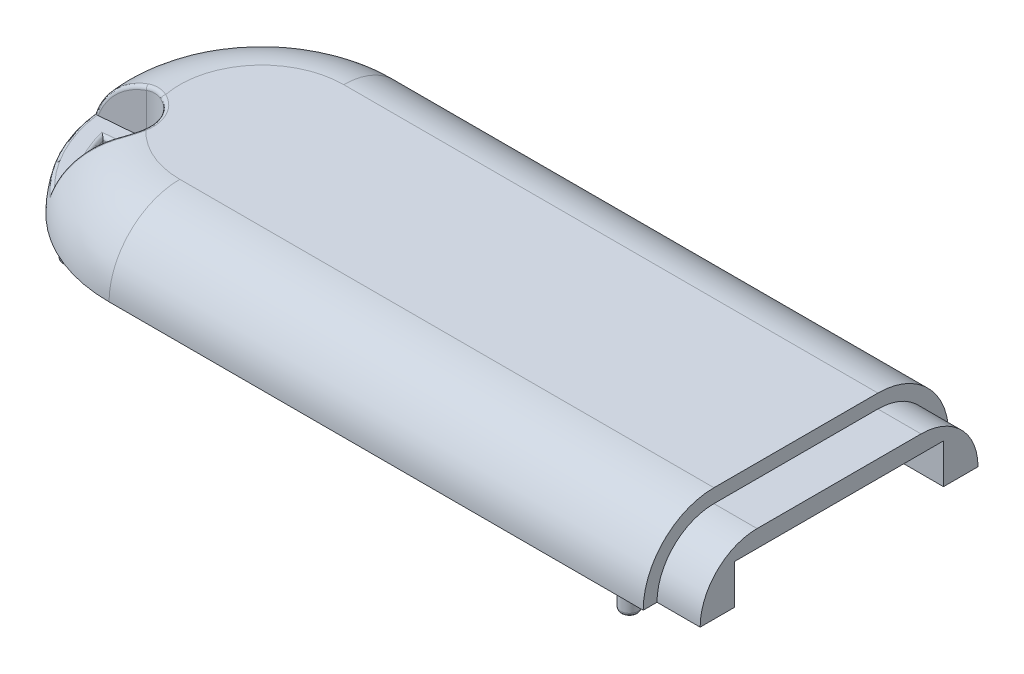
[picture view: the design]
ISO-10303-21;
HEADER;
FILE_DESCRIPTION(('STEP AP214'),'2;1');
FILE_NAME('part.step','',(''),(''),'','','');
FILE_SCHEMA(('AUTOMOTIVE_DESIGN { 1 0 10303 214 1 1 1 1 }'));
ENDSEC;
DATA;
#1=APPLICATION_CONTEXT('core data for automotive mechanical design processes');
#2=APPLICATION_PROTOCOL_DEFINITION('international standard','automotive_design',2000,#1);
#3=PRODUCT_CONTEXT('',#1,'mechanical');
#4=PRODUCT('Part','Part','',(#3));
#5=PRODUCT_RELATED_PRODUCT_CATEGORY('part','',(#4));
#6=PRODUCT_DEFINITION_FORMATION('','',#4);
#7=PRODUCT_DEFINITION_CONTEXT('part definition',#1,'design');
#8=PRODUCT_DEFINITION('design','',#6,#7);
#9=PRODUCT_DEFINITION_SHAPE('','',#8);
#10=(LENGTH_UNIT() NAMED_UNIT(*) SI_UNIT(.MILLI.,.METRE.));
#11=(NAMED_UNIT(*) PLANE_ANGLE_UNIT() SI_UNIT($,.RADIAN.));
#12=(NAMED_UNIT(*) SI_UNIT($,.STERADIAN.) SOLID_ANGLE_UNIT());
#13=UNCERTAINTY_MEASURE_WITH_UNIT(LENGTH_MEASURE(1.E-05),#10,'distance_accuracy_value','');
#14=(GEOMETRIC_REPRESENTATION_CONTEXT(3) GLOBAL_UNCERTAINTY_ASSIGNED_CONTEXT((#13)) GLOBAL_UNIT_ASSIGNED_CONTEXT((#10,
#11,#12)) REPRESENTATION_CONTEXT('',''));
#15=CARTESIAN_POINT('',(0.,0.,0.));
#16=DIRECTION('',(0.,0.,1.));
#17=DIRECTION('',(1.,0.,0.));
#18=AXIS2_PLACEMENT_3D('',#15,#16,#17);
#19=CARTESIAN_POINT('',(0.,0.,0.));
#20=DIRECTION('',(0.,1.,0.));
#21=DIRECTION('',(0.,0.,1.));
#22=AXIS2_PLACEMENT_3D('',#19,#20,#21);
#23=TOROIDAL_SURFACE('',#22,4.75,2.7);
#24=CARTESIAN_POINT('',(0.,0.5,0.));
#25=DIRECTION('',(0.,-1.,0.));
#26=DIRECTION('',(0.,0.,-1.));
#27=AXIS2_PLACEMENT_3D('',#24,#25,#26);
#28=CIRCLE('',#27,7.40329983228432);
#29=CARTESIAN_POINT('',(0.,0.5,-7.40329983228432));
#30=VERTEX_POINT('',#29);
#31=CARTESIAN_POINT('',(-7.36268520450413,0.5,-0.774412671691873));
#32=VERTEX_POINT('',#31);
#33=EDGE_CURVE('E1084',#30,#32,#28,.F.);
#34=ORIENTED_EDGE('',*,*,#33,.F.);
#35=CARTESIAN_POINT('',(0.,0.,-4.75));
#36=DIRECTION('',(1.,0.,0.));
#37=DIRECTION('',(0.,0.,-1.));
#38=AXIS2_PLACEMENT_3D('',#35,#36,#37);
#39=CIRCLE('',#38,2.7);
#40=CARTESIAN_POINT('',(0.,2.7,-4.75));
#41=VERTEX_POINT('',#40);
#42=EDGE_CURVE('E870',#30,#41,#39,.T.);
#43=ORIENTED_EDGE('',*,*,#42,.T.);
#44=CARTESIAN_POINT('',(0.,2.7,0.));
#45=DIRECTION('',(0.,1.,0.));
#46=DIRECTION('',(0.,0.,1.));
#47=AXIS2_PLACEMENT_3D('',#44,#45,#46);
#48=CIRCLE('',#47,4.75);
#49=CARTESIAN_POINT('',(-4.68321334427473,2.7,-0.793733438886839));
#50=VERTEX_POINT('',#49);
#51=EDGE_CURVE('E864',#41,#50,#48,.T.);
#52=ORIENTED_EDGE('',*,*,#51,.T.);
#53=CARTESIAN_POINT('',(-3.42079294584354,2.3539734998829,-0.215508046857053));
#54=CARTESIAN_POINT('',(-3.47788162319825,2.38742536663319,-0.255686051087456));
#55=CARTESIAN_POINT('',(-3.53679266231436,2.41916997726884,-0.294791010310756));
#56=CARTESIAN_POINT('',(-3.6583116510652,2.47858652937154,-0.370546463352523));
#57=CARTESIAN_POINT('',(-3.7209263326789,2.5062507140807,-0.407192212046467));
#58=CARTESIAN_POINT('',(-3.84992042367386,2.55680759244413,-0.477693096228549));
#59=CARTESIAN_POINT('',(-3.9163125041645,2.57968285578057,-0.51153777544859));
#60=CARTESIAN_POINT('',(-4.05228294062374,2.61988542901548,-0.575789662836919));
#61=CARTESIAN_POINT('',(-4.12185873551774,2.63721711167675,-0.60619956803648));
#62=CARTESIAN_POINT('',(-4.30790852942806,2.6746851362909,-0.680828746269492));
#63=CARTESIAN_POINT('',(-4.42671219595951,2.68989698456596,-0.721918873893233));
#64=CARTESIAN_POINT('',(-4.66838886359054,2.7028523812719,-0.792127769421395));
#65=CARTESIAN_POINT('',(-4.7912502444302,2.7006421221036,-0.821277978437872));
#66=CARTESIAN_POINT('',(-5.0378610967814,2.67859738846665,-0.867041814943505));
#67=CARTESIAN_POINT('',(-5.16161146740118,2.65874146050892,-0.883640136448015));
#68=CARTESIAN_POINT('',(-5.40633578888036,2.60206237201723,-0.90457184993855));
#69=CARTESIAN_POINT('',(-5.52730766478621,2.56522693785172,-0.908896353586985));
#70=CARTESIAN_POINT('',(-5.69292352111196,2.50256274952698,-0.907277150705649));
#71=CARTESIAN_POINT('',(-5.74019864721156,2.4832047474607,-0.905908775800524));
#72=CARTESIAN_POINT('',(-5.83343472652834,2.44209645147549,-0.901507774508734));
#73=CARTESIAN_POINT('',(-5.87939945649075,2.42035414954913,-0.898480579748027));
#74=CARTESIAN_POINT('',(-5.92472459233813,2.39743450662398,-0.89468786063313));
#75=B_SPLINE_CURVE_WITH_KNOTS('',3,(#53,#54,#55,#56,#57,#58,#59,#60,#61,#62,#63,#64,#65,#66,#67,
#68,#69,#70,#71,#72,#73,#74),.UNSPECIFIED.,.F.,.F.,(4,2,2,2,2,2,2,2,2,2,4),(0.,
0.232257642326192,0.464951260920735,0.698477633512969,0.931819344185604,1.30984644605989,
1.68687159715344,2.06435576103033,2.44211321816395,2.59534610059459,2.74808021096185),.UNSPECIFIED.);
#76=CARTESIAN_POINT('',(-5.92452459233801,2.39753564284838,-0.894704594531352));
#77=VERTEX_POINT('',#76);
#78=EDGE_CURVE('E787',#50,#77,#75,.T.);
#79=ORIENTED_EDGE('',*,*,#78,.T.);
#80=CARTESIAN_POINT('',(-7.41005437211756,-0.0002,-0.77045057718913));
#81=CARTESIAN_POINT('',(-7.41006776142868,0.074673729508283,-0.770449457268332));
#82=CARTESIAN_POINT('',(-7.40690693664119,0.149544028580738,-0.770713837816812));
#83=CARTESIAN_POINT('',(-7.39429669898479,0.298744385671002,-0.771768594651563));
#84=CARTESIAN_POINT('',(-7.38484772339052,0.373074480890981,-0.772558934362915));
#85=CARTESIAN_POINT('',(-7.35973704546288,0.520577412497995,-0.774659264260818));
#86=CARTESIAN_POINT('',(-7.34408328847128,0.593751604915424,-0.775968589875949));
#87=CARTESIAN_POINT('',(-7.30669763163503,0.738497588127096,-0.779095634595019));
#88=CARTESIAN_POINT('',(-7.28496579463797,0.810069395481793,-0.780913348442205));
#89=CARTESIAN_POINT('',(-7.21085476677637,1.0216638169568,-0.787112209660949));
#90=CARTESIAN_POINT('',(-7.14954457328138,1.15865576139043,-0.792240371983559));
#91=CARTESIAN_POINT('',(-7.00500644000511,1.42039988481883,-0.804329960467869));
#92=CARTESIAN_POINT('',(-6.92177295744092,1.54514895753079,-0.811291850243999));
#93=CARTESIAN_POINT('',(-6.73529747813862,1.7797913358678,-0.826889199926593));
#94=CARTESIAN_POINT('',(-6.63193591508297,1.88958885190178,-0.835534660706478));
#95=CARTESIAN_POINT('',(-6.40861580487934,2.09043949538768,-0.854213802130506));
#96=CARTESIAN_POINT('',(-6.28867809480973,2.18151580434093,-0.864245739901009));
#97=CARTESIAN_POINT('',(-6.12376430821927,2.28666466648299,-0.878039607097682));
#98=CARTESIAN_POINT('',(-6.08460921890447,2.31027004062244,-0.881314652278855));
#99=CARTESIAN_POINT('',(-6.0052498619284,2.35545961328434,-0.887952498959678));
#100=CARTESIAN_POINT('',(-5.96504759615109,2.37704735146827,-0.891315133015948));
#101=CARTESIAN_POINT('',(-5.92432459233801,2.3976367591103,-0.894721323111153));
#102=B_SPLINE_CURVE_WITH_KNOTS('',3,(#80,#81,#82,#83,#84,#85,#86,#87,#88,#89,#90,#91,#92,#93,
#94,#95,#96,#97,#98,#99,#100,#101),.UNSPECIFIED.,.F.,.F.,(4,2,2,2,2,2,2,2,2,2,4),(0.,
0.224547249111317,0.449078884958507,0.673323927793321,0.897566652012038,1.34578059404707,
1.79410796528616,2.24518456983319,2.69569921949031,2.83317292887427,2.97040074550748),.UNSPECIFIED.);
#103=EDGE_CURVE('E769',#32,#77,#102,.T.);
#104=ORIENTED_EDGE('',*,*,#103,.F.);
#105=EDGE_LOOP('',(#34,#43,#52,#79,#104));
#106=FACE_BOUND('',#105,.T.);
#107=ADVANCED_FACE('F85',(#106),#23,.F.);
#108=CARTESIAN_POINT('',(0.,0.5,0.));
#109=DIRECTION('',(0.,-1.,0.));
#110=DIRECTION('',(0.,0.,-1.));
#111=AXIS2_PLACEMENT_3D('',#108,#109,#110);
#112=CIRCLE('',#111,7.40329983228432);
#113=CARTESIAN_POINT('',(-3.63803915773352,0.5,6.44775305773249));
#114=VERTEX_POINT('',#113);
#115=CARTESIAN_POINT('',(0.,0.5,7.40329983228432));
#116=VERTEX_POINT('',#115);
#117=EDGE_CURVE('E1081',#114,#116,#112,.F.);
#118=ORIENTED_EDGE('',*,*,#117,.F.);
#119=CARTESIAN_POINT('',(-2.70599614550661,2.39766760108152,5.34556070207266));
#120=CARTESIAN_POINT('',(-2.75018498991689,2.36320321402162,5.39781645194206));
#121=CARTESIAN_POINT('',(-2.79344880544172,2.32589362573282,5.44897830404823));
#122=CARTESIAN_POINT('',(-2.87782626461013,2.24582969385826,5.54875931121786));
#123=CARTESIAN_POINT('',(-2.91893975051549,2.20307495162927,5.59737827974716));
#124=CARTESIAN_POINT('',(-2.99869787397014,2.11238512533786,5.69169666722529));
#125=CARTESIAN_POINT('',(-3.0373432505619,2.06445160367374,5.73739696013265));
#126=CARTESIAN_POINT('',(-3.11187878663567,1.96373092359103,5.82553934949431));
#127=CARTESIAN_POINT('',(-3.14776907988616,1.91094400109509,5.86798160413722));
#128=CARTESIAN_POINT('',(-3.25096207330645,1.74568881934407,5.99001302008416));
#129=CARTESIAN_POINT('',(-3.31378028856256,1.62633364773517,6.06429903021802));
#130=CARTESIAN_POINT('',(-3.42532474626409,1.37282402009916,6.19620651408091));
#131=CARTESIAN_POINT('',(-3.47405085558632,1.23866942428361,6.25382783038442));
#132=CARTESIAN_POINT('',(-3.55537391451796,0.961322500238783,6.34999684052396));
#133=CARTESIAN_POINT('',(-3.58818137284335,0.818278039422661,6.38879347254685));
#134=CARTESIAN_POINT('',(-3.63758389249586,0.525756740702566,6.44721468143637));
#135=CARTESIAN_POINT('',(-3.65420591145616,0.376291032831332,6.4668711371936));
#136=CARTESIAN_POINT('',(-3.6645868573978,0.188314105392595,6.4791471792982));
#137=CARTESIAN_POINT('',(-3.66614397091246,0.150620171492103,6.48098855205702));
#138=CARTESIAN_POINT('',(-3.6682162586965,0.0752220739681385,6.48343914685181));
#139=CARTESIAN_POINT('',(-3.66873304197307,0.0375180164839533,6.4840502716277));
#140=CARTESIAN_POINT('',(-3.66873259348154,-0.000199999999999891,6.48404974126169));
#141=B_SPLINE_CURVE_WITH_KNOTS('',3,(#119,#120,#121,#122,#123,#124,#125,#126,#127,#128,#129,
#130,#131,#132,#133,#134,#135,#136,#137,#138,#139,#140),.UNSPECIFIED.,.F.,.F.,(4,2,2,2,2,2,2,2,
2,2,4),(0.,0.229803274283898,0.459623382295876,0.689374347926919,0.919114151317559,
1.37863130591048,1.83815280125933,2.29141969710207,2.74393035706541,2.85722316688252,
2.97034061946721),.UNSPECIFIED.);
#142=CARTESIAN_POINT('',(-2.70616527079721,2.39753564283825,5.34576070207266));
#143=VERTEX_POINT('',#142);
#144=EDGE_CURVE('E1004',#143,#114,#141,.T.);
#145=ORIENTED_EDGE('',*,*,#144,.F.);
#146=CARTESIAN_POINT('',(-2.70633440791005,2.3974036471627,5.34596070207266));
#147=CARTESIAN_POINT('',(-2.66864775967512,2.42681168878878,5.30140023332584));
#148=CARTESIAN_POINT('',(-2.63138005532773,2.45428231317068,5.25524951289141));
#149=CARTESIAN_POINT('',(-2.55804237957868,2.50516944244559,5.1598214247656));
#150=CARTESIAN_POINT('',(-2.52197305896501,2.52858377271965,5.11054239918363));
#151=CARTESIAN_POINT('',(-2.41816889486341,2.59121860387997,4.96105632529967));
#152=CARTESIAN_POINT('',(-2.35265281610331,2.62451945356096,4.8566509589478));
#153=CARTESIAN_POINT('',(-2.26301693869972,2.66063239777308,4.69651252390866));
#154=CARTESIAN_POINT('',(-2.23530264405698,2.67025916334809,4.64418238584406));
#155=CARTESIAN_POINT('',(-2.18213263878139,2.6855619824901,4.53779836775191));
#156=CARTESIAN_POINT('',(-2.15667704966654,2.69123782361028,4.48374439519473));
#157=CARTESIAN_POINT('',(-2.10762153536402,2.69868817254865,4.37281829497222));
#158=CARTESIAN_POINT('',(-2.08408860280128,2.70035538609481,4.3159094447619));
#159=CARTESIAN_POINT('',(-2.03981587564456,2.69951661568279,4.20103660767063));
#160=CARTESIAN_POINT('',(-2.01907645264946,2.69701007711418,4.14307248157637));
#161=CARTESIAN_POINT('',(-1.99981816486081,2.69243649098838,4.08478180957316));
#162=B_SPLINE_CURVE_WITH_KNOTS('',3,(#146,#147,#148,#149,#150,#151,#152,#153,#154,#155,#156,
#157,#158,#159,#160,#161),.UNSPECIFIED.,.F.,.F.,(4,2,2,2,2,2,2,4),(0.,0.195937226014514,
0.391979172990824,0.772914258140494,0.952744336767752,1.13258408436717,1.31718629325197,
1.50181303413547),.UNSPECIFIED.);
#163=CARTESIAN_POINT('',(-2.06870125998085,2.7,4.27585957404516));
#164=VERTEX_POINT('',#163);
#165=EDGE_CURVE('E779',#143,#164,#162,.T.);
#166=ORIENTED_EDGE('',*,*,#165,.T.);
#167=CARTESIAN_POINT('',(0.,2.7,0.));
#168=DIRECTION('',(0.,1.,0.));
#169=DIRECTION('',(0.,0.,1.));
#170=AXIS2_PLACEMENT_3D('',#167,#168,#169);
#171=CIRCLE('',#170,4.75);
#172=CARTESIAN_POINT('',(0.,2.7,4.75));
#173=VERTEX_POINT('',#172);
#174=EDGE_CURVE('E869',#164,#173,#171,.T.);
#175=ORIENTED_EDGE('',*,*,#174,.T.);
#176=CARTESIAN_POINT('',(0.,0.,4.75));
#177=DIRECTION('',(-1.,0.,0.));
#178=DIRECTION('',(0.,0.,1.));
#179=AXIS2_PLACEMENT_3D('',#176,#177,#178);
#180=CIRCLE('',#179,2.7);
#181=EDGE_CURVE('E873',#116,#173,#180,.T.);
#182=ORIENTED_EDGE('',*,*,#181,.F.);
#183=EDGE_LOOP('',(#118,#145,#166,#175,#182));
#184=FACE_BOUND('',#183,.T.);
#185=ADVANCED_FACE('F753',(#184),#23,.F.);
#186=CARTESIAN_POINT('',(33.45,0.,4.75));
#187=DIRECTION('',(-1.,0.,0.));
#188=DIRECTION('',(0.,0.,1.));
#189=AXIS2_PLACEMENT_3D('',#186,#187,#188);
#190=CYLINDRICAL_SURFACE('',#189,2.7);
#191=CARTESIAN_POINT('',(29.55,0.,4.75));
#192=DIRECTION('',(1.,0.,0.));
#193=DIRECTION('',(0.,0.,-1.));
#194=AXIS2_PLACEMENT_3D('',#191,#192,#193);
#195=CIRCLE('',#194,2.7);
#196=CARTESIAN_POINT('',(29.55,1.65413192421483,6.88397459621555));
#197=VERTEX_POINT('',#196);
#198=CARTESIAN_POINT('',(29.55,2.7,4.75));
#199=VERTEX_POINT('',#198);
#200=EDGE_CURVE('E874',#197,#199,#195,.F.);
#201=ORIENTED_EDGE('',*,*,#200,.F.);
#202=CARTESIAN_POINT('',(29.55,1.65413192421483,6.88397459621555));
#203=CARTESIAN_POINT('',(29.5199788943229,1.67655530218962,6.8665976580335));
#204=CARTESIAN_POINT('',(29.4878307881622,1.6970168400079,6.85016512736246));
#205=CARTESIAN_POINT('',(29.4197369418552,1.73353284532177,6.82012609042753));
#206=CARTESIAN_POINT('',(29.3837764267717,1.74956922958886,6.80653123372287));
#207=CARTESIAN_POINT('',(29.308606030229,1.77661921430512,6.78321143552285));
#208=CARTESIAN_POINT('',(29.26938298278,1.7876111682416,6.77350319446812));
#209=CARTESIAN_POINT('',(29.1890064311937,1.80404166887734,6.75886954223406));
#210=CARTESIAN_POINT('',(29.1478572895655,1.809492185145,6.75393382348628));
#211=CARTESIAN_POINT('',(29.0673739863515,1.81451420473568,6.74938702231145));
#212=CARTESIAN_POINT('',(29.0280769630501,1.81441527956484,6.74947744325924));
#213=CARTESIAN_POINT('',(28.9500872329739,1.80915625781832,6.75423699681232));
#214=CARTESIAN_POINT('',(28.9113948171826,1.80399379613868,6.75890826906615));
#215=CARTESIAN_POINT('',(28.8369095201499,1.78901459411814,6.77225669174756));
#216=CARTESIAN_POINT('',(28.8010643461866,1.77934326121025,6.78080848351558));
#217=CARTESIAN_POINT('',(28.7318536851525,1.755713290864,6.80127127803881));
#218=CARTESIAN_POINT('',(28.6984881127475,1.741754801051,6.81318216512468));
#219=CARTESIAN_POINT('',(28.6325109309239,1.70880649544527,6.84056656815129));
#220=CARTESIAN_POINT('',(28.6001258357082,1.68952718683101,6.85623460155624));
#221=CARTESIAN_POINT('',(28.5392006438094,1.64707484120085,6.88959710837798));
#222=CARTESIAN_POINT('',(28.5106626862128,1.62389965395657,6.9072926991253));
#223=CARTESIAN_POINT('',(28.4439354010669,1.56157400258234,6.95309628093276));
#224=CARTESIAN_POINT('',(28.408223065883,1.52029476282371,6.98192119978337));
#225=CARTESIAN_POINT('',(28.3448888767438,1.43196281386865,7.03960235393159));
#226=CARTESIAN_POINT('',(28.3172838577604,1.38489837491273,7.06845853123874));
#227=CARTESIAN_POINT('',(28.2750937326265,1.29906075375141,7.11732490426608));
#228=CARTESIAN_POINT('',(28.2589833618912,1.26123063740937,7.13771558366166));
#229=CARTESIAN_POINT('',(28.2300022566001,1.18364794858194,7.17711241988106));
#230=CARTESIAN_POINT('',(28.2171331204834,1.14389443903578,7.19611789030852));
#231=CARTESIAN_POINT('',(28.1824911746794,1.02198812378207,7.25069164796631));
#232=CARTESIAN_POINT('',(28.1648140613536,0.937477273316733,7.28365120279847));
#233=CARTESIAN_POINT('',(28.1398048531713,0.78271824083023,7.33506673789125));
#234=CARTESIAN_POINT('',(28.1310817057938,0.713188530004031,7.35511452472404));
#235=CARTESIAN_POINT('',(28.1170020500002,0.572355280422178,7.38963304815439));
#236=CARTESIAN_POINT('',(28.1116485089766,0.501050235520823,7.40409886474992));
#237=CARTESIAN_POINT('',(28.1034947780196,0.358298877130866,7.42708486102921));
#238=CARTESIAN_POINT('',(28.1006624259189,0.286866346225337,7.43567959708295));
#239=CARTESIAN_POINT('',(28.0978771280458,0.179411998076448,7.44427191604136));
#240=CARTESIAN_POINT('',(28.0971925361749,0.143567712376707,7.44641938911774));
#241=CARTESIAN_POINT('',(28.0962857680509,0.0718169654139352,7.44928347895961));
#242=CARTESIAN_POINT('',(28.0960635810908,0.0359105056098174,7.45000012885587));
#243=CARTESIAN_POINT('',(28.0960607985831,0.,7.45));
#244=B_SPLINE_CURVE_WITH_KNOTS('',3,(#202,#203,#204,#205,#206,#207,#208,#209,#210,#211,#212,
#213,#214,#215,#216,#217,#218,#219,#220,#221,#222,#223,#224,#225,#226,#227,#228,#229,#230,#231,
#232,#233,#234,#235,#236,#237,#238,#239,#240,#241,#242,#243),.UNSPECIFIED.,.F.,.F.,(4,2,2,2,2,2,
2,2,2,2,2,2,2,2,2,2,2,2,2,2,4),(0.,0.123934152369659,0.248367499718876,0.373329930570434,
0.49802186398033,0.615316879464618,0.732666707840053,0.846469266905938,0.960267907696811,
1.0822449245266,1.20428948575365,1.38842890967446,1.57294804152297,1.71045038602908,
1.84802040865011,2.12421848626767,2.342588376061,2.56115030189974,2.77688238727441,
2.88460037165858,2.99231586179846),.UNSPECIFIED.);
#245=CARTESIAN_POINT('',(28.1120239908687,0.5,7.40329983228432));
#246=VERTEX_POINT('',#245);
#247=EDGE_CURVE('E418',#197,#246,#244,.T.);
#248=ORIENTED_EDGE('',*,*,#247,.T.);
#249=DIRECTION('',(-1.,0.,0.));
#250=VECTOR('',#249,1.);
#251=CARTESIAN_POINT('',(33.45,0.5,7.40329983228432));
#252=LINE('',#251,#250);
#253=EDGE_CURVE('E1090',#116,#246,#252,.F.);
#254=ORIENTED_EDGE('',*,*,#253,.F.);
#255=ORIENTED_EDGE('',*,*,#181,.T.);
#256=DIRECTION('',(1.,0.,0.));
#257=VECTOR('',#256,1.);
#258=CARTESIAN_POINT('',(0.,2.7,4.75));
#259=LINE('',#258,#257);
#260=EDGE_CURVE('E868',#173,#199,#259,.T.);
#261=ORIENTED_EDGE('',*,*,#260,.T.);
#262=EDGE_LOOP('',(#201,#248,#254,#255,#261));
#263=FACE_BOUND('',#262,.T.);
#264=ADVANCED_FACE('F434',(#263),#190,.F.);
#265=CARTESIAN_POINT('',(0.,0.,-4.75));
#266=DIRECTION('',(1.,0.,0.));
#267=DIRECTION('',(0.,0.,-1.));
#268=AXIS2_PLACEMENT_3D('',#265,#266,#267);
#269=CYLINDRICAL_SURFACE('',#268,2.7);
#270=DIRECTION('',(1.,0.,0.));
#271=VECTOR('',#270,1.);
#272=CARTESIAN_POINT('',(0.,0.5,-7.40329983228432));
#273=LINE('',#272,#271);
#274=CARTESIAN_POINT('',(28.1120239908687,0.5,-7.40329983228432));
#275=VERTEX_POINT('',#274);
#276=EDGE_CURVE('E1087',#275,#30,#273,.F.);
#277=ORIENTED_EDGE('',*,*,#276,.F.);
#278=CARTESIAN_POINT('',(28.0960607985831,0.,-7.45));
#279=CARTESIAN_POINT('',(28.096063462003,0.0354762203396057,-7.45000005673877));
#280=CARTESIAN_POINT('',(28.0962803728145,0.0709483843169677,-7.44930067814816));
#281=CARTESIAN_POINT('',(28.0971651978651,0.141833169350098,-7.44650547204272));
#282=CARTESIAN_POINT('',(28.0978331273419,0.177245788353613,-7.44440959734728));
#283=CARTESIAN_POINT('',(28.10054956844,0.283406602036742,-7.43602358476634));
#284=CARTESIAN_POINT('',(28.1033108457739,0.353984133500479,-7.42763506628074));
#285=CARTESIAN_POINT('',(28.1112354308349,0.494846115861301,-7.40523355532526));
#286=CARTESIAN_POINT('',(28.116423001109,0.565120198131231,-7.39116395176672));
#287=CARTESIAN_POINT('',(28.1300334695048,0.70398272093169,-7.35758616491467));
#288=CARTESIAN_POINT('',(28.1384535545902,0.772572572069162,-7.33808271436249));
#289=CARTESIAN_POINT('',(28.1619030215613,0.921323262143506,-7.28938526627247));
#290=CARTESIAN_POINT('',(28.1779370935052,1.00095444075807,-7.25902240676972));
#291=CARTESIAN_POINT('',(28.219222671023,1.15480262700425,-7.19200898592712));
#292=CARTESIAN_POINT('',(28.2444378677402,1.22903959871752,-7.15538349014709));
#293=CARTESIAN_POINT('',(28.2986826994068,1.34979994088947,-7.08909601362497));
#294=CARTESIAN_POINT('',(28.3246178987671,1.3982242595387,-7.06039322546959));
#295=CARTESIAN_POINT('',(28.3844154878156,1.48964732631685,-7.00252226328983));
#296=CARTESIAN_POINT('',(28.4182666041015,1.53265365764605,-6.97335480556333));
#297=CARTESIAN_POINT('',(28.4858506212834,1.60223996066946,-6.923526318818));
#298=CARTESIAN_POINT('',(28.5177526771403,1.63030767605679,-6.90247350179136));
#299=CARTESIAN_POINT('',(28.5868112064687,1.68134239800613,-6.86284873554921));
#300=CARTESIAN_POINT('',(28.6239660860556,1.70431094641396,-6.8442760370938));
#301=CARTESIAN_POINT('',(28.7034057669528,1.74442358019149,-6.81098933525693));
#302=CARTESIAN_POINT('',(28.7457338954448,1.76151315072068,-6.79631172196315));
#303=CARTESIAN_POINT('',(28.8340455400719,1.78877182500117,-6.77253044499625));
#304=CARTESIAN_POINT('',(28.8800260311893,1.79894659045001,-6.76342222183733));
#305=CARTESIAN_POINT('',(28.9668908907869,1.81093147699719,-6.75264334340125));
#306=CARTESIAN_POINT('',(29.0075275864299,1.81375337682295,-6.75007437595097));
#307=CARTESIAN_POINT('',(29.0887973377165,1.81391433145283,-6.7499289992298));
#308=CARTESIAN_POINT('',(29.129430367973,1.81125797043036,-6.75234841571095));
#309=CARTESIAN_POINT('',(29.2066826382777,1.80093376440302,-6.76163607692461));
#310=CARTESIAN_POINT('',(29.2433877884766,1.79361588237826,-6.76819337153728));
#311=CARTESIAN_POINT('',(29.3147785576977,1.77453221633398,-6.78499292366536));
#312=CARTESIAN_POINT('',(29.3494618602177,1.76276144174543,-6.7952393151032));
#313=CARTESIAN_POINT('',(29.413197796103,1.73630987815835,-6.81772832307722));
#314=CARTESIAN_POINT('',(29.4424784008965,1.7219623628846,-6.82972656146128));
#315=CARTESIAN_POINT('',(29.4983171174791,1.69023560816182,-6.85559361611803));
#316=CARTESIAN_POINT('',(29.5248838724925,1.6728665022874,-6.86945614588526));
#317=CARTESIAN_POINT('',(29.55,1.65413192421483,-6.88397459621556));
#318=B_SPLINE_CURVE_WITH_KNOTS('',3,(#278,#279,#280,#281,#282,#283,#284,#285,#286,#287,#288,
#289,#290,#291,#292,#293,#294,#295,#296,#297,#298,#299,#300,#301,#302,#303,#304,#305,#306,#307,
#308,#309,#310,#311,#312,#313,#314,#315,#316,#317),.UNSPECIFIED.,.F.,.F.,(4,2,2,2,2,2,2,2,2,2,2,
2,2,2,2,2,2,2,2,4),(0.,0.106412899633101,0.212829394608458,0.425942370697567,0.641233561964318,
0.856337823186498,1.11578711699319,1.37422130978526,1.55958309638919,1.7446824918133,
1.88641033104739,2.02809525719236,2.17106066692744,2.31390887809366,2.43570406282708,
2.55739737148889,2.67088579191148,2.78450178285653,2.8884400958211,2.99203632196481),.UNSPECIFIED.);
#319=CARTESIAN_POINT('',(29.55,1.65413192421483,-6.88397459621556));
#320=VERTEX_POINT('',#319);
#321=EDGE_CURVE('E396',#275,#320,#318,.T.);
#322=ORIENTED_EDGE('',*,*,#321,.T.);
#323=CARTESIAN_POINT('',(29.55,0.,-4.75));
#324=DIRECTION('',(1.,0.,0.));
#325=DIRECTION('',(0.,0.,-1.));
#326=AXIS2_PLACEMENT_3D('',#323,#324,#325);
#327=CIRCLE('',#326,2.7);
#328=CARTESIAN_POINT('',(29.55,2.7,-4.75));
#329=VERTEX_POINT('',#328);
#330=EDGE_CURVE('E892',#329,#320,#327,.F.);
#331=ORIENTED_EDGE('',*,*,#330,.F.);
#332=DIRECTION('',(1.,0.,0.));
#333=VECTOR('',#332,1.);
#334=CARTESIAN_POINT('',(0.,2.7,-4.75));
#335=LINE('',#334,#333);
#336=EDGE_CURVE('E884',#329,#41,#335,.F.);
#337=ORIENTED_EDGE('',*,*,#336,.T.);
#338=ORIENTED_EDGE('',*,*,#42,.F.);
#339=EDGE_LOOP('',(#277,#322,#331,#337,#338));
#340=FACE_BOUND('',#339,.T.);
#341=ADVANCED_FACE('F462',(#340),#269,.F.);
#342=CARTESIAN_POINT('',(-5.92452459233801,12.1296515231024,-0.894704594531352));
#343=DIRECTION('',(0.0833518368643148,0.,0.9965201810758));
#344=DIRECTION('',(0.9965201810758,0.,-0.0833518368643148));
#345=AXIS2_PLACEMENT_3D('',#342,#343,#344);
#346=PLANE('',#345);
#347=DIRECTION('',(0.9965201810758,0.,-0.0833518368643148));
#348=VECTOR('',#347,1.);
#349=CARTESIAN_POINT('',(-5.92452459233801,0.5,-0.894704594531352));
#350=LINE('',#349,#348);
#351=CARTESIAN_POINT('',(-5.92452459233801,0.5,-0.894704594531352));
#352=VERTEX_POINT('',#351);
#353=EDGE_CURVE('E1078',#32,#352,#350,.T.);
#354=ORIENTED_EDGE('',*,*,#353,.F.);
#355=ORIENTED_EDGE('',*,*,#103,.T.);
#356=DIRECTION('',(0.,-1.,0.));
#357=VECTOR('',#356,1.);
#358=CARTESIAN_POINT('',(-5.92452459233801,12.1296515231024,-0.894704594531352));
#359=LINE('',#358,#357);
#360=EDGE_CURVE('E1098',#77,#352,#359,.T.);
#361=ORIENTED_EDGE('',*,*,#360,.T.);
#362=EDGE_LOOP('',(#354,#355,#361));
#363=FACE_BOUND('',#362,.T.);
#364=ADVANCED_FACE('F466',(#363),#346,.F.);
#365=CARTESIAN_POINT('',(-3.81259819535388,12.1296515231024,6.65417876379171));
#366=DIRECTION('',(-0.763584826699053,0.,-0.645707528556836));
#367=DIRECTION('',(-0.645707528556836,0.,0.763584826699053));
#368=AXIS2_PLACEMENT_3D('',#365,#366,#367);
#369=PLANE('',#368);
#370=DIRECTION('',(-0.645707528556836,0.,0.763584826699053));
#371=VECTOR('',#370,1.);
#372=CARTESIAN_POINT('',(-3.81259819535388,0.5,6.65417876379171));
#373=LINE('',#372,#371);
#374=CARTESIAN_POINT('',(-2.70616527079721,0.5,5.34576070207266));
#375=VERTEX_POINT('',#374);
#376=EDGE_CURVE('E1064',#375,#114,#373,.T.);
#377=ORIENTED_EDGE('',*,*,#376,.F.);
#378=DIRECTION('',(0.,-1.,0.));
#379=VECTOR('',#378,1.);
#380=CARTESIAN_POINT('',(-2.70616527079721,12.1296515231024,5.34576070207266));
#381=LINE('',#380,#379);
#382=EDGE_CURVE('E1097',#143,#375,#381,.T.);
#383=ORIENTED_EDGE('',*,*,#382,.F.);
#384=ORIENTED_EDGE('',*,*,#144,.T.);
#385=EDGE_LOOP('',(#377,#383,#384));
#386=FACE_BOUND('',#385,.T.);
#387=ADVANCED_FACE('F801',(#386),#369,.F.);
#388=CARTESIAN_POINT('',(-5.60778761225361,12.1296515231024,2.89207209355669));
#389=DIRECTION('',(0.,-1.,0.));
#390=DIRECTION('',(0.,0.,-1.));
#391=AXIS2_PLACEMENT_3D('',#388,#389,#390);
#392=CYLINDRICAL_SURFACE('',#391,3.8);
#393=ORIENTED_EDGE('',*,*,#382,.T.);
#394=CARTESIAN_POINT('',(-5.60778761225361,0.5,2.89207209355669));
#395=DIRECTION('',(0.,-1.,0.));
#396=DIRECTION('',(0.,0.,-1.));
#397=AXIS2_PLACEMENT_3D('',#394,#395,#396);
#398=CIRCLE('',#397,3.8);
#399=EDGE_CURVE('E1106',#375,#352,#398,.F.);
#400=ORIENTED_EDGE('',*,*,#399,.T.);
#401=ORIENTED_EDGE('',*,*,#360,.F.);
#402=ORIENTED_EDGE('',*,*,#78,.F.);
#403=CARTESIAN_POINT('',(-5.60778761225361,2.7,2.89207209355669));
#404=DIRECTION('',(0.,1.,0.));
#405=DIRECTION('',(0.,0.,1.));
#406=AXIS2_PLACEMENT_3D('',#403,#404,#405);
#407=CIRCLE('',#406,3.8);
#408=EDGE_CURVE('E1094',#50,#164,#407,.F.);
#409=ORIENTED_EDGE('',*,*,#408,.T.);
#410=ORIENTED_EDGE('',*,*,#165,.F.);
#411=EDGE_LOOP('',(#393,#400,#401,#402,#409,#410));
#412=FACE_BOUND('',#411,.T.);
#413=ADVANCED_FACE('F797',(#412),#392,.T.);
#414=CARTESIAN_POINT('',(0.,0.,0.));
#415=DIRECTION('',(0.,1.,0.));
#416=DIRECTION('',(0.,0.,1.));
#417=AXIS2_PLACEMENT_3D('',#414,#415,#416);
#418=TOROIDAL_SURFACE('',#417,4.75,4.1);
#419=CARTESIAN_POINT('',(0.,4.1,0.));
#420=DIRECTION('',(0.,1.,0.));
#421=DIRECTION('',(0.,0.,1.));
#422=AXIS2_PLACEMENT_3D('',#419,#420,#421);
#423=CIRCLE('',#422,4.75);
#424=CARTESIAN_POINT('',(-3.44122990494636,4.1,3.27420780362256));
#425=VERTEX_POINT('',#424);
#426=CARTESIAN_POINT('',(0.,4.1,4.75));
#427=VERTEX_POINT('',#426);
#428=EDGE_CURVE('E982',#425,#427,#423,.T.);
#429=ORIENTED_EDGE('',*,*,#428,.F.);
#430=CARTESIAN_POINT('',(-3.6335585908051,3.87072392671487,2.5720412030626));
#431=CARTESIAN_POINT('',(-3.63557025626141,4.09343373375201,2.55963149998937));
#432=CARTESIAN_POINT('',(-3.4164664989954,4.06922258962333,2.52549838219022));
#433=CARTESIAN_POINT('',(-3.62463828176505,3.87418059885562,2.62709082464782));
#434=CARTESIAN_POINT('',(-3.62638213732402,4.09490207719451,2.61417983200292));
#435=CARTESIAN_POINT('',(-3.40799969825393,4.07285652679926,2.58665694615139));
#436=CARTESIAN_POINT('',(-3.61802133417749,3.87774580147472,2.68247788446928));
#437=CARTESIAN_POINT('',(-3.61934635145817,4.09642333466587,2.66973257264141));
#438=CARTESIAN_POINT('',(-3.40216484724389,4.07660456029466,2.64834954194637));
#439=CARTESIAN_POINT('',(-3.60943062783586,3.88454578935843,2.79365193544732));
#440=CARTESIAN_POINT('',(-3.6100023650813,4.09913472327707,2.78188392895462));
#441=CARTESIAN_POINT('',(-3.3957602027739,4.08375326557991,2.77248626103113));
#442=CARTESIAN_POINT('',(-3.60745894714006,3.88778042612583,2.84943909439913));
#443=CARTESIAN_POINT('',(-3.60764929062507,4.10032769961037,2.83845607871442));
#444=CARTESIAN_POINT('',(-3.39519276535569,4.08715378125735,2.8349307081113));
#445=CARTESIAN_POINT('',(-3.60857683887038,3.8961717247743,3.01712007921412));
#446=CARTESIAN_POINT('',(-3.60800186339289,4.10280497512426,3.00860317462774));
#447=CARTESIAN_POINT('',(-3.40140880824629,4.09597540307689,3.02306546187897));
#448=CARTESIAN_POINT('',(-3.61873271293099,3.89999889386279,3.12912727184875));
#449=CARTESIAN_POINT('',(-3.61786956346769,4.10304944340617,3.12425551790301));
#450=CARTESIAN_POINT('',(-3.41614207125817,4.09999883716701,3.14932808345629));
#451=CARTESIAN_POINT('',(-3.65582501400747,3.90000100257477,3.33947841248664));
#452=CARTESIAN_POINT('',(-3.65634393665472,4.09727559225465,3.34240052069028));
#453=CARTESIAN_POINT('',(-3.46396888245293,4.10000105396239,3.38739562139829));
#454=CARTESIAN_POINT('',(-3.68110133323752,3.8968588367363,3.4381197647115));
#455=CARTESIAN_POINT('',(-3.68294968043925,4.09190625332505,3.44561478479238));
#456=CARTESIAN_POINT('',(-3.49521429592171,4.09669775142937,3.49944736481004));
#457=CARTESIAN_POINT('',(-3.74605726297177,3.8820695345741,3.62972987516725));
#458=CARTESIAN_POINT('',(-3.75220422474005,4.07369555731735,3.6458446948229));
#459=CARTESIAN_POINT('',(-3.57366211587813,4.08115002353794,3.71776372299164));
#460=CARTESIAN_POINT('',(-3.78569239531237,3.87044855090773,3.7227151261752));
#461=CARTESIAN_POINT('',(-3.79494769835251,4.060861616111,3.7436562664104));
#462=CARTESIAN_POINT('',(-3.62081521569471,4.06893309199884,3.82404505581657));
#463=CARTESIAN_POINT('',(-3.86649946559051,3.84163113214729,3.87881325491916));
#464=CARTESIAN_POINT('',(-3.88237050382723,4.03089618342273,3.9071495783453));
#465=CARTESIAN_POINT('',(-3.71600630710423,4.03863785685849,4.00292558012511));
#466=CARTESIAN_POINT('',(-3.90493653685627,3.826487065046,3.94367889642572));
#467=CARTESIAN_POINT('',(-3.92424047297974,4.01550563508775,3.9752310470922));
#468=CARTESIAN_POINT('',(-3.76102088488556,4.02271717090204,4.07741550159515));
#469=CARTESIAN_POINT('',(-3.98821816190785,3.79064564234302,4.06791268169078));
#470=CARTESIAN_POINT('',(-4.01504318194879,3.97981340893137,4.10515157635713));
#471=CARTESIAN_POINT('',(-3.85812937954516,3.98503772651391,4.22034545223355));
#472=CARTESIAN_POINT('',(-4.03307266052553,3.76993962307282,4.12727205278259));
#473=CARTESIAN_POINT('',(-4.06422538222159,3.95939932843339,4.16723771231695));
#474=CARTESIAN_POINT('',(-3.91023427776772,3.96326986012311,4.28877581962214));
#475=CARTESIAN_POINT('',(-4.15317172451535,3.71081191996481,4.2692709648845));
#476=CARTESIAN_POINT('',(-4.19622242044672,3.90168906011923,4.31535292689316));
#477=CARTESIAN_POINT('',(-4.04935037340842,3.90110996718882,4.45277306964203));
#478=CARTESIAN_POINT('',(-4.23199142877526,3.66880062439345,4.34773285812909));
#479=CARTESIAN_POINT('',(-4.283448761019,3.86095197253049,4.39675177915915));
#480=CARTESIAN_POINT('',(-4.14030625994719,3.85694424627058,4.54368105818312));
#481=CARTESIAN_POINT('',(-4.35643120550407,3.59766900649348,4.45319169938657));
#482=CARTESIAN_POINT('',(-4.41994769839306,3.79343551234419,4.50424385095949));
#483=CARTESIAN_POINT('',(-4.28355417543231,3.78216485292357,4.66623532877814));
#484=CARTESIAN_POINT('',(-4.39897737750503,3.57258609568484,4.48632410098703));
#485=CARTESIAN_POINT('',(-4.46701564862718,3.76952959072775,4.53801213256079));
#486=CARTESIAN_POINT('',(-4.33247493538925,3.75579563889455,4.7048070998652));
#487=CARTESIAN_POINT('',(-4.48568733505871,3.51997005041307,4.54849020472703));
#488=CARTESIAN_POINT('',(-4.56294953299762,3.71963393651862,4.60094886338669));
#489=CARTESIAN_POINT('',(-4.43208397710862,3.70048133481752,4.77730961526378));
#490=CARTESIAN_POINT('',(-4.5298490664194,3.49243996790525,4.57752889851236));
#491=CARTESIAN_POINT('',(-4.61193269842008,3.6935680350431,4.63011776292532));
#492=CARTESIAN_POINT('',(-4.48277001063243,3.67153945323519,4.81124601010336));
#493=CARTESIAN_POINT('',(-4.57465204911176,3.46378065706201,4.60456469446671));
#494=CARTESIAN_POINT('',(-4.66120226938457,3.66678636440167,4.65677987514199));
#495=CARTESIAN_POINT('',(-4.53415553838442,3.64141043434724,4.84290852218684));
#496=(BOUNDED_SURFACE() B_SPLINE_SURFACE(3,2,((#430,#431,#432),(#433,#434,#435),(#436,#437,
#438),(#439,#440,#441),(#442,#443,#444),(#445,#446,#447),(#448,#449,#450),(#451,#452,#453),
(#454,#455,#456),(#457,#458,#459),(#460,#461,#462),(#463,#464,#465),(#466,#467,#468),(#469,#470,
#471),(#472,#473,#474),(#475,#476,#477),(#478,#479,#480),(#481,#482,#483),(#484,#485,#486),
(#487,#488,#489),(#490,#491,#492),(#493,#494,#495)),.UNSPECIFIED.,.F.,.F.,
.F.) B_SPLINE_SURFACE_WITH_KNOTS((4,2,2,2,2,2,2,2,2,2,4),(3,3),(0.,0.184205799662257,
0.368493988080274,0.737752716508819,1.07243948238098,1.40609825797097,1.65834159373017,
1.9109801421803,2.29650465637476,2.48953097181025,2.68231984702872),(0.,1.),
.UNSPECIFIED.) GEOMETRIC_REPRESENTATION_ITEM() RATIONAL_B_SPLINE_SURFACE(((1.,0.667565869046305,
1.),(1.,0.670819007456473,1.),(1.,0.67426528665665,1.),(1.,0.681261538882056,1.),(1.,
0.684811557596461,1.),(1.,0.695200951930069,1.),(1.,0.70176550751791,1.),(1.,0.711947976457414,
1.),(1.,0.715784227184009,1.),(1.,0.720766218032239,1.),(1.,0.721920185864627,1.),(1.,
0.721421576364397,1.),(1.,0.720385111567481,1.),(1.,0.716719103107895,1.),(1.,0.714087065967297,
1.),(1.,0.70555725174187,1.),(1.,0.698669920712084,1.),(1.,0.686201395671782,1.),(1.,
0.681685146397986,1.),(1.,0.672018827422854,1.),(1.,0.666869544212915,1.),(1.,0.661437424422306,1.))) REPRESENTATION_ITEM('') SURFACE());
#497=CARTESIAN_POINT('',(-3.4164664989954,4.06922258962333,2.52549838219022));
#498=CARTESIAN_POINT('',(-3.40799969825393,4.07285652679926,2.58665694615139));
#499=CARTESIAN_POINT('',(-3.40216484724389,4.07660456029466,2.64834954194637));
#500=CARTESIAN_POINT('',(-3.3957602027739,4.08375326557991,2.77248626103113));
#501=CARTESIAN_POINT('',(-3.39519276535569,4.08715378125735,2.8349307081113));
#502=CARTESIAN_POINT('',(-3.40140880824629,4.09597540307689,3.02306546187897));
#503=CARTESIAN_POINT('',(-3.41614207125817,4.09999883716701,3.14932808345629));
#504=CARTESIAN_POINT('',(-3.46396888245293,4.10000105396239,3.38739562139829));
#505=CARTESIAN_POINT('',(-3.49521429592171,4.09669775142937,3.49944736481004));
#506=CARTESIAN_POINT('',(-3.57366211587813,4.08115002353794,3.71776372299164));
#507=CARTESIAN_POINT('',(-3.62081521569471,4.06893309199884,3.82404505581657));
#508=CARTESIAN_POINT('',(-3.71600630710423,4.03863785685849,4.00292558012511));
#509=CARTESIAN_POINT('',(-3.76102088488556,4.02271717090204,4.07741550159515));
#510=CARTESIAN_POINT('',(-3.85812937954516,3.98503772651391,4.22034545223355));
#511=CARTESIAN_POINT('',(-3.91023427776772,3.96326986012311,4.28877581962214));
#512=CARTESIAN_POINT('',(-4.04935037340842,3.90110996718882,4.45277306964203));
#513=CARTESIAN_POINT('',(-4.14030625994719,3.85694424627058,4.54368105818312));
#514=CARTESIAN_POINT('',(-4.28355417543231,3.78216485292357,4.66623532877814));
#515=CARTESIAN_POINT('',(-4.33247493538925,3.75579563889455,4.7048070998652));
#516=CARTESIAN_POINT('',(-4.43208397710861,3.70048133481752,4.77730961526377));
#517=CARTESIAN_POINT('',(-4.48277001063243,3.67153945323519,4.81124601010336));
#518=CARTESIAN_POINT('',(-4.53415553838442,3.64141043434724,4.84290852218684));
#519=B_SPLINE_CURVE_WITH_KNOTS('',3,(#497,#498,#499,#500,#501,#502,#503,#504,#505,#506,#507,
#508,#509,#510,#511,#512,#513,#514,#515,#516,#517,#518),.UNSPECIFIED.,.F.,.F.,(4,2,2,2,2,2,2,2,
2,2,4),(0.,0.184205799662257,0.368493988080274,0.737752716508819,1.07243948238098,
1.40609825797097,1.65834159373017,1.9109801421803,2.29650465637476,2.48953097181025,
2.68231984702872),.UNSPECIFIED.);
#520=CARTESIAN_POINT('',(-3.965308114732,3.93866175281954,4.35369970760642));
#521=VERTEX_POINT('',#520);
#522=EDGE_CURVE('E692',#425,#521,#519,.T.);
#523=ORIENTED_EDGE('',*,*,#522,.T.);
#524=CARTESIAN_POINT('',(-3.8117553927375,3.84250485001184,3.8655423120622));
#525=CARTESIAN_POINT('',(-3.83368260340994,4.03822999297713,3.89147245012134));
#526=CARTESIAN_POINT('',(-3.68214916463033,4.03955638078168,4.01991451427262));
#527=CARTESIAN_POINT('',(-3.85705087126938,3.83032799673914,3.91910671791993));
#528=CARTESIAN_POINT('',(-3.88125385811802,4.02531549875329,3.94772808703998));
#529=CARTESIAN_POINT('',(-3.72985962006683,4.02675507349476,4.07614142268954));
#530=CARTESIAN_POINT('',(-3.90210931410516,3.81624804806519,3.97239081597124));
#531=CARTESIAN_POINT('',(-3.92858851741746,4.01040447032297,4.00370393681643));
#532=CARTESIAN_POINT('',(-3.77731690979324,4.01195307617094,4.13207741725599));
#533=CARTESIAN_POINT('',(-3.99176156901,3.7842607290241,4.07840956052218));
#534=CARTESIAN_POINT('',(-4.02276097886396,3.97657141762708,4.11506807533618));
#535=CARTESIAN_POINT('',(-3.87173600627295,3.97832538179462,4.24337841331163));
#536=CARTESIAN_POINT('',(-4.03635412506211,3.76634491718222,4.1311427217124));
#537=CARTESIAN_POINT('',(-4.06960018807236,3.95764194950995,4.17045802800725));
#538=CARTESIAN_POINT('',(-3.91869647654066,3.95949081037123,4.29874186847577));
#539=CARTESIAN_POINT('',(-4.23809422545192,3.67604370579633,4.36971153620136));
#540=CARTESIAN_POINT('',(-4.2813441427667,3.86236755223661,4.42085695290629));
#541=CARTESIAN_POINT('',(-4.13113710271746,3.86455876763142,4.54922175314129));
#542=CARTESIAN_POINT('',(-4.39140984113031,3.58154263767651,4.5510157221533));
#543=CARTESIAN_POINT('',(-4.44238549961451,3.76280721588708,4.6112972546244));
#544=CARTESIAN_POINT('',(-4.29255090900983,3.76521149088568,4.73960990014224));
#545=CARTESIAN_POINT('',(-4.68339279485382,3.34808500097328,4.89630169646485));
#546=CARTESIAN_POINT('',(-4.74894965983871,3.51708017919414,4.97382631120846));
#547=CARTESIAN_POINT('',(-4.59991735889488,3.51978166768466,5.10223239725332));
#548=CARTESIAN_POINT('',(-4.82203449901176,3.20905229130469,5.06025317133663));
#549=CARTESIAN_POINT('',(-4.89453139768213,3.37084513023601,5.14598475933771));
#550=CARTESIAN_POINT('',(-4.74584294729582,3.37361907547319,5.27443497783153));
#551=CARTESIAN_POINT('',(-5.06150732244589,2.91377703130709,5.34344301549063));
#552=CARTESIAN_POINT('',(-5.14592541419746,3.06040023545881,5.44327207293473));
#553=CARTESIAN_POINT('',(-4.99787615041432,3.06320149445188,5.57189612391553));
#554=CARTESIAN_POINT('',(-5.16491623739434,2.76252295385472,5.4657297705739));
#555=CARTESIAN_POINT('',(-5.25448334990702,2.90142969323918,5.57164782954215));
#556=CARTESIAN_POINT('',(-5.10669986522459,2.9041907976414,5.70035383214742));
#557=CARTESIAN_POINT('',(-5.35376793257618,2.43539964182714,5.6890573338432));
#558=CARTESIAN_POINT('',(-5.45269664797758,2.55770739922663,5.80604600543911));
#559=CARTESIAN_POINT('',(-5.30543053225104,2.56029193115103,5.9349602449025));
#560=CARTESIAN_POINT('',(-5.43922842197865,2.25955495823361,5.7901190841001));
#561=CARTESIAN_POINT('',(-5.5424016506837,2.37296486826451,5.9121271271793));
#562=CARTESIAN_POINT('',(-5.3953561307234,2.37542957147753,6.04113093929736));
#563=CARTESIAN_POINT('',(-5.58984939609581,1.88817596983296,5.96823670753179));
#564=CARTESIAN_POINT('',(-5.70047498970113,1.98286555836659,6.09905758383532));
#565=CARTESIAN_POINT('',(-5.55384153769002,1.98500550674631,6.22825761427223));
#566=CARTESIAN_POINT('',(-5.65501442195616,1.69264608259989,6.04529795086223));
#567=CARTESIAN_POINT('',(-5.76887073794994,1.77749117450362,6.17993933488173));
#568=CARTESIAN_POINT('',(-5.62240612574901,1.77944844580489,6.30921923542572));
#569=CARTESIAN_POINT('',(-5.76324427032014,1.28737115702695,6.17328572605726));
#570=CARTESIAN_POINT('',(-5.88244871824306,1.35186913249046,6.31425157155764));
#571=CARTESIAN_POINT('',(-5.73627996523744,1.35339019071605,6.44368699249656));
#572=CARTESIAN_POINT('',(-5.80630086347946,1.07762085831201,6.22420252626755));
#573=CARTESIAN_POINT('',(-5.92763755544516,1.13159005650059,6.36768986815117));
#574=CARTESIAN_POINT('',(-5.78158055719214,1.13288346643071,6.49718290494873));
#575=CARTESIAN_POINT('',(-5.86902371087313,0.649949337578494,6.29837575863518));
#576=CARTESIAN_POINT('',(-5.99345739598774,0.682495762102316,6.44552546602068));
#577=CARTESIAN_POINT('',(-5.8475718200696,0.68328007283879,6.57511375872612));
#578=CARTESIAN_POINT('',(-5.88870770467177,0.432034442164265,6.32165316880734));
#579=CARTESIAN_POINT('',(-6.0141154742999,0.45365927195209,6.46995478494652));
#580=CARTESIAN_POINT('',(-5.86828115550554,0.454190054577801,6.59957074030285));
#581=CARTESIAN_POINT('',(-5.90033286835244,0.103793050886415,6.33540056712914));
#582=CARTESIAN_POINT('',(-6.02631475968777,0.108987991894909,6.48438111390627));
#583=CARTESIAN_POINT('',(-5.88051188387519,0.109115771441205,6.61401477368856));
#584=CARTESIAN_POINT('',(-5.90121821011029,-0.00593407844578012,6.33644753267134));
#585=CARTESIAN_POINT('',(-6.0272437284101,-0.00623159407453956,6.48547967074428));
#586=CARTESIAN_POINT('',(-5.88144334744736,-0.00623839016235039,6.61511478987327));
#587=CARTESIAN_POINT('',(-5.89702063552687,-0.225119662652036,6.331483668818));
#588=CARTESIAN_POINT('',(-6.0228390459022,-0.236385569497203,6.48027089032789));
#589=CARTESIAN_POINT('',(-5.87702711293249,-0.236664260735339,6.60989939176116));
#590=CARTESIAN_POINT('',(-5.89193742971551,-0.334578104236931,6.32547249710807));
#591=CARTESIAN_POINT('',(-6.01750495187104,-0.351323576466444,6.47396302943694));
#592=CARTESIAN_POINT('',(-5.87167911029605,-0.35173595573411,6.60358361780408));
#593=CARTESIAN_POINT('',(-5.88387948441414,-0.443561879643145,6.31594353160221));
#594=CARTESIAN_POINT('',(-6.00904919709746,-0.465759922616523,6.46396363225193));
#595=CARTESIAN_POINT('',(-5.86320139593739,-0.466308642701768,6.59357180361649));
#596=(BOUNDED_SURFACE() B_SPLINE_SURFACE(3,2,((#524,#525,#526),(#527,#528,#529),(#530,#531,
#532),(#533,#534,#535),(#536,#537,#538),(#539,#540,#541),(#542,#543,#544),(#545,#546,#547),
(#548,#549,#550),(#551,#552,#553),(#554,#555,#556),(#557,#558,#559),(#560,#561,#562),(#563,#564,
#565),(#566,#567,#568),(#569,#570,#571),(#572,#573,#574),(#575,#576,#577),(#578,#579,#580),
(#581,#582,#583),(#584,#585,#586),(#587,#588,#589),(#590,#591,#592),(#593,#594,#595)),
.UNSPECIFIED.,.F.,.F.,.F.) B_SPLINE_SURFACE_WITH_KNOTS((4,2,2,2,2,2,2,2,2,2,2,4),(3,3),(0.,
0.213493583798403,0.427461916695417,1.1886913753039,1.95122941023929,2.60900743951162,
3.26613337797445,3.92311217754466,4.58033534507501,5.23705936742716,5.5659290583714,
5.89481469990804),(0.,1.),
.UNSPECIFIED.) GEOMETRIC_REPRESENTATION_ITEM() RATIONAL_B_SPLINE_SURFACE(((1.,0.709498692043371,
1.),(1.,0.709718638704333,1.),(1.,0.709928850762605,1.),(1.,0.710332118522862,1.),(1.,
0.710525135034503,1.),(1.,0.711368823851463,1.),(1.,0.711927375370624,1.),(1.,0.712896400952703,
1.),(1.,0.713306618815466,1.),(1.,0.713964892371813,1.),(1.,0.714227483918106,1.),(1.,
0.714683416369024,1.),(1.,0.714876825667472,1.),(1.,0.71520538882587,1.),(1.,0.71534055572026,
1.),(1.,0.715559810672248,1.),(1.,0.715643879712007,1.),(1.,0.715765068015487,1.),(1.,
0.715802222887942,1.),(1.,0.715824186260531,1.),(1.,0.715825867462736,1.),(1.,0.715817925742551,
1.),(1.,0.715808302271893,1.),(1.,0.715793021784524,1.))) REPRESENTATION_ITEM('') SURFACE());
#597=CARTESIAN_POINT('',(-3.68214916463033,4.03955638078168,4.01991451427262));
#598=CARTESIAN_POINT('',(-3.72985962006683,4.02675507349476,4.07614142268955));
#599=CARTESIAN_POINT('',(-3.77731690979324,4.01195307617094,4.13207741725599));
#600=CARTESIAN_POINT('',(-3.87173600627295,3.97832538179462,4.24337841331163));
#601=CARTESIAN_POINT('',(-3.91869647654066,3.95949081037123,4.29874186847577));
#602=CARTESIAN_POINT('',(-4.13113710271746,3.86455876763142,4.54922175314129));
#603=CARTESIAN_POINT('',(-4.29255090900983,3.76521149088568,4.73960990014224));
#604=CARTESIAN_POINT('',(-4.59991735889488,3.51978166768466,5.10223239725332));
#605=CARTESIAN_POINT('',(-4.74584294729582,3.37361907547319,5.27443497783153));
#606=CARTESIAN_POINT('',(-4.99787615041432,3.06320149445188,5.57189612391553));
#607=CARTESIAN_POINT('',(-5.10669986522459,2.9041907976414,5.70035383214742));
#608=CARTESIAN_POINT('',(-5.30543053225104,2.56029193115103,5.9349602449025));
#609=CARTESIAN_POINT('',(-5.39535613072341,2.37542957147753,6.04113093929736));
#610=CARTESIAN_POINT('',(-5.55384153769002,1.98500550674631,6.22825761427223));
#611=CARTESIAN_POINT('',(-5.62240612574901,1.77944844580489,6.30921923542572));
#612=CARTESIAN_POINT('',(-5.73627996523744,1.35339019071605,6.44368699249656));
#613=CARTESIAN_POINT('',(-5.78158055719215,1.13288346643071,6.49718290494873));
#614=CARTESIAN_POINT('',(-5.8475718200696,0.68328007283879,6.57511375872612));
#615=CARTESIAN_POINT('',(-5.86828115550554,0.454190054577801,6.59957074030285));
#616=CARTESIAN_POINT('',(-5.88051188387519,0.109115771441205,6.61401477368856));
#617=CARTESIAN_POINT('',(-5.88144334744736,-0.00623839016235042,6.61511478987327));
#618=CARTESIAN_POINT('',(-5.87702711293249,-0.23666426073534,6.60989939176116));
#619=CARTESIAN_POINT('',(-5.87167911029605,-0.351735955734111,6.60358361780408));
#620=CARTESIAN_POINT('',(-5.86320139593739,-0.466308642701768,6.59357180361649));
#621=B_SPLINE_CURVE_WITH_KNOTS('',3,(#597,#598,#599,#600,#601,#602,#603,#604,#605,#606,#607,
#608,#609,#610,#611,#612,#613,#614,#615,#616,#617,#618,#619,#620),.UNSPECIFIED.,.F.,.F.,(4,2,2,
2,2,2,2,2,2,2,2,4),(0.,0.213493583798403,0.427461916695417,1.1886913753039,1.95122941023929,
2.60900743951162,3.26613337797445,3.92311217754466,4.58033534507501,5.23705936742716,
5.5659290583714,5.89481469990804),.UNSPECIFIED.);
#622=CARTESIAN_POINT('',(-5.77279407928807,1.15641025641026,6.4868072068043));
#623=VERTEX_POINT('',#622);
#624=EDGE_CURVE('E681',#521,#623,#621,.T.);
#625=ORIENTED_EDGE('',*,*,#624,.T.);
#626=CARTESIAN_POINT('',(0.,1.15641025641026,0.));
#627=DIRECTION('',(0.,-1.,0.));
#628=DIRECTION('',(0.,0.,-1.));
#629=AXIS2_PLACEMENT_3D('',#626,#627,#628);
#630=CIRCLE('',#629,8.68353725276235);
#631=CARTESIAN_POINT('',(-8.632266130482,1.15641025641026,0.942231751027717));
#632=VERTEX_POINT('',#631);
#633=EDGE_CURVE('E682',#623,#632,#630,.T.);
#634=ORIENTED_EDGE('',*,*,#633,.T.);
#635=CARTESIAN_POINT('',(-5.41018277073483,4.03955638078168,0.66922160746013));
#636=CARTESIAN_POINT('',(-5.39339604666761,4.03822999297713,0.867155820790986));
#637=CARTESIAN_POINT('',(-5.3595557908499,3.84250485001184,0.864325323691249));
#638=CARTESIAN_POINT('',(-5.48365677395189,4.02675507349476,0.67549246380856));
#639=CARTESIAN_POINT('',(-5.46681274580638,4.02531549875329,0.873296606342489));
#640=CARTESIAN_POINT('',(-5.4294602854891,3.83032799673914,0.870172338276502));
#641=CARTESIAN_POINT('',(-5.55674696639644,4.01195307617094,0.681725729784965));
#642=CARTESIAN_POINT('',(-5.53986430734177,4.01040447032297,0.879406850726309));
#643=CARTESIAN_POINT('',(-5.49899896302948,3.81624804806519,0.875988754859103));
#644=CARTESIAN_POINT('',(-5.70217484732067,3.97832538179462,0.694119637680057));
#645=CARTESIAN_POINT('',(-5.68520063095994,3.97657141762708,0.891563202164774));
#646=CARTESIAN_POINT('',(-5.63735925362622,3.7842607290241,0.887561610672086));
#647=CARTESIAN_POINT('',(-5.7745105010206,3.95949081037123,0.700280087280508));
#648=CARTESIAN_POINT('',(-5.75748756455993,3.95764194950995,0.897609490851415));
#649=CARTESIAN_POINT('',(-5.70617892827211,3.76634491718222,0.893317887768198));
#650=CARTESIAN_POINT('',(-6.10176476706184,3.86455876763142,0.728133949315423));
#651=CARTESIAN_POINT('',(-6.08427192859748,3.86236755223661,0.924942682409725));
#652=CARTESIAN_POINT('',(-6.01752434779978,3.67604370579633,0.919359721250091));
#653=CARTESIAN_POINT('',(-6.35047328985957,3.76521149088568,0.749255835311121));
#654=CARTESIAN_POINT('',(-6.33280699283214,3.76280721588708,0.945730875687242));
#655=CARTESIAN_POINT('',(-6.25413627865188,3.58154263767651,0.939150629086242));
#656=CARTESIAN_POINT('',(-6.82413495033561,3.51978166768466,0.789428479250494));
#657=CARTESIAN_POINT('',(-6.80592734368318,3.51708017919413,0.985304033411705));
#658=CARTESIAN_POINT('',(-6.70475345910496,3.34808500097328,0.976841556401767));
#659=CARTESIAN_POINT('',(-7.04904651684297,3.37361907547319,0.808475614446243));
#660=CARTESIAN_POINT('',(-7.03060358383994,3.37084513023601,1.00409660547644));
#661=CARTESIAN_POINT('',(-6.91871914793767,3.20905229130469,0.994738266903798));
#662=CARTESIAN_POINT('',(-7.43753504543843,3.06320149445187,0.841347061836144));
#663=CARTESIAN_POINT('',(-7.41857987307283,3.0604002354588,1.03654806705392));
#664=CARTESIAN_POINT('',(-7.28829746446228,2.91377703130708,1.0256508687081));
#665=CARTESIAN_POINT('',(-7.60529333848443,2.90419079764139,0.855529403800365));
#666=CARTESIAN_POINT('',(-7.58611729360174,2.90142969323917,1.05056138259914));
#667=CARTESIAN_POINT('',(-7.44788840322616,2.76252295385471,1.03899951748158));
#668=CARTESIAN_POINT('',(-7.91166548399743,2.56029193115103,0.88141676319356));
#669=CARTESIAN_POINT('',(-7.89201980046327,2.55770739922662,1.07614795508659));
#670=CARTESIAN_POINT('',(-7.7393431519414,2.43539964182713,1.06337763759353));
#671=CARTESIAN_POINT('',(-8.05030806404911,2.37542957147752,0.893124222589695));
#672=CARTESIAN_POINT('',(-8.03046149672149,2.37296486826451,1.0877276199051));
#673=CARTESIAN_POINT('',(-7.87123429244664,2.25955495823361,1.07440939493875));
#674=CARTESIAN_POINT('',(-8.29466137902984,1.9850055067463,0.913751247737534));
#675=CARTESIAN_POINT('',(-8.27441602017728,1.98286555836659,1.10813268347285));
#676=CARTESIAN_POINT('',(-8.10368758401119,1.88817596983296,1.09385246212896));
#677=CARTESIAN_POINT('',(-8.40037948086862,1.77944844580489,0.922671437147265));
#678=CARTESIAN_POINT('',(-8.37997115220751,1.77749117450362,1.11696162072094));
#679=CARTESIAN_POINT('',(-8.20425674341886,1.69264608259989,1.10226435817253));
#680=CARTESIAN_POINT('',(-8.57596258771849,1.35339019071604,0.9374836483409));
#681=CARTESIAN_POINT('',(-8.55525600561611,1.35186913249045,1.13162295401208));
#682=CARTESIAN_POINT('',(-8.3712878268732,1.28737115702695,1.11623532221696));
#683=CARTESIAN_POINT('',(-8.64581424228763,1.13288346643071,0.943374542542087));
#684=CARTESIAN_POINT('',(-8.624995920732,1.13159005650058,1.13745620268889));
#685=CARTESIAN_POINT('',(-8.43773705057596,1.077620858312,1.12179332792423));
#686=CARTESIAN_POINT('',(-8.74757097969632,0.683280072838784,0.951955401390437));
#687=CARTESIAN_POINT('',(-8.72657565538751,0.682495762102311,1.14595262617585));
#688=CARTESIAN_POINT('',(-8.53453719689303,0.649949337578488,1.12988997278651));
#689=CARTESIAN_POINT('',(-8.77950484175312,0.454190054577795,0.95464779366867));
#690=CARTESIAN_POINT('',(-8.75845725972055,0.453659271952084,1.14861929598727));
#691=CARTESIAN_POINT('',(-8.56491549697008,0.43203444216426,1.13243090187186));
#692=CARTESIAN_POINT('',(-8.79836464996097,0.1091157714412,0.956237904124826));
#693=CARTESIAN_POINT('',(-8.77728441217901,0.108987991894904,1.15019405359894));
#694=CARTESIAN_POINT('',(-8.5828566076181,0.103793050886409,1.13393154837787));
#695=CARTESIAN_POINT('',(-8.79980096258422,-0.0062383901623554,0.956359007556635));
#696=CARTESIAN_POINT('',(-8.77871808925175,-0.0062315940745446,1.15031397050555));
#697=CARTESIAN_POINT('',(-8.58422295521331,-0.00593407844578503,1.13404583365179));
#698=CARTESIAN_POINT('',(-8.79299112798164,-0.236664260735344,0.955784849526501));
#699=CARTESIAN_POINT('',(-8.7719203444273,-0.236385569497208,1.14974538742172));
#700=CARTESIAN_POINT('',(-8.57774483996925,-0.22511966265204,1.13350398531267));
#701=CARTESIAN_POINT('',(-8.78474451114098,-0.351735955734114,0.955089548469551));
#702=CARTESIAN_POINT('',(-8.76368823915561,-0.351323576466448,1.14905683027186));
#703=CARTESIAN_POINT('',(-8.5698999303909,-0.334578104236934,1.13284781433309));
#704=CARTESIAN_POINT('',(-8.77167189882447,-0.466308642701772,0.953987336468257));
#705=CARTESIAN_POINT('',(-8.75063847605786,-0.465759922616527,1.14796531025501));
#706=CARTESIAN_POINT('',(-8.55746410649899,-0.443561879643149,1.13180764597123));
#707=(BOUNDED_SURFACE() B_SPLINE_SURFACE(3,2,((#635,#636,#637),(#638,#639,#640),(#641,#642,
#643),(#644,#645,#646),(#647,#648,#649),(#650,#651,#652),(#653,#654,#655),(#656,#657,#658),
(#659,#660,#661),(#662,#663,#664),(#665,#666,#667),(#668,#669,#670),(#671,#672,#673),(#674,#675,
#676),(#677,#678,#679),(#680,#681,#682),(#683,#684,#685),(#686,#687,#688),(#689,#690,#691),
(#692,#693,#694),(#695,#696,#697),(#698,#699,#700),(#701,#702,#703),(#704,#705,#706)),
.UNSPECIFIED.,.F.,.F.,.F.) B_SPLINE_SURFACE_WITH_KNOTS((4,2,2,2,2,2,2,2,2,2,2,4),(3,3),(0.,
0.213493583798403,0.427461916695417,1.1886913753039,1.95122941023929,2.60900743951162,
3.26613337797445,3.92311217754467,4.58033534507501,5.23705936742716,5.5659290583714,
5.89481469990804),(0.,1.),
.UNSPECIFIED.) GEOMETRIC_REPRESENTATION_ITEM() RATIONAL_B_SPLINE_SURFACE(((1.,0.709498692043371,
1.),(1.,0.709718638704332,1.),(1.,0.709928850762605,1.),(1.,0.710332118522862,1.),(1.,
0.710525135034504,1.),(1.,0.711368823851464,1.),(1.,0.711927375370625,1.),(1.,0.712896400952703,
1.),(1.,0.713306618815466,1.),(1.,0.713964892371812,1.),(1.,0.714227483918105,1.),(1.,
0.714683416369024,1.),(1.,0.714876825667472,1.),(1.,0.71520538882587,1.),(1.,0.71534055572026,
1.),(1.,0.715559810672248,1.),(1.,0.715643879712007,1.),(1.,0.715765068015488,1.),(1.,
0.715802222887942,1.),(1.,0.715824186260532,1.),(1.,0.715825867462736,1.),(1.,0.715817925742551,
1.),(1.,0.715808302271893,1.),(1.,0.715793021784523,1.))) REPRESENTATION_ITEM('') SURFACE());
#708=CARTESIAN_POINT('',(-8.77167189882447,-0.466308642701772,0.953987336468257));
#709=CARTESIAN_POINT('',(-8.78474451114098,-0.351735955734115,0.955089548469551));
#710=CARTESIAN_POINT('',(-8.79299112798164,-0.236664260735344,0.955784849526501));
#711=CARTESIAN_POINT('',(-8.79980096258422,-0.0062383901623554,0.956359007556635));
#712=CARTESIAN_POINT('',(-8.79836464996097,0.1091157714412,0.956237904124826));
#713=CARTESIAN_POINT('',(-8.77950484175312,0.454190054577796,0.95464779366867));
#714=CARTESIAN_POINT('',(-8.74757097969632,0.683280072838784,0.951955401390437));
#715=CARTESIAN_POINT('',(-8.64581424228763,1.13288346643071,0.943374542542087));
#716=CARTESIAN_POINT('',(-8.57596258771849,1.35339019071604,0.9374836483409));
#717=CARTESIAN_POINT('',(-8.40037948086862,1.77944844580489,0.922671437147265));
#718=CARTESIAN_POINT('',(-8.29466137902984,1.9850055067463,0.913751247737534));
#719=CARTESIAN_POINT('',(-8.05030806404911,2.37542957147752,0.893124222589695));
#720=CARTESIAN_POINT('',(-7.91166548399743,2.56029193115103,0.88141676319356));
#721=CARTESIAN_POINT('',(-7.60529333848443,2.9041907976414,0.855529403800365));
#722=CARTESIAN_POINT('',(-7.43753504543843,3.06320149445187,0.841347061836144));
#723=CARTESIAN_POINT('',(-7.04904651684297,3.37361907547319,0.808475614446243));
#724=CARTESIAN_POINT('',(-6.82413495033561,3.51978166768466,0.789428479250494));
#725=CARTESIAN_POINT('',(-6.35047328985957,3.76521149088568,0.749255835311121));
#726=CARTESIAN_POINT('',(-6.10176476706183,3.86455876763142,0.728133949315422));
#727=CARTESIAN_POINT('',(-5.7745105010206,3.95949081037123,0.700280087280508));
#728=CARTESIAN_POINT('',(-5.70217484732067,3.97832538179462,0.694119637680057));
#729=CARTESIAN_POINT('',(-5.55674696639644,4.01195307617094,0.681725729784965));
#730=CARTESIAN_POINT('',(-5.48365677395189,4.02675507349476,0.67549246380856));
#731=CARTESIAN_POINT('',(-5.41018277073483,4.03955638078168,0.66922160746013));
#732=B_SPLINE_CURVE_WITH_KNOTS('',3,(#708,#709,#710,#711,#712,#713,#714,#715,#716,#717,#718,
#719,#720,#721,#722,#723,#724,#725,#726,#727,#728,#729,#730,#731),.UNSPECIFIED.,.F.,.F.,(4,2,2,
2,2,2,2,2,2,2,2,4),(0.,0.328885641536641,0.657755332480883,1.31447935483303,1.97170252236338,
2.62868132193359,3.28580726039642,3.94358528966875,4.70612332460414,5.46735278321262,
5.68132111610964,5.89481469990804),.UNSPECIFIED.);
#733=CARTESIAN_POINT('',(-5.84631342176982,3.93866175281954,0.706391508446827));
#734=VERTEX_POINT('',#733);
#735=EDGE_CURVE('E688',#632,#734,#732,.T.);
#736=ORIENTED_EDGE('',*,*,#735,.T.);
#737=CARTESIAN_POINT('',(-6.40401169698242,3.46378065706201,1.05739849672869));
#738=CARTESIAN_POINT('',(-6.49673700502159,3.66678636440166,1.0976400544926));
#739=CARTESIAN_POINT('',(-6.57472153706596,3.64141043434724,0.886208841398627));
#740=CARTESIAN_POINT('',(-6.3560635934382,3.49240748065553,1.03659411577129));
#741=CARTESIAN_POINT('',(-6.44650658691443,3.69353804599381,1.07298350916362));
#742=CARTESIAN_POINT('',(-6.51919612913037,3.67150530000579,0.862726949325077));
#743=CARTESIAN_POINT('',(-6.30685295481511,3.51990870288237,1.01746979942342));
#744=CARTESIAN_POINT('',(-6.39439730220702,3.71957636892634,1.05001072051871));
#745=CARTESIAN_POINT('',(-6.4622207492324,3.70041684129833,0.841129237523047));
#746=CARTESIAN_POINT('',(-6.20605117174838,3.57246736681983,0.982901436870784));
#747=CARTESIAN_POINT('',(-6.28762620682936,3.76941716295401,1.0083816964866));
#748=CARTESIAN_POINT('',(-6.34553773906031,3.75567082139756,0.802049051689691));
#749=CARTESIAN_POINT('',(-6.15445763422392,3.59752226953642,0.967461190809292));
#750=CARTESIAN_POINT('',(-6.23289700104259,3.79329590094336,0.989629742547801));
#751=CARTESIAN_POINT('',(-6.28582736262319,3.7820105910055,0.784570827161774));
#752=CARTESIAN_POINT('',(-5.99635116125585,3.66869729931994,0.927176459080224));
#753=CARTESIAN_POINT('',(-6.06614660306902,3.86085119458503,0.940691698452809));
#754=CARTESIAN_POINT('',(-6.10288199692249,3.85683562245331,0.738869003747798));
#755=CARTESIAN_POINT('',(-5.88662344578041,3.71076093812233,0.908417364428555));
#756=CARTESIAN_POINT('',(-5.949148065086,3.90164097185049,0.916774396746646));
#757=CARTESIAN_POINT('',(-5.97596140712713,3.90105637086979,0.717433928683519));
#758=CARTESIAN_POINT('',(-5.67729301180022,3.7775388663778,0.890896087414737));
#759=CARTESIAN_POINT('',(-5.72672706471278,3.96671463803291,0.892356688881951));
#760=CARTESIAN_POINT('',(-5.73393209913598,3.97125880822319,0.696819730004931));
#761=CARTESIAN_POINT('',(-5.57828809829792,3.80381766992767,0.889803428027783));
#762=CARTESIAN_POINT('',(-5.62125863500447,3.99277799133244,0.888870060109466));
#763=CARTESIAN_POINT('',(-5.61950147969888,3.99888524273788,0.695056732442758));
#764=CARTESIAN_POINT('',(-5.37974187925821,3.84650700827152,0.902640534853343));
#765=CARTESIAN_POINT('',(-5.41095334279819,4.03575162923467,0.89879642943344));
#766=CARTESIAN_POINT('',(-5.39013294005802,4.04376377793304,0.708076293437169));
#767=CARTESIAN_POINT('',(-5.28020310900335,3.86294721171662,0.91652477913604));
#768=CARTESIAN_POINT('',(-5.30528768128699,4.05290173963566,0.912116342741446));
#769=CARTESIAN_POINT('',(-5.27519760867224,4.06104706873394,0.722808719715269));
#770=CARTESIAN_POINT('',(-5.10754191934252,3.88375748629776,0.954144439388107));
#771=CARTESIAN_POINT('',(-5.12344938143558,4.07575932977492,0.949874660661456));
#772=CARTESIAN_POINT('',(-5.07598768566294,4.08292453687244,0.763149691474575));
#773=CARTESIAN_POINT('',(-5.03388842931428,3.89009175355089,0.974658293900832));
#774=CARTESIAN_POINT('',(-5.04590577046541,4.08328318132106,0.970933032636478));
#775=CARTESIAN_POINT('',(-4.9910613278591,4.08958363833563,0.78523684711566));
#776=CARTESIAN_POINT('',(-4.88914178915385,3.89821796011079,1.02407608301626));
#777=CARTESIAN_POINT('',(-4.89441479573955,4.09437987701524,1.02189495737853));
#778=CARTESIAN_POINT('',(-4.82431244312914,4.09812657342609,0.838529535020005));
#779=CARTESIAN_POINT('',(-4.81805246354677,3.90000337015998,1.05299201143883));
#780=CARTESIAN_POINT('',(-4.82019034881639,4.09794316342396,1.05197312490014));
#781=CARTESIAN_POINT('',(-4.74249454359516,4.10000354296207,0.869748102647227));
#782=CARTESIAN_POINT('',(-4.64781756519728,3.89999508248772,1.1339655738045));
#783=CARTESIAN_POINT('',(-4.64336414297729,4.10303964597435,1.13608681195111));
#784=CARTESIAN_POINT('',(-4.54683675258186,4.09999483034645,0.957185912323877));
#785=CARTESIAN_POINT('',(-4.55077630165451,3.89618172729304,1.19055276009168));
#786=CARTESIAN_POINT('',(-4.54351538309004,4.10280448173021,1.19501535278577));
#787=CARTESIAN_POINT('',(-4.43554198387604,4.09598591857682,1.01830281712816));
#788=CARTESIAN_POINT('',(-4.41353715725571,3.88780251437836,1.28679604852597));
#789=CARTESIAN_POINT('',(-4.40470099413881,4.10033603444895,1.2933139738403));
#790=CARTESIAN_POINT('',(-4.27868441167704,4.08717700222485,1.12224623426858));
#791=CARTESIAN_POINT('',(-4.36915707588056,3.88456387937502,1.3207914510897));
#792=CARTESIAN_POINT('',(-4.35990117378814,4.09914188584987,1.32807726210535));
#793=CARTESIAN_POINT('',(-4.22805571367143,4.08377228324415,1.15896091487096));
#794=CARTESIAN_POINT('',(-4.28343474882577,3.87775486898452,1.39234050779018));
#795=CARTESIAN_POINT('',(-4.27381832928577,4.09642693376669,1.40080962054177));
#796=CARTESIAN_POINT('',(-4.13048678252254,4.07661409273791,1.23625194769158));
#797=CARTESIAN_POINT('',(-4.24209056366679,3.87418470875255,1.42989185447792));
#798=CARTESIAN_POINT('',(-4.23258225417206,4.09490332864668,1.43879947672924));
#799=CARTESIAN_POINT('',(-4.08354419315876,4.07286084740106,1.27682579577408));
#800=CARTESIAN_POINT('',(-4.20235650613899,3.87072392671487,1.46913027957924));
#801=CARTESIAN_POINT('',(-4.19341211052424,4.09343373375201,1.47796460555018));
#802=CARTESIAN_POINT('',(-4.03856269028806,4.06922258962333,1.31924099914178));
#803=(BOUNDED_SURFACE() B_SPLINE_SURFACE(3,2,((#737,#738,#739),(#740,#741,#742),(#743,#744,
#745),(#746,#747,#748),(#749,#750,#751),(#752,#753,#754),(#755,#756,#757),(#758,#759,#760),
(#761,#762,#763),(#764,#765,#766),(#767,#768,#769),(#770,#771,#772),(#773,#774,#775),(#776,#777,
#778),(#779,#780,#781),(#782,#783,#784),(#785,#786,#787),(#788,#789,#790),(#791,#792,#793),
(#794,#795,#796),(#797,#798,#799),(#800,#801,#802)),.UNSPECIFIED.,.F.,.F.,
.F.) B_SPLINE_SURFACE_WITH_KNOTS((4,2,2,2,2,2,2,2,2,2,4),(3,3),(0.,0.192575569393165,
0.385348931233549,0.771338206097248,1.10592100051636,1.43948969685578,1.69184298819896,
1.94455829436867,2.3133035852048,2.49786750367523,2.68231246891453),(0.,1.),
.UNSPECIFIED.) GEOMETRIC_REPRESENTATION_ITEM() RATIONAL_B_SPLINE_SURFACE(((1.,0.661437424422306,
1.),(1.,0.666863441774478,1.),(1.,0.672007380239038,1.),(1.,0.6816635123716,1.),(1.,
0.686175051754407,1.),(1.,0.698653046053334,1.),(1.,0.70555007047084,1.),(1.,0.715183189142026,
1.),(1.,0.71835110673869,1.),(1.,0.721821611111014,1.),(1.,0.722132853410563,1.),(1.,
0.720203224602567,1.),(1.,0.718565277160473,1.),(1.,0.713846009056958,1.),(1.,0.710762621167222,
1.),(1.,0.701772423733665,1.),(1.,0.695219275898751,1.),(1.,0.684835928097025,1.),(1.,
0.681280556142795,1.),(1.,0.674274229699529,1.),(1.,0.670823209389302,1.),(1.,0.667565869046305,1.))) REPRESENTATION_ITEM('') SURFACE());
#804=CARTESIAN_POINT('',(-6.57472153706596,3.64141043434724,0.886208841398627));
#805=CARTESIAN_POINT('',(-6.51919612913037,3.67150530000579,0.862726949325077));
#806=CARTESIAN_POINT('',(-6.4622207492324,3.70041684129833,0.841129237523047));
#807=CARTESIAN_POINT('',(-6.34553773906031,3.75567082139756,0.802049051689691));
#808=CARTESIAN_POINT('',(-6.28582736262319,3.7820105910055,0.784570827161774));
#809=CARTESIAN_POINT('',(-6.10288199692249,3.85683562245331,0.738869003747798));
#810=CARTESIAN_POINT('',(-5.97596140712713,3.90105637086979,0.717433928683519));
#811=CARTESIAN_POINT('',(-5.73393209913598,3.97125880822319,0.696819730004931));
#812=CARTESIAN_POINT('',(-5.61950147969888,3.99888524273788,0.695056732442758));
#813=CARTESIAN_POINT('',(-5.39013294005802,4.04376377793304,0.708076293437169));
#814=CARTESIAN_POINT('',(-5.27519760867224,4.06104706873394,0.722808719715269));
#815=CARTESIAN_POINT('',(-5.07598768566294,4.08292453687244,0.763149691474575));
#816=CARTESIAN_POINT('',(-4.9910613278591,4.08958363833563,0.78523684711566));
#817=CARTESIAN_POINT('',(-4.82431244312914,4.09812657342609,0.838529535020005));
#818=CARTESIAN_POINT('',(-4.74249454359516,4.10000354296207,0.869748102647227));
#819=CARTESIAN_POINT('',(-4.54683675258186,4.09999483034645,0.957185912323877));
#820=CARTESIAN_POINT('',(-4.43554198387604,4.09598591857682,1.01830281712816));
#821=CARTESIAN_POINT('',(-4.27868441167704,4.08717700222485,1.12224623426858));
#822=CARTESIAN_POINT('',(-4.22805571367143,4.08377228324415,1.15896091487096));
#823=CARTESIAN_POINT('',(-4.13048678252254,4.07661409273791,1.23625194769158));
#824=CARTESIAN_POINT('',(-4.08354419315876,4.07286084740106,1.27682579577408));
#825=CARTESIAN_POINT('',(-4.03856269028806,4.06922258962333,1.31924099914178));
#826=B_SPLINE_CURVE_WITH_KNOTS('',3,(#804,#805,#806,#807,#808,#809,#810,#811,#812,#813,#814,
#815,#816,#817,#818,#819,#820,#821,#822,#823,#824,#825),.UNSPECIFIED.,.F.,.F.,(4,2,2,2,2,2,2,2,
2,2,4),(0.,0.192575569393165,0.385348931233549,0.771338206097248,1.10592100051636,
1.43948969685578,1.69184298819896,1.94455829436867,2.3133035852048,2.49786750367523,
2.68231246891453),.UNSPECIFIED.);
#827=CARTESIAN_POINT('',(-4.66293082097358,4.1,0.905304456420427));
#828=VERTEX_POINT('',#827);
#829=EDGE_CURVE('E687',#734,#828,#826,.T.);
#830=ORIENTED_EDGE('',*,*,#829,.T.);
#831=CARTESIAN_POINT('',(0.,4.1,-4.75));
#832=VERTEX_POINT('',#831);
#833=EDGE_CURVE('E983',#832,#828,#423,.T.);
#834=ORIENTED_EDGE('',*,*,#833,.F.);
#835=CARTESIAN_POINT('',(0.,0.,-4.75));
#836=DIRECTION('',(1.,0.,0.));
#837=DIRECTION('',(0.,0.,-1.));
#838=AXIS2_PLACEMENT_3D('',#835,#836,#837);
#839=CIRCLE('',#838,4.1);
#840=CARTESIAN_POINT('',(0.,0.,-8.85));
#841=VERTEX_POINT('',#840);
#842=EDGE_CURVE('E995',#841,#832,#839,.T.);
#843=ORIENTED_EDGE('',*,*,#842,.F.);
#844=CARTESIAN_POINT('',(0.,0.,0.));
#845=DIRECTION('',(0.,1.,0.));
#846=DIRECTION('',(0.,0.,1.));
#847=AXIS2_PLACEMENT_3D('',#844,#845,#846);
#848=CIRCLE('',#847,8.85);
#849=CARTESIAN_POINT('',(0.,0.,8.85));
#850=VERTEX_POINT('',#849);
#851=EDGE_CURVE('E967',#841,#850,#848,.T.);
#852=ORIENTED_EDGE('',*,*,#851,.T.);
#853=CARTESIAN_POINT('',(0.,0.,4.75));
#854=DIRECTION('',(-1.,0.,0.));
#855=DIRECTION('',(0.,0.,1.));
#856=AXIS2_PLACEMENT_3D('',#853,#854,#855);
#857=CIRCLE('',#856,4.1);
#858=EDGE_CURVE('E972',#850,#427,#857,.T.);
#859=ORIENTED_EDGE('',*,*,#858,.T.);
#860=EDGE_LOOP('',(#429,#523,#625,#634,#736,#830,#834,#843,#852,#859));
#861=FACE_BOUND('',#860,.T.);
#862=ADVANCED_FACE('F510',(#861),#418,.T.);
#863=CARTESIAN_POINT('',(33.45,4.1,-8.85));
#864=DIRECTION('',(1.,0.,0.));
#865=DIRECTION('',(0.,0.,-1.));
#866=AXIS2_PLACEMENT_3D('',#863,#864,#865);
#867=PLANE('',#866);
#868=DIRECTION('',(0.,-1.,0.));
#869=VECTOR('',#868,1.);
#870=CARTESIAN_POINT('',(33.45,0.,6.05));
#871=LINE('',#870,#869);
#872=CARTESIAN_POINT('',(33.45,2.3,6.05));
#873=VERTEX_POINT('',#872);
#874=CARTESIAN_POINT('',(33.45,0.,6.05));
#875=VERTEX_POINT('',#874);
#876=EDGE_CURVE('E1213',#873,#875,#871,.T.);
#877=ORIENTED_EDGE('',*,*,#876,.F.);
#878=DIRECTION('',(0.,0.,1.));
#879=VECTOR('',#878,1.);
#880=CARTESIAN_POINT('',(33.45,2.3,6.05));
#881=LINE('',#880,#879);
#882=CARTESIAN_POINT('',(33.45,2.3,-6.05));
#883=VERTEX_POINT('',#882);
#884=EDGE_CURVE('E860',#883,#873,#881,.T.);
#885=ORIENTED_EDGE('',*,*,#884,.F.);
#886=DIRECTION('',(0.,1.,0.));
#887=VECTOR('',#886,1.);
#888=CARTESIAN_POINT('',(33.45,0.,-6.05));
#889=LINE('',#888,#887);
#890=CARTESIAN_POINT('',(33.45,0.,-6.05));
#891=VERTEX_POINT('',#890);
#892=EDGE_CURVE('E1210',#891,#883,#889,.T.);
#893=ORIENTED_EDGE('',*,*,#892,.F.);
#894=DIRECTION('',(0.,0.,1.));
#895=VECTOR('',#894,1.);
#896=CARTESIAN_POINT('',(33.45,0.,-8.85));
#897=LINE('',#896,#895);
#898=CARTESIAN_POINT('',(33.45,0.,-8.05));
#899=VERTEX_POINT('',#898);
#900=EDGE_CURVE('E851',#899,#891,#897,.T.);
#901=ORIENTED_EDGE('',*,*,#900,.F.);
#902=CARTESIAN_POINT('',(33.45,0.,-4.75));
#903=DIRECTION('',(1.,0.,0.));
#904=DIRECTION('',(0.,0.,-1.));
#905=AXIS2_PLACEMENT_3D('',#902,#903,#904);
#906=CIRCLE('',#905,3.3);
#907=CARTESIAN_POINT('',(33.45,3.3,-4.75));
#908=VERTEX_POINT('',#907);
#909=EDGE_CURVE('E936',#899,#908,#906,.T.);
#910=ORIENTED_EDGE('',*,*,#909,.T.);
#911=DIRECTION('',(0.,0.,1.));
#912=VECTOR('',#911,1.);
#913=CARTESIAN_POINT('',(33.45,3.3,-4.75));
#914=LINE('',#913,#912);
#915=CARTESIAN_POINT('',(33.45,3.3,4.75));
#916=VERTEX_POINT('',#915);
#917=EDGE_CURVE('E924',#908,#916,#914,.T.);
#918=ORIENTED_EDGE('',*,*,#917,.T.);
#919=CARTESIAN_POINT('',(33.45,0.,4.75));
#920=DIRECTION('',(1.,0.,0.));
#921=DIRECTION('',(0.,0.,-1.));
#922=AXIS2_PLACEMENT_3D('',#919,#920,#921);
#923=CIRCLE('',#922,3.3);
#924=CARTESIAN_POINT('',(33.45,0.,8.05));
#925=VERTEX_POINT('',#924);
#926=EDGE_CURVE('E918',#916,#925,#923,.T.);
#927=ORIENTED_EDGE('',*,*,#926,.T.);
#928=EDGE_CURVE('E975',#875,#925,#897,.T.);
#929=ORIENTED_EDGE('',*,*,#928,.F.);
#930=EDGE_LOOP('',(#877,#885,#893,#901,#910,#918,#927,#929));
#931=FACE_BOUND('',#930,.T.);
#932=ADVANCED_FACE('F1321',(#931),#867,.T.);
#933=CARTESIAN_POINT('',(0.,4.1,0.));
#934=DIRECTION('',(0.,1.,0.));
#935=DIRECTION('',(0.,0.,1.));
#936=AXIS2_PLACEMENT_3D('',#933,#934,#935);
#937=PLANE('',#936);
#938=ORIENTED_EDGE('',*,*,#833,.T.);
#939=CARTESIAN_POINT('',(-5.60778761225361,4.1,2.89207209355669));
#940=DIRECTION('',(0.,1.,0.));
#941=DIRECTION('',(0.,0.,1.));
#942=AXIS2_PLACEMENT_3D('',#939,#940,#941);
#943=CIRCLE('',#942,2.2);
#944=EDGE_CURVE('E598',#828,#425,#943,.F.);
#945=ORIENTED_EDGE('',*,*,#944,.T.);
#946=ORIENTED_EDGE('',*,*,#428,.T.);
#947=DIRECTION('',(-1.,0.,0.));
#948=VECTOR('',#947,1.);
#949=CARTESIAN_POINT('',(0.,4.1,4.75));
#950=LINE('',#949,#948);
#951=CARTESIAN_POINT('',(30.95,4.1,4.75));
#952=VERTEX_POINT('',#951);
#953=EDGE_CURVE('E987',#427,#952,#950,.F.);
#954=ORIENTED_EDGE('',*,*,#953,.T.);
#955=DIRECTION('',(0.,0.,-1.));
#956=VECTOR('',#955,1.);
#957=CARTESIAN_POINT('',(30.95,4.1,0.));
#958=LINE('',#957,#956);
#959=CARTESIAN_POINT('',(30.95,4.1,-4.75));
#960=VERTEX_POINT('',#959);
#961=EDGE_CURVE('E958',#952,#960,#958,.T.);
#962=ORIENTED_EDGE('',*,*,#961,.T.);
#963=DIRECTION('',(1.,0.,0.));
#964=VECTOR('',#963,1.);
#965=CARTESIAN_POINT('',(0.,4.1,-4.75));
#966=LINE('',#965,#964);
#967=EDGE_CURVE('E991',#960,#832,#966,.F.);
#968=ORIENTED_EDGE('',*,*,#967,.T.);
#969=EDGE_LOOP('',(#938,#945,#946,#954,#962,#968));
#970=FACE_BOUND('',#969,.T.);
#971=ADVANCED_FACE('F748',(#970),#937,.T.);
#972=CARTESIAN_POINT('',(0.,0.,0.));
#973=DIRECTION('',(0.,1.,0.));
#974=DIRECTION('',(0.,0.,1.));
#975=AXIS2_PLACEMENT_3D('',#972,#973,#974);
#976=PLANE('',#975);
#977=CARTESIAN_POINT('',(-4.67289265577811,0.,6.37417107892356));
#978=DIRECTION('',(0.,1.,0.));
#979=DIRECTION('',(0.,0.,1.));
#980=AXIS2_PLACEMENT_3D('',#977,#978,#979);
#981=CIRCLE('',#980,0.500000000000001);
#982=CARTESIAN_POINT('',(-4.67289265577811,0.,6.87417107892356));
#983=VERTEX_POINT('',#982);
#984=EDGE_CURVE('E1358',#983,#983,#981,.F.);
#985=ORIENTED_EDGE('',*,*,#984,.F.);
#986=EDGE_LOOP('',(#985));
#987=FACE_BOUND('',#986,.T.);
#988=CARTESIAN_POINT('',(29.05,0.,-7.75));
#989=DIRECTION('',(0.,1.,0.));
#990=DIRECTION('',(0.,0.,1.));
#991=AXIS2_PLACEMENT_3D('',#988,#989,#990);
#992=CIRCLE('',#991,0.499999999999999);
#993=CARTESIAN_POINT('',(29.05,0.,-7.25));
#994=VERTEX_POINT('',#993);
#995=EDGE_CURVE('E1354',#994,#994,#992,.F.);
#996=ORIENTED_EDGE('',*,*,#995,.F.);
#997=EDGE_LOOP('',(#996));
#998=FACE_BOUND('',#997,.T.);
#999=CARTESIAN_POINT('',(29.05,0.,7.75));
#1000=DIRECTION('',(0.,1.,0.));
#1001=DIRECTION('',(0.,0.,1.));
#1002=AXIS2_PLACEMENT_3D('',#999,#1000,#1001);
#1003=CIRCLE('',#1002,0.499999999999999);
#1004=CARTESIAN_POINT('',(29.05,0.,8.25));
#1005=VERTEX_POINT('',#1004);
#1006=EDGE_CURVE('E1350',#1005,#1005,#1003,.F.);
#1007=ORIENTED_EDGE('',*,*,#1006,.F.);
#1008=EDGE_LOOP('',(#1007));
#1009=FACE_BOUND('',#1008,.T.);
#1010=CARTESIAN_POINT('',(-7.90275733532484,0.,0.111396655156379));
#1011=DIRECTION('',(0.,1.,0.));
#1012=DIRECTION('',(0.,0.,1.));
#1013=AXIS2_PLACEMENT_3D('',#1010,#1011,#1012);
#1014=CIRCLE('',#1013,0.500000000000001);
#1015=CARTESIAN_POINT('',(-7.90275733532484,0.,0.61139665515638));
#1016=VERTEX_POINT('',#1015);
#1017=EDGE_CURVE('E1161',#1016,#1016,#1014,.F.);
#1018=ORIENTED_EDGE('',*,*,#1017,.F.);
#1019=EDGE_LOOP('',(#1018));
#1020=FACE_BOUND('',#1019,.T.);
#1021=CARTESIAN_POINT('',(0.,0.,0.));
#1022=DIRECTION('',(0.,-1.,0.));
#1023=DIRECTION('',(0.,0.,-1.));
#1024=AXIS2_PLACEMENT_3D('',#1021,#1022,#1023);
#1025=CIRCLE('',#1024,8.15);
#1026=CARTESIAN_POINT('',(-8.10362202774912,0.,-0.868222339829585));
#1027=VERTEX_POINT('',#1026);
#1028=CARTESIAN_POINT('',(0.,0.,-8.15));
#1029=VERTEX_POINT('',#1028);
#1030=EDGE_CURVE('E1053',#1027,#1029,#1025,.T.);
#1031=ORIENTED_EDGE('',*,*,#1030,.F.);
#1032=CARTESIAN_POINT('',(-7.90275733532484,0.,0.111396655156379));
#1033=DIRECTION('',(0.,-1.,0.));
#1034=DIRECTION('',(0.,0.,-1.));
#1035=AXIS2_PLACEMENT_3D('',#1032,#1033,#1034);
#1036=CIRCLE('',#1035,1.);
#1037=CARTESIAN_POINT('',(-6.92720998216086,0.,-0.108392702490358));
#1038=VERTEX_POINT('',#1037);
#1039=EDGE_CURVE('E1158',#1027,#1038,#1036,.T.);
#1040=ORIENTED_EDGE('',*,*,#1039,.T.);
#1041=DIRECTION('',(-0.9965201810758,0.,0.0833518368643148));
#1042=VECTOR('',#1041,1.);
#1043=CARTESIAN_POINT('',(-5.86617830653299,0.,-0.197140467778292));
#1044=LINE('',#1043,#1042);
#1045=CARTESIAN_POINT('',(-5.86617830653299,0.,-0.197140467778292));
#1046=VERTEX_POINT('',#1045);
#1047=EDGE_CURVE('E1058',#1046,#1038,#1044,.T.);
#1048=ORIENTED_EDGE('',*,*,#1047,.F.);
#1049=CARTESIAN_POINT('',(-5.60778761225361,0.,2.89207209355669));
#1050=DIRECTION('',(0.,1.,0.));
#1051=DIRECTION('',(0.,0.,-1.));
#1052=AXIS2_PLACEMENT_3D('',#1049,#1050,#1051);
#1053=CIRCLE('',#1052,3.1);
#1054=CARTESIAN_POINT('',(-3.24067464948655,0.,4.89376543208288));
#1055=VERTEX_POINT('',#1054);
#1056=EDGE_CURVE('E1143',#1055,#1046,#1053,.T.);
#1057=ORIENTED_EDGE('',*,*,#1056,.F.);
#1058=DIRECTION('',(0.645707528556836,0.,-0.763584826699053));
#1059=VECTOR('',#1058,1.);
#1060=CARTESIAN_POINT('',(-4.7205035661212,0.,6.64374488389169));
#1061=LINE('',#1060,#1059);
#1062=CARTESIAN_POINT('',(-3.9281831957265,0.,5.70678227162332));
#1063=VERTEX_POINT('',#1062);
#1064=EDGE_CURVE('E1140',#1063,#1055,#1061,.T.);
#1065=ORIENTED_EDGE('',*,*,#1064,.F.);
#1066=CARTESIAN_POINT('',(-4.67289265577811,0.,6.37417107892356));
#1067=DIRECTION('',(0.,-1.,0.));
#1068=DIRECTION('',(0.,0.,-1.));
#1069=AXIS2_PLACEMENT_3D('',#1066,#1067,#1068);
#1070=CIRCLE('',#1069,0.999999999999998);
#1071=CARTESIAN_POINT('',(-3.99121369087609,0.,7.10582249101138));
#1072=VERTEX_POINT('',#1071);
#1073=EDGE_CURVE('E1173',#1063,#1072,#1070,.T.);
#1074=ORIENTED_EDGE('',*,*,#1073,.T.);
#1075=CARTESIAN_POINT('',(0.,0.,0.));
#1076=DIRECTION('',(0.,-1.,0.));
#1077=DIRECTION('',(0.,0.,-1.));
#1078=AXIS2_PLACEMENT_3D('',#1075,#1076,#1077);
#1079=CIRCLE('',#1078,8.15);
#1080=CARTESIAN_POINT('',(0.,0.,8.15));
#1081=VERTEX_POINT('',#1080);
#1082=EDGE_CURVE('E391',#1081,#1072,#1079,.T.);
#1083=ORIENTED_EDGE('',*,*,#1082,.F.);
#1084=DIRECTION('',(-1.,0.,0.));
#1085=VECTOR('',#1084,1.);
#1086=CARTESIAN_POINT('',(29.55,0.,8.15));
#1087=LINE('',#1086,#1085);
#1088=CARTESIAN_POINT('',(28.1334848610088,0.,8.15));
#1089=VERTEX_POINT('',#1088);
#1090=EDGE_CURVE('E382',#1089,#1081,#1087,.T.);
#1091=ORIENTED_EDGE('',*,*,#1090,.F.);
#1092=CARTESIAN_POINT('',(29.05,0.,7.75));
#1093=DIRECTION('',(0.,-1.,0.));
#1094=DIRECTION('',(0.,0.,-1.));
#1095=AXIS2_PLACEMENT_3D('',#1092,#1093,#1094);
#1096=CIRCLE('',#1095,1.);
#1097=CARTESIAN_POINT('',(29.55,0.,6.88397459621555));
#1098=VERTEX_POINT('',#1097);
#1099=EDGE_CURVE('E389',#1089,#1098,#1096,.T.);
#1100=ORIENTED_EDGE('',*,*,#1099,.T.);
#1101=DIRECTION('',(0.,0.,1.));
#1102=VECTOR('',#1101,1.);
#1103=CARTESIAN_POINT('',(29.55,0.,-8.85));
#1104=LINE('',#1103,#1102);
#1105=CARTESIAN_POINT('',(29.55,0.,6.05));
#1106=VERTEX_POINT('',#1105);
#1107=EDGE_CURVE('E877',#1106,#1098,#1104,.T.);
#1108=ORIENTED_EDGE('',*,*,#1107,.F.);
#1109=DIRECTION('',(1.,0.,0.));
#1110=VECTOR('',#1109,1.);
#1111=CARTESIAN_POINT('',(-8.851,0.,6.05));
#1112=LINE('',#1111,#1110);
#1113=EDGE_CURVE('E853',#1106,#875,#1112,.T.);
#1114=ORIENTED_EDGE('',*,*,#1113,.T.);
#1115=ORIENTED_EDGE('',*,*,#928,.T.);
#1116=DIRECTION('',(1.,0.,0.));
#1117=VECTOR('',#1116,1.);
#1118=CARTESIAN_POINT('',(30.95,0.,8.05));
#1119=LINE('',#1118,#1117);
#1120=CARTESIAN_POINT('',(30.95,0.,8.05));
#1121=VERTEX_POINT('',#1120);
#1122=EDGE_CURVE('E932',#1121,#925,#1119,.T.);
#1123=ORIENTED_EDGE('',*,*,#1122,.F.);
#1124=DIRECTION('',(0.,0.,-1.));
#1125=VECTOR('',#1124,1.);
#1126=CARTESIAN_POINT('',(30.95,0.,0.));
#1127=LINE('',#1126,#1125);
#1128=CARTESIAN_POINT('',(30.95,0.,8.85));
#1129=VERTEX_POINT('',#1128);
#1130=EDGE_CURVE('E959',#1129,#1121,#1127,.T.);
#1131=ORIENTED_EDGE('',*,*,#1130,.F.);
#1132=DIRECTION('',(-1.,0.,0.));
#1133=VECTOR('',#1132,1.);
#1134=CARTESIAN_POINT('',(33.45,0.,8.85));
#1135=LINE('',#1134,#1133);
#1136=EDGE_CURVE('E971',#1129,#850,#1135,.T.);
#1137=ORIENTED_EDGE('',*,*,#1136,.T.);
#1138=ORIENTED_EDGE('',*,*,#851,.F.);
#1139=DIRECTION('',(1.,0.,0.));
#1140=VECTOR('',#1139,1.);
#1141=CARTESIAN_POINT('',(0.,0.,-8.85));
#1142=LINE('',#1141,#1140);
#1143=CARTESIAN_POINT('',(30.95,0.,-8.85));
#1144=VERTEX_POINT('',#1143);
#1145=EDGE_CURVE('E978',#841,#1144,#1142,.T.);
#1146=ORIENTED_EDGE('',*,*,#1145,.T.);
#1147=CARTESIAN_POINT('',(30.95,0.,-8.05));
#1148=VERTEX_POINT('',#1147);
#1149=EDGE_CURVE('E946',#1148,#1144,#1127,.T.);
#1150=ORIENTED_EDGE('',*,*,#1149,.F.);
#1151=DIRECTION('',(1.,0.,0.));
#1152=VECTOR('',#1151,1.);
#1153=CARTESIAN_POINT('',(30.95,0.,-8.05));
#1154=LINE('',#1153,#1152);
#1155=EDGE_CURVE('E950',#1148,#899,#1154,.T.);
#1156=ORIENTED_EDGE('',*,*,#1155,.T.);
#1157=ORIENTED_EDGE('',*,*,#900,.T.);
#1158=DIRECTION('',(1.,0.,0.));
#1159=VECTOR('',#1158,1.);
#1160=CARTESIAN_POINT('',(-8.851,0.,-6.05));
#1161=LINE('',#1160,#1159);
#1162=CARTESIAN_POINT('',(29.55,0.,-6.05));
#1163=VERTEX_POINT('',#1162);
#1164=EDGE_CURVE('E836',#1163,#891,#1161,.T.);
#1165=ORIENTED_EDGE('',*,*,#1164,.F.);
#1166=CARTESIAN_POINT('',(29.55,0.,-6.88397459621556));
#1167=VERTEX_POINT('',#1166);
#1168=EDGE_CURVE('E848',#1167,#1163,#1104,.T.);
#1169=ORIENTED_EDGE('',*,*,#1168,.F.);
#1170=CARTESIAN_POINT('',(29.05,0.,-7.75));
#1171=DIRECTION('',(0.,-1.,0.));
#1172=DIRECTION('',(0.,0.,-1.));
#1173=AXIS2_PLACEMENT_3D('',#1170,#1171,#1172);
#1174=CIRCLE('',#1173,1.);
#1175=CARTESIAN_POINT('',(28.1334848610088,0.,-8.15));
#1176=VERTEX_POINT('',#1175);
#1177=EDGE_CURVE('E432',#1167,#1176,#1174,.T.);
#1178=ORIENTED_EDGE('',*,*,#1177,.T.);
#1179=DIRECTION('',(1.,0.,0.));
#1180=VECTOR('',#1179,1.);
#1181=CARTESIAN_POINT('',(0.,0.,-8.15));
#1182=LINE('',#1181,#1180);
#1183=EDGE_CURVE('E1047',#1029,#1176,#1182,.T.);
#1184=ORIENTED_EDGE('',*,*,#1183,.F.);
#1185=EDGE_LOOP('',(#1031,#1040,#1048,#1057,#1065,#1074,#1083,#1091,#1100,#1108,#1114,#1115,
#1123,#1131,#1137,#1138,#1146,#1150,#1156,#1157,#1165,#1169,#1178,#1184));
#1186=FACE_BOUND('',#1185,.T.);
#1187=DIRECTION('',(-0.9965201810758,0.,0.0833518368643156));
#1188=VECTOR('',#1187,1.);
#1189=CARTESIAN_POINT('',(-7.17110615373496,0.,2.01934061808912));
#1190=LINE('',#1189,#1188);
#1191=CARTESIAN_POINT('',(-5.26746352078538,0.,1.86011442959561));
#1192=VERTEX_POINT('',#1191);
#1193=CARTESIAN_POINT('',(-7.17110615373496,0.,2.01934061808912));
#1194=VERTEX_POINT('',#1193);
#1195=EDGE_CURVE('E1225',#1192,#1194,#1190,.T.);
#1196=ORIENTED_EDGE('',*,*,#1195,.T.);
#1197=CARTESIAN_POINT('',(0.,0.,0.));
#1198=DIRECTION('',(0.,1.,0.));
#1199=DIRECTION('',(0.,0.,-1.));
#1200=AXIS2_PLACEMENT_3D('',#1197,#1198,#1199);
#1201=CIRCLE('',#1200,7.45);
#1202=CARTESIAN_POINT('',(-5.80316544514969,0.,4.67180594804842));
#1203=VERTEX_POINT('',#1202);
#1204=EDGE_CURVE('E795',#1194,#1203,#1201,.T.);
#1205=ORIENTED_EDGE('',*,*,#1204,.T.);
#1206=DIRECTION('',(0.645707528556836,0.,-0.763584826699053));
#1207=VECTOR('',#1206,1.);
#1208=CARTESIAN_POINT('',(-4.56967674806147,0.,3.21313741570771));
#1209=LINE('',#1208,#1207);
#1210=CARTESIAN_POINT('',(-4.56967674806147,0.,3.21313741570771));
#1211=VERTEX_POINT('',#1210);
#1212=EDGE_CURVE('E1242',#1203,#1211,#1209,.T.);
#1213=ORIENTED_EDGE('',*,*,#1212,.T.);
#1214=CARTESIAN_POINT('',(-5.19879036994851,0.,2.68114229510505));
#1215=DIRECTION('',(0.,1.,0.));
#1216=DIRECTION('',(0.,0.,-1.));
#1217=AXIS2_PLACEMENT_3D('',#1214,#1215,#1216);
#1218=CIRCLE('',#1217,0.823894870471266);
#1219=EDGE_CURVE('E1239',#1211,#1192,#1218,.T.);
#1220=ORIENTED_EDGE('',*,*,#1219,.T.);
#1221=EDGE_LOOP('',(#1196,#1205,#1213,#1220));
#1222=FACE_BOUND('',#1221,.T.);
#1223=ADVANCED_FACE('F385',(#987,#998,#1009,#1020,#1186,#1222),#976,.F.);
#1224=CARTESIAN_POINT('',(33.45,0.,4.75));
#1225=DIRECTION('',(-1.,0.,0.));
#1226=DIRECTION('',(0.,0.,1.));
#1227=AXIS2_PLACEMENT_3D('',#1224,#1225,#1226);
#1228=CYLINDRICAL_SURFACE('',#1227,4.1);
#1229=ORIENTED_EDGE('',*,*,#1136,.F.);
#1230=CARTESIAN_POINT('',(30.95,0.,4.75));
#1231=DIRECTION('',(1.,0.,0.));
#1232=DIRECTION('',(0.,0.,-1.));
#1233=AXIS2_PLACEMENT_3D('',#1230,#1231,#1232);
#1234=CIRCLE('',#1233,4.1);
#1235=EDGE_CURVE('E963',#1129,#952,#1234,.F.);
#1236=ORIENTED_EDGE('',*,*,#1235,.T.);
#1237=ORIENTED_EDGE('',*,*,#953,.F.);
#1238=ORIENTED_EDGE('',*,*,#858,.F.);
#1239=EDGE_LOOP('',(#1229,#1236,#1237,#1238));
#1240=FACE_BOUND('',#1239,.T.);
#1241=ADVANCED_FACE('F738',(#1240),#1228,.T.);
#1242=CARTESIAN_POINT('',(0.,0.,-4.75));
#1243=DIRECTION('',(1.,0.,0.));
#1244=DIRECTION('',(0.,0.,-1.));
#1245=AXIS2_PLACEMENT_3D('',#1242,#1243,#1244);
#1246=CYLINDRICAL_SURFACE('',#1245,4.1);
#1247=ORIENTED_EDGE('',*,*,#967,.F.);
#1248=CARTESIAN_POINT('',(30.95,0.,-4.75));
#1249=DIRECTION('',(1.,0.,0.));
#1250=DIRECTION('',(0.,0.,-1.));
#1251=AXIS2_PLACEMENT_3D('',#1248,#1249,#1250);
#1252=CIRCLE('',#1251,4.1);
#1253=EDGE_CURVE('E994',#960,#1144,#1252,.F.);
#1254=ORIENTED_EDGE('',*,*,#1253,.T.);
#1255=ORIENTED_EDGE('',*,*,#1145,.F.);
#1256=ORIENTED_EDGE('',*,*,#842,.T.);
#1257=EDGE_LOOP('',(#1247,#1254,#1255,#1256));
#1258=FACE_BOUND('',#1257,.T.);
#1259=ADVANCED_FACE('F740',(#1258),#1246,.T.);
#1260=CARTESIAN_POINT('',(30.95,2.05,0.));
#1261=DIRECTION('',(1.,0.,0.));
#1262=DIRECTION('',(0.,0.,-1.));
#1263=AXIS2_PLACEMENT_3D('',#1260,#1261,#1262);
#1264=PLANE('',#1263);
#1265=ORIENTED_EDGE('',*,*,#1130,.T.);
#1266=CARTESIAN_POINT('',(30.95,0.,4.75));
#1267=DIRECTION('',(1.,0.,0.));
#1268=DIRECTION('',(0.,0.,-1.));
#1269=AXIS2_PLACEMENT_3D('',#1266,#1267,#1268);
#1270=CIRCLE('',#1269,3.3);
#1271=CARTESIAN_POINT('',(30.95,3.3,4.75));
#1272=VERTEX_POINT('',#1271);
#1273=EDGE_CURVE('E919',#1272,#1121,#1270,.T.);
#1274=ORIENTED_EDGE('',*,*,#1273,.F.);
#1275=DIRECTION('',(0.,0.,1.));
#1276=VECTOR('',#1275,1.);
#1277=CARTESIAN_POINT('',(30.95,3.3,-4.75));
#1278=LINE('',#1277,#1276);
#1279=CARTESIAN_POINT('',(30.95,3.3,-4.75));
#1280=VERTEX_POINT('',#1279);
#1281=EDGE_CURVE('E928',#1280,#1272,#1278,.T.);
#1282=ORIENTED_EDGE('',*,*,#1281,.F.);
#1283=CARTESIAN_POINT('',(30.95,0.,-4.75));
#1284=DIRECTION('',(1.,0.,0.));
#1285=DIRECTION('',(0.,0.,-1.));
#1286=AXIS2_PLACEMENT_3D('',#1283,#1284,#1285);
#1287=CIRCLE('',#1286,3.3);
#1288=EDGE_CURVE('E923',#1148,#1280,#1287,.T.);
#1289=ORIENTED_EDGE('',*,*,#1288,.F.);
#1290=ORIENTED_EDGE('',*,*,#1149,.T.);
#1291=ORIENTED_EDGE('',*,*,#1253,.F.);
#1292=ORIENTED_EDGE('',*,*,#961,.F.);
#1293=ORIENTED_EDGE('',*,*,#1235,.F.);
#1294=EDGE_LOOP('',(#1265,#1274,#1282,#1289,#1290,#1291,#1292,#1293));
#1295=FACE_BOUND('',#1294,.T.);
#1296=ADVANCED_FACE('F746',(#1295),#1264,.T.);
#1297=CARTESIAN_POINT('',(30.95,0.,4.75));
#1298=DIRECTION('',(1.,0.,0.));
#1299=DIRECTION('',(0.,0.,-1.));
#1300=AXIS2_PLACEMENT_3D('',#1297,#1298,#1299);
#1301=CYLINDRICAL_SURFACE('',#1300,3.3);
#1302=ORIENTED_EDGE('',*,*,#926,.F.);
#1303=DIRECTION('',(1.,0.,0.));
#1304=VECTOR('',#1303,1.);
#1305=CARTESIAN_POINT('',(30.95,3.3,4.75));
#1306=LINE('',#1305,#1304);
#1307=EDGE_CURVE('E943',#1272,#916,#1306,.T.);
#1308=ORIENTED_EDGE('',*,*,#1307,.F.);
#1309=ORIENTED_EDGE('',*,*,#1273,.T.);
#1310=ORIENTED_EDGE('',*,*,#1122,.T.);
#1311=EDGE_LOOP('',(#1302,#1308,#1309,#1310));
#1312=FACE_BOUND('',#1311,.T.);
#1313=ADVANCED_FACE('F1311',(#1312),#1301,.T.);
#1314=CARTESIAN_POINT('',(30.95,3.3,-4.75));
#1315=DIRECTION('',(0.,1.,0.));
#1316=DIRECTION('',(0.,0.,1.));
#1317=AXIS2_PLACEMENT_3D('',#1314,#1315,#1316);
#1318=PLANE('',#1317);
#1319=ORIENTED_EDGE('',*,*,#917,.F.);
#1320=DIRECTION('',(1.,0.,0.));
#1321=VECTOR('',#1320,1.);
#1322=CARTESIAN_POINT('',(30.95,3.3,-4.75));
#1323=LINE('',#1322,#1321);
#1324=EDGE_CURVE('E947',#1280,#908,#1323,.T.);
#1325=ORIENTED_EDGE('',*,*,#1324,.F.);
#1326=ORIENTED_EDGE('',*,*,#1281,.T.);
#1327=ORIENTED_EDGE('',*,*,#1307,.T.);
#1328=EDGE_LOOP('',(#1319,#1325,#1326,#1327));
#1329=FACE_BOUND('',#1328,.T.);
#1330=ADVANCED_FACE('F1305',(#1329),#1318,.T.);
#1331=CARTESIAN_POINT('',(30.95,0.,-4.75));
#1332=DIRECTION('',(1.,0.,0.));
#1333=DIRECTION('',(0.,0.,-1.));
#1334=AXIS2_PLACEMENT_3D('',#1331,#1332,#1333);
#1335=CYLINDRICAL_SURFACE('',#1334,3.3);
#1336=ORIENTED_EDGE('',*,*,#909,.F.);
#1337=ORIENTED_EDGE('',*,*,#1155,.F.);
#1338=ORIENTED_EDGE('',*,*,#1288,.T.);
#1339=ORIENTED_EDGE('',*,*,#1324,.T.);
#1340=EDGE_LOOP('',(#1336,#1337,#1338,#1339));
#1341=FACE_BOUND('',#1340,.T.);
#1342=ADVANCED_FACE('F1300',(#1341),#1335,.T.);
#1343=CARTESIAN_POINT('',(-4.08061795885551,1.3,4.18348715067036));
#1344=DIRECTION('',(-0.763584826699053,0.,-0.645707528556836));
#1345=DIRECTION('',(-0.645707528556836,0.,0.763584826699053));
#1346=AXIS2_PLACEMENT_3D('',#1343,#1344,#1345);
#1347=PLANE('',#1346);
#1348=DIRECTION('',(-0.645707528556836,0.,0.763584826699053));
#1349=VECTOR('',#1348,1.);
#1350=CARTESIAN_POINT('',(-4.08061795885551,1.3,4.18348715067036));
#1351=LINE('',#1350,#1349);
#1352=CARTESIAN_POINT('',(-4.08061795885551,1.3,4.18348715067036));
#1353=VERTEX_POINT('',#1352);
#1354=CARTESIAN_POINT('',(-5.75615768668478,1.3,6.16490544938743));
#1355=VERTEX_POINT('',#1354);
#1356=EDGE_CURVE('E898',#1353,#1355,#1351,.T.);
#1357=ORIENTED_EDGE('',*,*,#1356,.T.);
#1358=CARTESIAN_POINT('',(-5.88387948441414,-0.443561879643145,6.31594353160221));
#1359=CARTESIAN_POINT('',(-5.89193742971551,-0.334578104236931,6.32547249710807));
#1360=CARTESIAN_POINT('',(-5.89702063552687,-0.225119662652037,6.331483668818));
#1361=CARTESIAN_POINT('',(-5.90121821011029,-0.00593407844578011,6.33644753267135));
#1362=CARTESIAN_POINT('',(-5.90033286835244,0.103793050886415,6.33540056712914));
#1363=CARTESIAN_POINT('',(-5.88870770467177,0.432034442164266,6.32165316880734));
#1364=CARTESIAN_POINT('',(-5.86902371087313,0.649949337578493,6.29837575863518));
#1365=CARTESIAN_POINT('',(-5.80630086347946,1.07762085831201,6.22420252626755));
#1366=CARTESIAN_POINT('',(-5.76324427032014,1.28737115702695,6.17328572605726));
#1367=CARTESIAN_POINT('',(-5.65501442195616,1.69264608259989,6.04529795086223));
#1368=CARTESIAN_POINT('',(-5.58984939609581,1.88817596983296,5.96823670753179));
#1369=CARTESIAN_POINT('',(-5.43922842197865,2.25955495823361,5.7901190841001));
#1370=CARTESIAN_POINT('',(-5.35376793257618,2.43539964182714,5.6890573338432));
#1371=CARTESIAN_POINT('',(-5.16491623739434,2.76252295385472,5.4657297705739));
#1372=CARTESIAN_POINT('',(-5.06150732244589,2.91377703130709,5.34344301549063));
#1373=CARTESIAN_POINT('',(-4.82203449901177,3.20905229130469,5.06025317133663));
#1374=CARTESIAN_POINT('',(-4.68339279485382,3.34808500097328,4.89630169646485));
#1375=CARTESIAN_POINT('',(-4.39140984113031,3.58154263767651,4.5510157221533));
#1376=CARTESIAN_POINT('',(-4.23809422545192,3.67604370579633,4.36971153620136));
#1377=CARTESIAN_POINT('',(-4.03635412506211,3.76634491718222,4.1311427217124));
#1378=CARTESIAN_POINT('',(-3.99176156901,3.7842607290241,4.07840956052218));
#1379=CARTESIAN_POINT('',(-3.90210931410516,3.81624804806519,3.97239081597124));
#1380=CARTESIAN_POINT('',(-3.85705087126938,3.83032799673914,3.91910671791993));
#1381=CARTESIAN_POINT('',(-3.8117553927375,3.84250485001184,3.8655423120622));
#1382=B_SPLINE_CURVE_WITH_KNOTS('',3,(#1358,#1359,#1360,#1361,#1362,#1363,#1364,#1365,#1366,
#1367,#1368,#1369,#1370,#1371,#1372,#1373,#1374,#1375,#1376,#1377,#1378,#1379,#1380,#1381),
.UNSPECIFIED.,.F.,.F.,(4,2,2,2,2,2,2,2,2,2,2,4),(0.,0.328885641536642,0.657755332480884,
1.31447935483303,1.97170252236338,2.62868132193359,3.28580726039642,3.94358528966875,
4.70612332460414,5.46735278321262,5.68132111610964,5.89481469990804),.UNSPECIFIED.);
#1383=CARTESIAN_POINT('',(-4.08061795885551,3.74653191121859,4.18348715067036));
#1384=VERTEX_POINT('',#1383);
#1385=EDGE_CURVE('E583',#1355,#1384,#1382,.T.);
#1386=ORIENTED_EDGE('',*,*,#1385,.T.);
#1387=DIRECTION('',(0.,1.,0.));
#1388=VECTOR('',#1387,1.);
#1389=CARTESIAN_POINT('',(-4.08061795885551,1.3,4.18348715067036));
#1390=LINE('',#1389,#1388);
#1391=EDGE_CURVE('E910',#1353,#1384,#1390,.T.);
#1392=ORIENTED_EDGE('',*,*,#1391,.F.);
#1393=EDGE_LOOP('',(#1357,#1386,#1392));
#1394=FACE_BOUND('',#1393,.T.);
#1395=ADVANCED_FACE('F662',(#1394),#1347,.T.);
#1396=CARTESIAN_POINT('',(-8.77496438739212,1.3,1.15));
#1397=DIRECTION('',(0.083351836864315,0.,0.9965201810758));
#1398=DIRECTION('',(0.9965201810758,0.,-0.083351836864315));
#1399=AXIS2_PLACEMENT_3D('',#1396,#1397,#1398);
#1400=PLANE('',#1399);
#1401=DIRECTION('',(0.,1.,0.));
#1402=VECTOR('',#1401,1.);
#1403=CARTESIAN_POINT('',(-5.77449128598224,1.3,0.899031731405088));
#1404=LINE('',#1403,#1402);
#1405=CARTESIAN_POINT('',(-5.77449128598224,1.3,0.899031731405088));
#1406=VERTEX_POINT('',#1405);
#1407=CARTESIAN_POINT('',(-5.77449128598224,3.74653191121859,0.899031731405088));
#1408=VERTEX_POINT('',#1407);
#1409=EDGE_CURVE('E914',#1406,#1408,#1404,.T.);
#1410=ORIENTED_EDGE('',*,*,#1409,.T.);
#1411=CARTESIAN_POINT('',(-5.3595557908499,3.84250485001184,0.864325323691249));
#1412=CARTESIAN_POINT('',(-5.4294602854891,3.83032799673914,0.870172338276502));
#1413=CARTESIAN_POINT('',(-5.49899896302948,3.81624804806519,0.875988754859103));
#1414=CARTESIAN_POINT('',(-5.63735925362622,3.7842607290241,0.887561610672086));
#1415=CARTESIAN_POINT('',(-5.70617892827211,3.76634491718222,0.893317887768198));
#1416=CARTESIAN_POINT('',(-6.01752434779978,3.67604370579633,0.919359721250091));
#1417=CARTESIAN_POINT('',(-6.25413627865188,3.58154263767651,0.939150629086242));
#1418=CARTESIAN_POINT('',(-6.70475345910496,3.34808500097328,0.976841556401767));
#1419=CARTESIAN_POINT('',(-6.91871914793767,3.20905229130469,0.994738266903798));
#1420=CARTESIAN_POINT('',(-7.28829746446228,2.91377703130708,1.0256508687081));
#1421=CARTESIAN_POINT('',(-7.44788840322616,2.76252295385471,1.03899951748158));
#1422=CARTESIAN_POINT('',(-7.7393431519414,2.43539964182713,1.06337763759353));
#1423=CARTESIAN_POINT('',(-7.87123429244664,2.25955495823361,1.07440939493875));
#1424=CARTESIAN_POINT('',(-8.10368758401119,1.88817596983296,1.09385246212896));
#1425=CARTESIAN_POINT('',(-8.20425674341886,1.69264608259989,1.10226435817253));
#1426=CARTESIAN_POINT('',(-8.37128782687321,1.28737115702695,1.11623532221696));
#1427=CARTESIAN_POINT('',(-8.43773705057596,1.077620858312,1.12179332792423));
#1428=CARTESIAN_POINT('',(-8.53453719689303,0.649949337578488,1.12988997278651));
#1429=CARTESIAN_POINT('',(-8.56491549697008,0.43203444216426,1.13243090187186));
#1430=CARTESIAN_POINT('',(-8.5828566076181,0.10379305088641,1.13393154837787));
#1431=CARTESIAN_POINT('',(-8.58422295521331,-0.00593407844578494,1.13404583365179));
#1432=CARTESIAN_POINT('',(-8.57774483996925,-0.225119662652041,1.13350398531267));
#1433=CARTESIAN_POINT('',(-8.5698999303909,-0.334578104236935,1.13284781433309));
#1434=CARTESIAN_POINT('',(-8.55746410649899,-0.443561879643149,1.13180764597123));
#1435=B_SPLINE_CURVE_WITH_KNOTS('',3,(#1411,#1412,#1413,#1414,#1415,#1416,#1417,#1418,#1419,
#1420,#1421,#1422,#1423,#1424,#1425,#1426,#1427,#1428,#1429,#1430,#1431,#1432,#1433,#1434),
.UNSPECIFIED.,.F.,.F.,(4,2,2,2,2,2,2,2,2,2,2,4),(0.,0.213493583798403,0.427461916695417,
1.1886913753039,1.95122941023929,2.60900743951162,3.26613337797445,3.92311217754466,
4.58033534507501,5.23705936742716,5.5659290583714,5.89481469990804),.UNSPECIFIED.);
#1436=CARTESIAN_POINT('',(-8.36035110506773,1.3,1.11532054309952));
#1437=VERTEX_POINT('',#1436);
#1438=EDGE_CURVE('E606',#1408,#1437,#1435,.T.);
#1439=ORIENTED_EDGE('',*,*,#1438,.T.);
#1440=DIRECTION('',(0.9965201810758,0.,-0.083351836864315));
#1441=VECTOR('',#1440,1.);
#1442=CARTESIAN_POINT('',(-8.77496438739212,1.3,1.15));
#1443=LINE('',#1442,#1441);
#1444=EDGE_CURVE('E904',#1437,#1406,#1443,.T.);
#1445=ORIENTED_EDGE('',*,*,#1444,.T.);
#1446=EDGE_LOOP('',(#1410,#1439,#1445));
#1447=FACE_BOUND('',#1446,.T.);
#1448=ADVANCED_FACE('F514',(#1447),#1400,.T.);
#1449=CARTESIAN_POINT('',(-5.60778761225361,1.3,2.89207209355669));
#1450=DIRECTION('',(0.,1.,0.));
#1451=DIRECTION('',(0.,0.,1.));
#1452=AXIS2_PLACEMENT_3D('',#1449,#1450,#1451);
#1453=CYLINDRICAL_SURFACE('',#1452,2.);
#1454=ORIENTED_EDGE('',*,*,#1391,.T.);
#1455=CARTESIAN_POINT('',(-4.57465204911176,3.46378065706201,4.60456469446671));
#1456=CARTESIAN_POINT('',(-4.5298490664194,3.49243996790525,4.57752889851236));
#1457=CARTESIAN_POINT('',(-4.48568733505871,3.51997005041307,4.54849020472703));
#1458=CARTESIAN_POINT('',(-4.39897737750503,3.57258609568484,4.48632410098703));
#1459=CARTESIAN_POINT('',(-4.35643120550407,3.59766900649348,4.45319169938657));
#1460=CARTESIAN_POINT('',(-4.23199142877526,3.66880062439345,4.34773285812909));
#1461=CARTESIAN_POINT('',(-4.15317172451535,3.71081191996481,4.2692709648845));
#1462=CARTESIAN_POINT('',(-4.03307266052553,3.76993962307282,4.12727205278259));
#1463=CARTESIAN_POINT('',(-3.98821816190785,3.79064564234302,4.06791268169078));
#1464=CARTESIAN_POINT('',(-3.90493653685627,3.826487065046,3.94367889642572));
#1465=CARTESIAN_POINT('',(-3.86649946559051,3.84163113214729,3.87881325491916));
#1466=CARTESIAN_POINT('',(-3.78569239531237,3.87044855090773,3.7227151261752));
#1467=CARTESIAN_POINT('',(-3.74605726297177,3.8820695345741,3.62972987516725));
#1468=CARTESIAN_POINT('',(-3.68110133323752,3.8968588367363,3.4381197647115));
#1469=CARTESIAN_POINT('',(-3.65582501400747,3.90000100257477,3.33947841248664));
#1470=CARTESIAN_POINT('',(-3.61873271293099,3.89999889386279,3.12912727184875));
#1471=CARTESIAN_POINT('',(-3.60857683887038,3.8961717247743,3.01712007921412));
#1472=CARTESIAN_POINT('',(-3.60745894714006,3.88778042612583,2.84943909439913));
#1473=CARTESIAN_POINT('',(-3.60943062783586,3.88454578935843,2.79365193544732));
#1474=CARTESIAN_POINT('',(-3.61802133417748,3.87774580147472,2.68247788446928));
#1475=CARTESIAN_POINT('',(-3.62463828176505,3.87418059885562,2.62709082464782));
#1476=CARTESIAN_POINT('',(-3.6335585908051,3.87072392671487,2.5720412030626));
#1477=B_SPLINE_CURVE_WITH_KNOTS('',3,(#1455,#1456,#1457,#1458,#1459,#1460,#1461,#1462,#1463,
#1464,#1465,#1466,#1467,#1468,#1469,#1470,#1471,#1472,#1473,#1474,#1475,#1476),.UNSPECIFIED.,
.F.,.F.,(4,2,2,2,2,2,2,2,2,2,4),(0.,0.192788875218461,0.38581519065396,0.77133970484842,
1.02397825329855,1.27622158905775,1.60988036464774,1.9445671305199,2.31382585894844,
2.49811404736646,2.68231984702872),.UNSPECIFIED.);
#1478=CARTESIAN_POINT('',(-3.63818969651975,3.9,3.23946819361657));
#1479=VERTEX_POINT('',#1478);
#1480=EDGE_CURVE('E591',#1384,#1479,#1477,.T.);
#1481=ORIENTED_EDGE('',*,*,#1480,.T.);
#1482=CARTESIAN_POINT('',(-5.60778761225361,3.9,2.89207209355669));
#1483=DIRECTION('',(0.,1.,0.));
#1484=DIRECTION('',(0.,0.,1.));
#1485=AXIS2_PLACEMENT_3D('',#1482,#1483,#1484);
#1486=CIRCLE('',#1485,2.);
#1487=CARTESIAN_POINT('',(-4.74882689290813,3.9,1.08591969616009));
#1488=VERTEX_POINT('',#1487);
#1489=EDGE_CURVE('E582',#1479,#1488,#1486,.T.);
#1490=ORIENTED_EDGE('',*,*,#1489,.T.);
#1491=CARTESIAN_POINT('',(-4.20235650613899,3.87072392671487,1.46913027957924));
#1492=CARTESIAN_POINT('',(-4.24209056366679,3.87418470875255,1.42989185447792));
#1493=CARTESIAN_POINT('',(-4.28343474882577,3.87775486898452,1.39234050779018));
#1494=CARTESIAN_POINT('',(-4.36915707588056,3.88456387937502,1.3207914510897));
#1495=CARTESIAN_POINT('',(-4.41353715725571,3.88780251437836,1.28679604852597));
#1496=CARTESIAN_POINT('',(-4.55077630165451,3.89618172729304,1.19055276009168));
#1497=CARTESIAN_POINT('',(-4.64781756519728,3.89999508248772,1.1339655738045));
#1498=CARTESIAN_POINT('',(-4.81805246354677,3.90000337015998,1.05299201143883));
#1499=CARTESIAN_POINT('',(-4.88914178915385,3.89821796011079,1.02407608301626));
#1500=CARTESIAN_POINT('',(-5.03388842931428,3.89009175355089,0.974658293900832));
#1501=CARTESIAN_POINT('',(-5.10754191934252,3.88375748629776,0.954144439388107));
#1502=CARTESIAN_POINT('',(-5.28020310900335,3.86294721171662,0.91652477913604));
#1503=CARTESIAN_POINT('',(-5.37974187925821,3.84650700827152,0.902640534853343));
#1504=CARTESIAN_POINT('',(-5.57828809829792,3.80381766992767,0.889803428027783));
#1505=CARTESIAN_POINT('',(-5.67729301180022,3.7775388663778,0.890896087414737));
#1506=CARTESIAN_POINT('',(-5.88662344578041,3.71076093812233,0.908417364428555));
#1507=CARTESIAN_POINT('',(-5.99635116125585,3.66869729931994,0.927176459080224));
#1508=CARTESIAN_POINT('',(-6.15445763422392,3.59752226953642,0.967461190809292));
#1509=CARTESIAN_POINT('',(-6.20605117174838,3.57246736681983,0.982901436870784));
#1510=CARTESIAN_POINT('',(-6.30685295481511,3.51990870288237,1.01746979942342));
#1511=CARTESIAN_POINT('',(-6.3560635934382,3.49240748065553,1.03659411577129));
#1512=CARTESIAN_POINT('',(-6.40401169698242,3.46378065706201,1.05739849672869));
#1513=B_SPLINE_CURVE_WITH_KNOTS('',3,(#1491,#1492,#1493,#1494,#1495,#1496,#1497,#1498,#1499,
#1500,#1501,#1502,#1503,#1504,#1505,#1506,#1507,#1508,#1509,#1510,#1511,#1512),.UNSPECIFIED.,
.F.,.F.,(4,2,2,2,2,2,2,2,2,2,4),(0.,0.1844449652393,0.369008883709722,0.737754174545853,
0.990469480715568,1.24282277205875,1.57639146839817,1.91097426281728,2.29696353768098,
2.48973689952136,2.68231246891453),.UNSPECIFIED.);
#1514=EDGE_CURVE('E574',#1488,#1408,#1513,.T.);
#1515=ORIENTED_EDGE('',*,*,#1514,.T.);
#1516=ORIENTED_EDGE('',*,*,#1409,.F.);
#1517=CARTESIAN_POINT('',(-5.60778761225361,1.3,2.89207209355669));
#1518=DIRECTION('',(0.,-1.,0.));
#1519=DIRECTION('',(0.,0.,-1.));
#1520=AXIS2_PLACEMENT_3D('',#1517,#1518,#1519);
#1521=CIRCLE('',#1520,2.);
#1522=EDGE_CURVE('E907',#1406,#1353,#1521,.T.);
#1523=ORIENTED_EDGE('',*,*,#1522,.T.);
#1524=EDGE_LOOP('',(#1454,#1481,#1490,#1515,#1516,#1523));
#1525=FACE_BOUND('',#1524,.T.);
#1526=ADVANCED_FACE('F473',(#1525),#1453,.F.);
#1527=CARTESIAN_POINT('',(0.,1.3,0.));
#1528=DIRECTION('',(0.,-1.,0.));
#1529=DIRECTION('',(0.,0.,-1.));
#1530=AXIS2_PLACEMENT_3D('',#1527,#1528,#1529);
#1531=PLANE('',#1530);
#1532=CARTESIAN_POINT('',(-5.19879036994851,1.3,2.68114229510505));
#1533=DIRECTION('',(0.,-1.,0.));
#1534=DIRECTION('',(0.,0.,-1.));
#1535=AXIS2_PLACEMENT_3D('',#1532,#1533,#1534);
#1536=CIRCLE('',#1535,1.02389487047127);
#1537=CARTESIAN_POINT('',(-5.28413388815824,1.3,1.66081039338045));
#1538=VERTEX_POINT('',#1537);
#1539=CARTESIAN_POINT('',(-4.41695978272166,1.3,3.34227892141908));
#1540=VERTEX_POINT('',#1539);
#1541=EDGE_CURVE('E1265',#1538,#1540,#1536,.T.);
#1542=ORIENTED_EDGE('',*,*,#1541,.T.);
#1543=DIRECTION('',(0.645707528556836,0.,-0.763584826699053));
#1544=VECTOR('',#1543,1.);
#1545=CARTESIAN_POINT('',(-0.927441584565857,1.3,-0.784269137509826));
#1546=LINE('',#1545,#1544);
#1547=CARTESIAN_POINT('',(-5.80444768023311,1.3,4.98306001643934));
#1548=VERTEX_POINT('',#1547);
#1549=EDGE_CURVE('E1406',#1540,#1548,#1546,.F.);
#1550=ORIENTED_EDGE('',*,*,#1549,.T.);
#1551=CARTESIAN_POINT('',(0.,1.3,0.));
#1552=DIRECTION('',(0.,-1.,0.));
#1553=DIRECTION('',(0.,0.,-1.));
#1554=AXIS2_PLACEMENT_3D('',#1551,#1552,#1553);
#1555=CIRCLE('',#1554,7.65);
#1556=CARTESIAN_POINT('',(-7.42544342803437,1.3,1.83991573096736));
#1557=VERTEX_POINT('',#1556);
#1558=EDGE_CURVE('E1401',#1548,#1557,#1555,.T.);
#1559=ORIENTED_EDGE('',*,*,#1558,.T.);
#1560=DIRECTION('',(-0.9965201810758,0.,0.0833518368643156));
#1561=VECTOR('',#1560,1.);
#1562=CARTESIAN_POINT('',(0.101238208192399,1.3,1.21036225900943));
#1563=LINE('',#1562,#1561);
#1564=EDGE_CURVE('E1398',#1557,#1538,#1563,.F.);
#1565=ORIENTED_EDGE('',*,*,#1564,.T.);
#1566=EDGE_LOOP('',(#1542,#1550,#1559,#1565));
#1567=FACE_BOUND('',#1566,.T.);
#1568=ORIENTED_EDGE('',*,*,#1444,.F.);
#1569=CARTESIAN_POINT('',(-8.36035110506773,1.3,1.11532054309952));
#1570=CARTESIAN_POINT('',(-8.37009374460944,1.3,1.11613286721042));
#1571=CARTESIAN_POINT('',(-8.37980686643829,1.3,1.1163129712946));
#1572=CARTESIAN_POINT('',(-8.39917412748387,1.3,1.11540873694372));
#1573=CARTESIAN_POINT('',(-8.40882826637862,1.3,1.1143243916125));
#1574=CARTESIAN_POINT('',(-8.41845288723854,1.3,1.11260781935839));
#1575=B_SPLINE_CURVE_WITH_KNOTS('',3,(#1569,#1570,#1571,#1572,#1573,#1574),.UNSPECIFIED.,.F.,
.F.,(4,2,4),(0.,0.0291443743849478,0.058288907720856),.UNSPECIFIED.);
#1576=CARTESIAN_POINT('',(-8.41845288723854,1.3,1.11260781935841));
#1577=VERTEX_POINT('',#1576);
#1578=EDGE_CURVE('E13',#1437,#1577,#1575,.T.);
#1579=ORIENTED_EDGE('',*,*,#1578,.T.);
#1580=CARTESIAN_POINT('',(0.,1.3,0.));
#1581=DIRECTION('',(0.,-1.,0.));
#1582=DIRECTION('',(0.,0.,-1.));
#1583=AXIS2_PLACEMENT_3D('',#1580,#1581,#1582);
#1584=CIRCLE('',#1583,8.49165738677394);
#1585=CARTESIAN_POINT('',(-5.78763574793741,1.3,6.21381667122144));
#1586=VERTEX_POINT('',#1585);
#1587=EDGE_CURVE('E107',#1577,#1586,#1584,.F.);
#1588=ORIENTED_EDGE('',*,*,#1587,.T.);
#1589=CARTESIAN_POINT('',(-5.78763574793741,1.3,6.21381667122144));
#1590=CARTESIAN_POINT('',(-5.78345382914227,1.3,6.2049797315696));
#1591=CARTESIAN_POINT('',(-5.77873968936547,1.3,6.19648531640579));
#1592=CARTESIAN_POINT('',(-5.76824699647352,1.3,6.18018157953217));
#1593=CARTESIAN_POINT('',(-5.7624684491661,1.3,6.17237225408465));
#1594=CARTESIAN_POINT('',(-5.75615768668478,1.3,6.16490544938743));
#1595=B_SPLINE_CURVE_WITH_KNOTS('',3,(#1589,#1590,#1591,#1592,#1593,#1594),.UNSPECIFIED.,.F.,
.F.,(4,2,4),(0.,0.0291445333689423,0.0582889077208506),.UNSPECIFIED.);
#1596=EDGE_CURVE('E99',#1586,#1355,#1595,.T.);
#1597=ORIENTED_EDGE('',*,*,#1596,.T.);
#1598=ORIENTED_EDGE('',*,*,#1356,.F.);
#1599=ORIENTED_EDGE('',*,*,#1522,.F.);
#1600=EDGE_LOOP('',(#1568,#1579,#1588,#1597,#1598,#1599));
#1601=FACE_BOUND('',#1600,.T.);
#1602=ADVANCED_FACE('F468',(#1567,#1601),#1531,.F.);
#1603=CARTESIAN_POINT('',(29.55,4.1,-8.85));
#1604=DIRECTION('',(1.,0.,0.));
#1605=DIRECTION('',(0.,0.,-1.));
#1606=AXIS2_PLACEMENT_3D('',#1603,#1604,#1605);
#1607=PLANE('',#1606);
#1608=ORIENTED_EDGE('',*,*,#1107,.T.);
#1609=DIRECTION('',(0.,-1.,0.));
#1610=VECTOR('',#1609,1.);
#1611=CARTESIAN_POINT('',(29.55,2.,6.88397459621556));
#1612=LINE('',#1611,#1610);
#1613=EDGE_CURVE('E412',#197,#1098,#1612,.T.);
#1614=ORIENTED_EDGE('',*,*,#1613,.F.);
#1615=ORIENTED_EDGE('',*,*,#200,.T.);
#1616=DIRECTION('',(0.,0.,-1.));
#1617=VECTOR('',#1616,1.);
#1618=CARTESIAN_POINT('',(29.55,2.7,0.));
#1619=LINE('',#1618,#1617);
#1620=EDGE_CURVE('E885',#199,#329,#1619,.T.);
#1621=ORIENTED_EDGE('',*,*,#1620,.T.);
#1622=ORIENTED_EDGE('',*,*,#330,.T.);
#1623=DIRECTION('',(0.,-1.,0.));
#1624=VECTOR('',#1623,1.);
#1625=CARTESIAN_POINT('',(29.55,2.,-6.88397459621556));
#1626=LINE('',#1625,#1624);
#1627=EDGE_CURVE('E1187',#320,#1167,#1626,.T.);
#1628=ORIENTED_EDGE('',*,*,#1627,.T.);
#1629=ORIENTED_EDGE('',*,*,#1168,.T.);
#1630=DIRECTION('',(0.,-1.,0.));
#1631=VECTOR('',#1630,1.);
#1632=CARTESIAN_POINT('',(29.55,0.,-6.05));
#1633=LINE('',#1632,#1631);
#1634=CARTESIAN_POINT('',(29.55,2.3,-6.05));
#1635=VERTEX_POINT('',#1634);
#1636=EDGE_CURVE('E833',#1635,#1163,#1633,.T.);
#1637=ORIENTED_EDGE('',*,*,#1636,.F.);
#1638=DIRECTION('',(0.,0.,-1.));
#1639=VECTOR('',#1638,1.);
#1640=CARTESIAN_POINT('',(29.55,2.3,6.05));
#1641=LINE('',#1640,#1639);
#1642=CARTESIAN_POINT('',(29.55,2.3,6.05));
#1643=VERTEX_POINT('',#1642);
#1644=EDGE_CURVE('E842',#1643,#1635,#1641,.T.);
#1645=ORIENTED_EDGE('',*,*,#1644,.F.);
#1646=DIRECTION('',(0.,1.,0.));
#1647=VECTOR('',#1646,1.);
#1648=CARTESIAN_POINT('',(29.55,0.,6.05));
#1649=LINE('',#1648,#1647);
#1650=EDGE_CURVE('E1201',#1106,#1643,#1649,.T.);
#1651=ORIENTED_EDGE('',*,*,#1650,.F.);
#1652=EDGE_LOOP('',(#1608,#1614,#1615,#1621,#1622,#1628,#1629,#1637,#1645,#1651));
#1653=FACE_BOUND('',#1652,.T.);
#1654=ADVANCED_FACE('F472',(#1653),#1607,.F.);
#1655=CARTESIAN_POINT('',(0.,2.7,0.));
#1656=DIRECTION('',(0.,1.,0.));
#1657=DIRECTION('',(0.,0.,1.));
#1658=AXIS2_PLACEMENT_3D('',#1655,#1656,#1657);
#1659=PLANE('',#1658);
#1660=ORIENTED_EDGE('',*,*,#174,.F.);
#1661=ORIENTED_EDGE('',*,*,#408,.F.);
#1662=ORIENTED_EDGE('',*,*,#51,.F.);
#1663=ORIENTED_EDGE('',*,*,#336,.F.);
#1664=ORIENTED_EDGE('',*,*,#1620,.F.);
#1665=ORIENTED_EDGE('',*,*,#260,.F.);
#1666=EDGE_LOOP('',(#1660,#1661,#1662,#1663,#1664,#1665));
#1667=FACE_BOUND('',#1666,.T.);
#1668=ADVANCED_FACE('F1196',(#1667),#1659,.F.);
#1669=CARTESIAN_POINT('',(-8.851,0.,6.05));
#1670=DIRECTION('',(0.,0.,1.));
#1671=DIRECTION('',(1.,0.,0.));
#1672=AXIS2_PLACEMENT_3D('',#1669,#1670,#1671);
#1673=PLANE('',#1672);
#1674=ORIENTED_EDGE('',*,*,#1650,.T.);
#1675=DIRECTION('',(1.,0.,0.));
#1676=VECTOR('',#1675,1.);
#1677=CARTESIAN_POINT('',(-8.851,2.3,6.05));
#1678=LINE('',#1677,#1676);
#1679=EDGE_CURVE('E857',#1643,#873,#1678,.T.);
#1680=ORIENTED_EDGE('',*,*,#1679,.T.);
#1681=ORIENTED_EDGE('',*,*,#876,.T.);
#1682=ORIENTED_EDGE('',*,*,#1113,.F.);
#1683=EDGE_LOOP('',(#1674,#1680,#1681,#1682));
#1684=FACE_BOUND('',#1683,.T.);
#1685=ADVANCED_FACE('F764',(#1684),#1673,.F.);
#1686=CARTESIAN_POINT('',(-8.851,2.3,6.05));
#1687=DIRECTION('',(0.,1.,0.));
#1688=DIRECTION('',(0.,0.,1.));
#1689=AXIS2_PLACEMENT_3D('',#1686,#1687,#1688);
#1690=PLANE('',#1689);
#1691=ORIENTED_EDGE('',*,*,#1644,.T.);
#1692=DIRECTION('',(1.,0.,0.));
#1693=VECTOR('',#1692,1.);
#1694=CARTESIAN_POINT('',(-8.851,2.3,-6.05));
#1695=LINE('',#1694,#1693);
#1696=EDGE_CURVE('E838',#1635,#883,#1695,.T.);
#1697=ORIENTED_EDGE('',*,*,#1696,.T.);
#1698=ORIENTED_EDGE('',*,*,#884,.T.);
#1699=ORIENTED_EDGE('',*,*,#1679,.F.);
#1700=EDGE_LOOP('',(#1691,#1697,#1698,#1699));
#1701=FACE_BOUND('',#1700,.T.);
#1702=ADVANCED_FACE('F823',(#1701),#1690,.F.);
#1703=CARTESIAN_POINT('',(-8.851,0.,-6.05));
#1704=DIRECTION('',(0.,0.,-1.));
#1705=DIRECTION('',(-1.,0.,0.));
#1706=AXIS2_PLACEMENT_3D('',#1703,#1704,#1705);
#1707=PLANE('',#1706);
#1708=ORIENTED_EDGE('',*,*,#1636,.T.);
#1709=ORIENTED_EDGE('',*,*,#1164,.T.);
#1710=ORIENTED_EDGE('',*,*,#892,.T.);
#1711=ORIENTED_EDGE('',*,*,#1696,.F.);
#1712=EDGE_LOOP('',(#1708,#1709,#1710,#1711));
#1713=FACE_BOUND('',#1712,.T.);
#1714=ADVANCED_FACE('F821',(#1713),#1707,.F.);
#1715=CARTESIAN_POINT('',(0.,0.,0.));
#1716=DIRECTION('',(0.,1.,0.));
#1717=DIRECTION('',(0.,0.,1.));
#1718=AXIS2_PLACEMENT_3D('',#1715,#1716,#1717);
#1719=CYLINDRICAL_SURFACE('',#1718,7.45);
#1720=DIRECTION('',(0.,1.,0.));
#1721=VECTOR('',#1720,1.);
#1722=CARTESIAN_POINT('',(-7.17110615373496,0.,2.01934061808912));
#1723=LINE('',#1722,#1721);
#1724=CARTESIAN_POINT('',(-7.17110615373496,1.1,2.01934061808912));
#1725=VERTEX_POINT('',#1724);
#1726=EDGE_CURVE('E843',#1194,#1725,#1723,.T.);
#1727=ORIENTED_EDGE('',*,*,#1726,.T.);
#1728=CARTESIAN_POINT('',(0.,1.1,0.));
#1729=DIRECTION('',(0.,-1.,0.));
#1730=DIRECTION('',(0.,0.,-1.));
#1731=AXIS2_PLACEMENT_3D('',#1728,#1729,#1730);
#1732=CIRCLE('',#1731,7.45);
#1733=CARTESIAN_POINT('',(-5.80316544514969,1.1,4.67180594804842));
#1734=VERTEX_POINT('',#1733);
#1735=EDGE_CURVE('E601',#1725,#1734,#1732,.F.);
#1736=ORIENTED_EDGE('',*,*,#1735,.T.);
#1737=DIRECTION('',(0.,1.,0.));
#1738=VECTOR('',#1737,1.);
#1739=CARTESIAN_POINT('',(-5.80316544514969,0.,4.67180594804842));
#1740=LINE('',#1739,#1738);
#1741=EDGE_CURVE('E1220',#1203,#1734,#1740,.T.);
#1742=ORIENTED_EDGE('',*,*,#1741,.F.);
#1743=ORIENTED_EDGE('',*,*,#1204,.F.);
#1744=EDGE_LOOP('',(#1727,#1736,#1742,#1743));
#1745=FACE_BOUND('',#1744,.T.);
#1746=ADVANCED_FACE('F810',(#1745),#1719,.F.);
#1747=CARTESIAN_POINT('',(-7.17110615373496,0.,2.01934061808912));
#1748=DIRECTION('',(-0.0833518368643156,0.,-0.9965201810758));
#1749=DIRECTION('',(-0.9965201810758,0.,0.0833518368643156));
#1750=AXIS2_PLACEMENT_3D('',#1747,#1748,#1749);
#1751=PLANE('',#1750);
#1752=DIRECTION('',(0.,1.,0.));
#1753=VECTOR('',#1752,1.);
#1754=CARTESIAN_POINT('',(-5.26746352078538,0.,1.86011442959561));
#1755=LINE('',#1754,#1753);
#1756=CARTESIAN_POINT('',(-5.26746352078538,1.1,1.86011442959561));
#1757=VERTEX_POINT('',#1756);
#1758=EDGE_CURVE('E1229',#1192,#1757,#1755,.T.);
#1759=ORIENTED_EDGE('',*,*,#1758,.T.);
#1760=DIRECTION('',(-0.9965201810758,0.,0.0833518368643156));
#1761=VECTOR('',#1760,1.);
#1762=CARTESIAN_POINT('',(-7.17110615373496,1.1,2.01934061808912));
#1763=LINE('',#1762,#1761);
#1764=EDGE_CURVE('E604',#1757,#1725,#1763,.T.);
#1765=ORIENTED_EDGE('',*,*,#1764,.T.);
#1766=ORIENTED_EDGE('',*,*,#1726,.F.);
#1767=ORIENTED_EDGE('',*,*,#1195,.F.);
#1768=EDGE_LOOP('',(#1759,#1765,#1766,#1767));
#1769=FACE_BOUND('',#1768,.T.);
#1770=ADVANCED_FACE('F805',(#1769),#1751,.F.);
#1771=CARTESIAN_POINT('',(-5.19879036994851,0.,2.68114229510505));
#1772=DIRECTION('',(0.,1.,0.));
#1773=DIRECTION('',(0.,0.,1.));
#1774=AXIS2_PLACEMENT_3D('',#1771,#1772,#1773);
#1775=CYLINDRICAL_SURFACE('',#1774,0.823894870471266);
#1776=DIRECTION('',(0.,1.,0.));
#1777=VECTOR('',#1776,1.);
#1778=CARTESIAN_POINT('',(-4.56967674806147,0.,3.21313741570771));
#1779=LINE('',#1778,#1777);
#1780=CARTESIAN_POINT('',(-4.56967674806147,1.1,3.21313741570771));
#1781=VERTEX_POINT('',#1780);
#1782=EDGE_CURVE('E1224',#1211,#1781,#1779,.T.);
#1783=ORIENTED_EDGE('',*,*,#1782,.T.);
#1784=CARTESIAN_POINT('',(-5.19879036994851,1.1,2.68114229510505));
#1785=DIRECTION('',(0.,-1.,0.));
#1786=DIRECTION('',(0.,0.,-1.));
#1787=AXIS2_PLACEMENT_3D('',#1784,#1785,#1786);
#1788=CIRCLE('',#1787,0.823894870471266);
#1789=EDGE_CURVE('E719',#1781,#1757,#1788,.F.);
#1790=ORIENTED_EDGE('',*,*,#1789,.T.);
#1791=ORIENTED_EDGE('',*,*,#1758,.F.);
#1792=ORIENTED_EDGE('',*,*,#1219,.F.);
#1793=EDGE_LOOP('',(#1783,#1790,#1791,#1792));
#1794=FACE_BOUND('',#1793,.T.);
#1795=ADVANCED_FACE('F809',(#1794),#1775,.F.);
#1796=CARTESIAN_POINT('',(-4.56967674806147,0.,3.21313741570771));
#1797=DIRECTION('',(0.763584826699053,0.,0.645707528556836));
#1798=DIRECTION('',(0.645707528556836,0.,-0.763584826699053));
#1799=AXIS2_PLACEMENT_3D('',#1796,#1797,#1798);
#1800=PLANE('',#1799);
#1801=ORIENTED_EDGE('',*,*,#1741,.T.);
#1802=DIRECTION('',(0.645707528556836,0.,-0.763584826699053));
#1803=VECTOR('',#1802,1.);
#1804=CARTESIAN_POINT('',(-4.56967674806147,1.1,3.21313741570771));
#1805=LINE('',#1804,#1803);
#1806=EDGE_CURVE('E1256',#1734,#1781,#1805,.T.);
#1807=ORIENTED_EDGE('',*,*,#1806,.T.);
#1808=ORIENTED_EDGE('',*,*,#1782,.F.);
#1809=ORIENTED_EDGE('',*,*,#1212,.F.);
#1810=EDGE_LOOP('',(#1801,#1807,#1808,#1809));
#1811=FACE_BOUND('',#1810,.T.);
#1812=ADVANCED_FACE('F814',(#1811),#1800,.F.);
#1813=CARTESIAN_POINT('',(0.,0.5,0.));
#1814=DIRECTION('',(0.,-1.,0.));
#1815=DIRECTION('',(0.,0.,-1.));
#1816=AXIS2_PLACEMENT_3D('',#1813,#1814,#1815);
#1817=PLANE('',#1816);
#1818=CARTESIAN_POINT('',(-7.90275733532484,0.5,0.111396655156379));
#1819=DIRECTION('',(0.,-1.,0.));
#1820=DIRECTION('',(0.,0.,-1.));
#1821=AXIS2_PLACEMENT_3D('',#1818,#1819,#1820);
#1822=CIRCLE('',#1821,1.);
#1823=CARTESIAN_POINT('',(-8.10362202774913,0.5,-0.868222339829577));
#1824=VERTEX_POINT('',#1823);
#1825=CARTESIAN_POINT('',(-6.92720998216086,0.5,-0.108392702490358));
#1826=VERTEX_POINT('',#1825);
#1827=EDGE_CURVE('E1159',#1824,#1826,#1822,.T.);
#1828=ORIENTED_EDGE('',*,*,#1827,.F.);
#1829=CARTESIAN_POINT('',(0.,0.5,0.));
#1830=DIRECTION('',(0.,-1.,0.));
#1831=DIRECTION('',(0.,0.,-1.));
#1832=AXIS2_PLACEMENT_3D('',#1829,#1830,#1831);
#1833=CIRCLE('',#1832,8.15);
#1834=CARTESIAN_POINT('',(0.,0.5,-8.15));
#1835=VERTEX_POINT('',#1834);
#1836=EDGE_CURVE('E1133',#1824,#1835,#1833,.T.);
#1837=ORIENTED_EDGE('',*,*,#1836,.T.);
#1838=DIRECTION('',(1.,0.,0.));
#1839=VECTOR('',#1838,1.);
#1840=CARTESIAN_POINT('',(0.,0.5,-8.15));
#1841=LINE('',#1840,#1839);
#1842=CARTESIAN_POINT('',(28.1334848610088,0.5,-8.15));
#1843=VERTEX_POINT('',#1842);
#1844=EDGE_CURVE('E1075',#1835,#1843,#1841,.T.);
#1845=ORIENTED_EDGE('',*,*,#1844,.T.);
#1846=CARTESIAN_POINT('',(29.05,0.5,-7.75));
#1847=DIRECTION('',(0.,-1.,0.));
#1848=DIRECTION('',(0.,0.,-1.));
#1849=AXIS2_PLACEMENT_3D('',#1846,#1847,#1848);
#1850=CIRCLE('',#1849,1.);
#1851=EDGE_CURVE('E460',#275,#1843,#1850,.T.);
#1852=ORIENTED_EDGE('',*,*,#1851,.F.);
#1853=ORIENTED_EDGE('',*,*,#276,.T.);
#1854=ORIENTED_EDGE('',*,*,#33,.T.);
#1855=ORIENTED_EDGE('',*,*,#353,.T.);
#1856=ORIENTED_EDGE('',*,*,#399,.F.);
#1857=ORIENTED_EDGE('',*,*,#376,.T.);
#1858=ORIENTED_EDGE('',*,*,#117,.T.);
#1859=ORIENTED_EDGE('',*,*,#253,.T.);
#1860=CARTESIAN_POINT('',(29.05,0.5,7.75));
#1861=DIRECTION('',(0.,-1.,0.));
#1862=DIRECTION('',(0.,0.,-1.));
#1863=AXIS2_PLACEMENT_3D('',#1860,#1861,#1862);
#1864=CIRCLE('',#1863,1.);
#1865=CARTESIAN_POINT('',(28.1334848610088,0.5,8.15));
#1866=VERTEX_POINT('',#1865);
#1867=EDGE_CURVE('E414',#1866,#246,#1864,.T.);
#1868=ORIENTED_EDGE('',*,*,#1867,.F.);
#1869=DIRECTION('',(-1.,0.,0.));
#1870=VECTOR('',#1869,1.);
#1871=CARTESIAN_POINT('',(29.55,0.5,8.15));
#1872=LINE('',#1871,#1870);
#1873=CARTESIAN_POINT('',(0.,0.5,8.15));
#1874=VERTEX_POINT('',#1873);
#1875=EDGE_CURVE('E402',#1866,#1874,#1872,.T.);
#1876=ORIENTED_EDGE('',*,*,#1875,.T.);
#1877=CARTESIAN_POINT('',(0.,0.5,0.));
#1878=DIRECTION('',(0.,-1.,0.));
#1879=DIRECTION('',(0.,0.,-1.));
#1880=AXIS2_PLACEMENT_3D('',#1877,#1878,#1879);
#1881=CIRCLE('',#1880,8.15);
#1882=CARTESIAN_POINT('',(-3.99121369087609,0.5,7.10582249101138));
#1883=VERTEX_POINT('',#1882);
#1884=EDGE_CURVE('E1057',#1874,#1883,#1881,.T.);
#1885=ORIENTED_EDGE('',*,*,#1884,.T.);
#1886=CARTESIAN_POINT('',(-4.67289265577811,0.5,6.37417107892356));
#1887=DIRECTION('',(0.,-1.,0.));
#1888=DIRECTION('',(0.,0.,-1.));
#1889=AXIS2_PLACEMENT_3D('',#1886,#1887,#1888);
#1890=CIRCLE('',#1889,0.999999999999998);
#1891=CARTESIAN_POINT('',(-3.9281831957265,0.5,5.70678227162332));
#1892=VERTEX_POINT('',#1891);
#1893=EDGE_CURVE('E420',#1892,#1883,#1890,.T.);
#1894=ORIENTED_EDGE('',*,*,#1893,.F.);
#1895=DIRECTION('',(0.645707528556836,0.,-0.763584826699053));
#1896=VECTOR('',#1895,1.);
#1897=CARTESIAN_POINT('',(-4.7205035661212,0.5,6.64374488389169));
#1898=LINE('',#1897,#1896);
#1899=CARTESIAN_POINT('',(-3.24067464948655,0.5,4.89376543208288));
#1900=VERTEX_POINT('',#1899);
#1901=EDGE_CURVE('E1121',#1892,#1900,#1898,.T.);
#1902=ORIENTED_EDGE('',*,*,#1901,.T.);
#1903=CARTESIAN_POINT('',(-5.60778761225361,0.5,2.89207209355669));
#1904=DIRECTION('',(0.,1.,0.));
#1905=DIRECTION('',(0.,0.,-1.));
#1906=AXIS2_PLACEMENT_3D('',#1903,#1904,#1905);
#1907=CIRCLE('',#1906,3.1);
#1908=CARTESIAN_POINT('',(-5.86617830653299,0.5,-0.197140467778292));
#1909=VERTEX_POINT('',#1908);
#1910=EDGE_CURVE('E1123',#1900,#1909,#1907,.T.);
#1911=ORIENTED_EDGE('',*,*,#1910,.T.);
#1912=DIRECTION('',(-0.9965201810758,0.,0.0833518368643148));
#1913=VECTOR('',#1912,1.);
#1914=CARTESIAN_POINT('',(-5.86617830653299,0.5,-0.197140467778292));
#1915=LINE('',#1914,#1913);
#1916=EDGE_CURVE('E1129',#1909,#1826,#1915,.T.);
#1917=ORIENTED_EDGE('',*,*,#1916,.T.);
#1918=EDGE_LOOP('',(#1828,#1837,#1845,#1852,#1853,#1854,#1855,#1856,#1857,#1858,#1859,#1868,
#1876,#1885,#1894,#1902,#1911,#1917));
#1919=FACE_BOUND('',#1918,.T.);
#1920=ADVANCED_FACE('F449',(#1919),#1817,.T.);
#1921=CARTESIAN_POINT('',(0.,0.5,-8.15));
#1922=DIRECTION('',(0.,0.,-1.));
#1923=DIRECTION('',(-1.,0.,0.));
#1924=AXIS2_PLACEMENT_3D('',#1921,#1922,#1923);
#1925=PLANE('',#1924);
#1926=ORIENTED_EDGE('',*,*,#1183,.T.);
#1927=DIRECTION('',(0.,-1.,0.));
#1928=VECTOR('',#1927,1.);
#1929=CARTESIAN_POINT('',(28.1334848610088,2.,-8.15));
#1930=LINE('',#1929,#1928);
#1931=EDGE_CURVE('E407',#1176,#1843,#1930,.F.);
#1932=ORIENTED_EDGE('',*,*,#1931,.T.);
#1933=ORIENTED_EDGE('',*,*,#1844,.F.);
#1934=DIRECTION('',(0.,-1.,0.));
#1935=VECTOR('',#1934,1.);
#1936=CARTESIAN_POINT('',(0.,0.5,-8.15));
#1937=LINE('',#1936,#1935);
#1938=EDGE_CURVE('E1051',#1835,#1029,#1937,.T.);
#1939=ORIENTED_EDGE('',*,*,#1938,.T.);
#1940=EDGE_LOOP('',(#1926,#1932,#1933,#1939));
#1941=FACE_BOUND('',#1940,.T.);
#1942=ADVANCED_FACE('F1035',(#1941),#1925,.F.);
#1943=CARTESIAN_POINT('',(0.,0.5,0.));
#1944=DIRECTION('',(0.,-1.,0.));
#1945=DIRECTION('',(0.,0.,-1.));
#1946=AXIS2_PLACEMENT_3D('',#1943,#1944,#1945);
#1947=CYLINDRICAL_SURFACE('',#1946,8.15);
#1948=ORIENTED_EDGE('',*,*,#1836,.F.);
#1949=DIRECTION('',(0.,-1.,0.));
#1950=VECTOR('',#1949,1.);
#1951=CARTESIAN_POINT('',(-8.10362202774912,2.,-0.868222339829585));
#1952=LINE('',#1951,#1950);
#1953=EDGE_CURVE('E640',#1824,#1027,#1952,.T.);
#1954=ORIENTED_EDGE('',*,*,#1953,.T.);
#1955=ORIENTED_EDGE('',*,*,#1030,.T.);
#1956=ORIENTED_EDGE('',*,*,#1938,.F.);
#1957=EDGE_LOOP('',(#1948,#1954,#1955,#1956));
#1958=FACE_BOUND('',#1957,.T.);
#1959=ADVANCED_FACE('F1032',(#1958),#1947,.F.);
#1960=CARTESIAN_POINT('',(-5.86617830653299,0.5,-0.197140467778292));
#1961=DIRECTION('',(0.0833518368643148,0.,0.9965201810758));
#1962=DIRECTION('',(0.9965201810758,0.,-0.0833518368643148));
#1963=AXIS2_PLACEMENT_3D('',#1960,#1961,#1962);
#1964=PLANE('',#1963);
#1965=ORIENTED_EDGE('',*,*,#1047,.T.);
#1966=DIRECTION('',(0.,-1.,0.));
#1967=VECTOR('',#1966,1.);
#1968=CARTESIAN_POINT('',(-6.92720998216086,2.,-0.108392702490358));
#1969=LINE('',#1968,#1967);
#1970=EDGE_CURVE('E1150',#1038,#1826,#1969,.F.);
#1971=ORIENTED_EDGE('',*,*,#1970,.T.);
#1972=ORIENTED_EDGE('',*,*,#1916,.F.);
#1973=DIRECTION('',(0.,-1.,0.));
#1974=VECTOR('',#1973,1.);
#1975=CARTESIAN_POINT('',(-5.86617830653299,0.5,-0.197140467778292));
#1976=LINE('',#1975,#1974);
#1977=EDGE_CURVE('E1065',#1909,#1046,#1976,.T.);
#1978=ORIENTED_EDGE('',*,*,#1977,.T.);
#1979=EDGE_LOOP('',(#1965,#1971,#1972,#1978));
#1980=FACE_BOUND('',#1979,.T.);
#1981=ADVANCED_FACE('F1028',(#1980),#1964,.F.);
#1982=CARTESIAN_POINT('',(-5.60778761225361,0.5,2.89207209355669));
#1983=DIRECTION('',(0.,-1.,0.));
#1984=DIRECTION('',(0.,0.,-1.));
#1985=AXIS2_PLACEMENT_3D('',#1982,#1983,#1984);
#1986=CYLINDRICAL_SURFACE('',#1985,3.1);
#1987=ORIENTED_EDGE('',*,*,#1056,.T.);
#1988=ORIENTED_EDGE('',*,*,#1977,.F.);
#1989=ORIENTED_EDGE('',*,*,#1910,.F.);
#1990=DIRECTION('',(0.,-1.,0.));
#1991=VECTOR('',#1990,1.);
#1992=CARTESIAN_POINT('',(-3.24067464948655,0.5,4.89376543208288));
#1993=LINE('',#1992,#1991);
#1994=EDGE_CURVE('E1068',#1900,#1055,#1993,.T.);
#1995=ORIENTED_EDGE('',*,*,#1994,.T.);
#1996=EDGE_LOOP('',(#1987,#1988,#1989,#1995));
#1997=FACE_BOUND('',#1996,.T.);
#1998=ADVANCED_FACE('F1024',(#1997),#1986,.T.);
#1999=CARTESIAN_POINT('',(-4.7205035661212,0.5,6.64374488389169));
#2000=DIRECTION('',(-0.763584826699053,0.,-0.645707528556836));
#2001=DIRECTION('',(-0.645707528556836,0.,0.763584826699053));
#2002=AXIS2_PLACEMENT_3D('',#1999,#2000,#2001);
#2003=PLANE('',#2002);
#2004=ORIENTED_EDGE('',*,*,#1901,.F.);
#2005=DIRECTION('',(0.,-1.,0.));
#2006=VECTOR('',#2005,1.);
#2007=CARTESIAN_POINT('',(-3.9281831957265,2.,5.70678227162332));
#2008=LINE('',#2007,#2006);
#2009=EDGE_CURVE('E1167',#1892,#1063,#2008,.T.);
#2010=ORIENTED_EDGE('',*,*,#2009,.T.);
#2011=ORIENTED_EDGE('',*,*,#1064,.T.);
#2012=ORIENTED_EDGE('',*,*,#1994,.F.);
#2013=EDGE_LOOP('',(#2004,#2010,#2011,#2012));
#2014=FACE_BOUND('',#2013,.T.);
#2015=ADVANCED_FACE('F1020',(#2014),#2003,.F.);
#2016=CARTESIAN_POINT('',(0.,0.5,0.));
#2017=DIRECTION('',(0.,-1.,0.));
#2018=DIRECTION('',(0.,0.,-1.));
#2019=AXIS2_PLACEMENT_3D('',#2016,#2017,#2018);
#2020=CYLINDRICAL_SURFACE('',#2019,8.15);
#2021=ORIENTED_EDGE('',*,*,#1082,.T.);
#2022=DIRECTION('',(0.,-1.,0.));
#2023=VECTOR('',#2022,1.);
#2024=CARTESIAN_POINT('',(-3.99121369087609,1.,7.10582249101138));
#2025=LINE('',#2024,#2023);
#2026=EDGE_CURVE('E406',#1072,#1883,#2025,.F.);
#2027=ORIENTED_EDGE('',*,*,#2026,.T.);
#2028=ORIENTED_EDGE('',*,*,#1884,.F.);
#2029=DIRECTION('',(0.,-1.,0.));
#2030=VECTOR('',#2029,1.);
#2031=CARTESIAN_POINT('',(0.,0.5,8.15));
#2032=LINE('',#2031,#2030);
#2033=EDGE_CURVE('E1072',#1874,#1081,#2032,.T.);
#2034=ORIENTED_EDGE('',*,*,#2033,.T.);
#2035=EDGE_LOOP('',(#2021,#2027,#2028,#2034));
#2036=FACE_BOUND('',#2035,.T.);
#2037=ADVANCED_FACE('F1017',(#2036),#2020,.F.);
#2038=CARTESIAN_POINT('',(29.55,0.5,8.15));
#2039=DIRECTION('',(0.,0.,1.));
#2040=DIRECTION('',(1.,0.,0.));
#2041=AXIS2_PLACEMENT_3D('',#2038,#2039,#2040);
#2042=PLANE('',#2041);
#2043=ORIENTED_EDGE('',*,*,#1875,.F.);
#2044=DIRECTION('',(0.,-1.,0.));
#2045=VECTOR('',#2044,1.);
#2046=CARTESIAN_POINT('',(28.1334848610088,2.,8.15));
#2047=LINE('',#2046,#2045);
#2048=EDGE_CURVE('E400',#1866,#1089,#2047,.T.);
#2049=ORIENTED_EDGE('',*,*,#2048,.T.);
#2050=ORIENTED_EDGE('',*,*,#1090,.T.);
#2051=ORIENTED_EDGE('',*,*,#2033,.F.);
#2052=EDGE_LOOP('',(#2043,#2049,#2050,#2051));
#2053=FACE_BOUND('',#2052,.T.);
#2054=ADVANCED_FACE('F401',(#2053),#2042,.F.);
#2055=CARTESIAN_POINT('',(29.05,2.,-7.75));
#2056=DIRECTION('',(0.,-1.,0.));
#2057=DIRECTION('',(0.,0.,-1.));
#2058=AXIS2_PLACEMENT_3D('',#2055,#2056,#2057);
#2059=CYLINDRICAL_SURFACE('',#2058,1.);
#2060=ORIENTED_EDGE('',*,*,#321,.F.);
#2061=ORIENTED_EDGE('',*,*,#1851,.T.);
#2062=ORIENTED_EDGE('',*,*,#1931,.F.);
#2063=ORIENTED_EDGE('',*,*,#1177,.F.);
#2064=ORIENTED_EDGE('',*,*,#1627,.F.);
#2065=EDGE_LOOP('',(#2060,#2061,#2062,#2063,#2064));
#2066=FACE_BOUND('',#2065,.T.);
#2067=ADVANCED_FACE('F443',(#2066),#2059,.T.);
#2068=CARTESIAN_POINT('',(29.05,2.,7.75));
#2069=DIRECTION('',(0.,-1.,0.));
#2070=DIRECTION('',(0.,0.,-1.));
#2071=AXIS2_PLACEMENT_3D('',#2068,#2069,#2070);
#2072=CYLINDRICAL_SURFACE('',#2071,1.);
#2073=ORIENTED_EDGE('',*,*,#247,.F.);
#2074=ORIENTED_EDGE('',*,*,#1613,.T.);
#2075=ORIENTED_EDGE('',*,*,#1099,.F.);
#2076=ORIENTED_EDGE('',*,*,#2048,.F.);
#2077=ORIENTED_EDGE('',*,*,#1867,.T.);
#2078=EDGE_LOOP('',(#2073,#2074,#2075,#2076,#2077));
#2079=FACE_BOUND('',#2078,.T.);
#2080=ADVANCED_FACE('F411',(#2079),#2072,.T.);
#2081=CARTESIAN_POINT('',(-4.67289265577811,2.,6.37417107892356));
#2082=DIRECTION('',(0.,-1.,0.));
#2083=DIRECTION('',(0.,0.,-1.));
#2084=AXIS2_PLACEMENT_3D('',#2081,#2082,#2083);
#2085=CYLINDRICAL_SURFACE('',#2084,0.999999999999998);
#2086=ORIENTED_EDGE('',*,*,#2009,.F.);
#2087=ORIENTED_EDGE('',*,*,#1893,.T.);
#2088=ORIENTED_EDGE('',*,*,#2026,.F.);
#2089=ORIENTED_EDGE('',*,*,#1073,.F.);
#2090=EDGE_LOOP('',(#2086,#2087,#2088,#2089));
#2091=FACE_BOUND('',#2090,.T.);
#2092=ADVANCED_FACE('F442',(#2091),#2085,.T.);
#2093=CARTESIAN_POINT('',(-7.90275733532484,2.,0.111396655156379));
#2094=DIRECTION('',(0.,-1.,0.));
#2095=DIRECTION('',(0.,0.,-1.));
#2096=AXIS2_PLACEMENT_3D('',#2093,#2094,#2095);
#2097=CYLINDRICAL_SURFACE('',#2096,1.);
#2098=ORIENTED_EDGE('',*,*,#1953,.F.);
#2099=ORIENTED_EDGE('',*,*,#1827,.T.);
#2100=ORIENTED_EDGE('',*,*,#1970,.F.);
#2101=ORIENTED_EDGE('',*,*,#1039,.F.);
#2102=EDGE_LOOP('',(#2098,#2099,#2100,#2101));
#2103=FACE_BOUND('',#2102,.T.);
#2104=ADVANCED_FACE('F1157',(#2103),#2097,.T.);
#2105=CARTESIAN_POINT('',(-7.90275733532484,-1.5,0.111396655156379));
#2106=DIRECTION('',(0.,1.,0.));
#2107=DIRECTION('',(0.,0.,1.));
#2108=AXIS2_PLACEMENT_3D('',#2105,#2106,#2107);
#2109=CYLINDRICAL_SURFACE('',#2108,0.500000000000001);
#2110=CARTESIAN_POINT('',(-7.90275733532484,-1.3,0.111396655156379));
#2111=DIRECTION('',(0.,-1.,0.));
#2112=DIRECTION('',(0.,0.,-1.));
#2113=AXIS2_PLACEMENT_3D('',#2110,#2111,#2112);
#2114=CIRCLE('',#2113,0.500000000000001);
#2115=CARTESIAN_POINT('',(-7.90275733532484,-1.3,-0.388603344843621));
#2116=VERTEX_POINT('',#2115);
#2117=EDGE_CURVE('E1374',#2116,#2116,#2114,.F.);
#2118=ORIENTED_EDGE('',*,*,#2117,.T.);
#2119=EDGE_LOOP('',(#2118));
#2120=FACE_BOUND('',#2119,.T.);
#2121=ORIENTED_EDGE('',*,*,#1017,.T.);
#2122=EDGE_LOOP('',(#2121));
#2123=FACE_BOUND('',#2122,.T.);
#2124=ADVANCED_FACE('F1496',(#2120,#2123),#2109,.T.);
#2125=CARTESIAN_POINT('',(0.,-1.5,0.));
#2126=DIRECTION('',(0.,-1.,0.));
#2127=DIRECTION('',(0.,0.,-1.));
#2128=AXIS2_PLACEMENT_3D('',#2125,#2126,#2127);
#2129=PLANE('',#2128);
#2130=CARTESIAN_POINT('',(-7.90275733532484,-1.5,0.111396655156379));
#2131=DIRECTION('',(0.,-1.,0.));
#2132=DIRECTION('',(0.,0.,-1.));
#2133=AXIS2_PLACEMENT_3D('',#2130,#2131,#2132);
#2134=CIRCLE('',#2133,0.300000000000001);
#2135=CARTESIAN_POINT('',(-7.90275733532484,-1.5,-0.188603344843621));
#2136=VERTEX_POINT('',#2135);
#2137=EDGE_CURVE('E1370',#2136,#2136,#2134,.T.);
#2138=ORIENTED_EDGE('',*,*,#2137,.T.);
#2139=EDGE_LOOP('',(#2138));
#2140=FACE_BOUND('',#2139,.T.);
#2141=ADVANCED_FACE('F1488',(#2140),#2129,.T.);
#2142=CARTESIAN_POINT('',(29.05,-1.5,7.75));
#2143=DIRECTION('',(0.,1.,0.));
#2144=DIRECTION('',(0.,0.,1.));
#2145=AXIS2_PLACEMENT_3D('',#2142,#2143,#2144);
#2146=CYLINDRICAL_SURFACE('',#2145,0.499999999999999);
#2147=CARTESIAN_POINT('',(29.05,-1.3,7.75));
#2148=DIRECTION('',(0.,-1.,0.));
#2149=DIRECTION('',(0.,0.,-1.));
#2150=AXIS2_PLACEMENT_3D('',#2147,#2148,#2149);
#2151=CIRCLE('',#2150,0.499999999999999);
#2152=CARTESIAN_POINT('',(29.05,-1.3,7.25));
#2153=VERTEX_POINT('',#2152);
#2154=EDGE_CURVE('E1390',#2153,#2153,#2151,.F.);
#2155=ORIENTED_EDGE('',*,*,#2154,.T.);
#2156=EDGE_LOOP('',(#2155));
#2157=FACE_BOUND('',#2156,.T.);
#2158=ORIENTED_EDGE('',*,*,#1006,.T.);
#2159=EDGE_LOOP('',(#2158));
#2160=FACE_BOUND('',#2159,.T.);
#2161=ADVANCED_FACE('F1480',(#2157,#2160),#2146,.T.);
#2162=CARTESIAN_POINT('',(0.,-1.5,0.));
#2163=DIRECTION('',(0.,-1.,0.));
#2164=DIRECTION('',(0.,0.,-1.));
#2165=AXIS2_PLACEMENT_3D('',#2162,#2163,#2164);
#2166=PLANE('',#2165);
#2167=CARTESIAN_POINT('',(29.05,-1.5,7.75));
#2168=DIRECTION('',(0.,-1.,0.));
#2169=DIRECTION('',(0.,0.,-1.));
#2170=AXIS2_PLACEMENT_3D('',#2167,#2168,#2169);
#2171=CIRCLE('',#2170,0.299999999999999);
#2172=CARTESIAN_POINT('',(29.05,-1.5,7.45));
#2173=VERTEX_POINT('',#2172);
#2174=EDGE_CURVE('E1386',#2173,#2173,#2171,.T.);
#2175=ORIENTED_EDGE('',*,*,#2174,.T.);
#2176=EDGE_LOOP('',(#2175));
#2177=FACE_BOUND('',#2176,.T.);
#2178=ADVANCED_FACE('F1472',(#2177),#2166,.T.);
#2179=CARTESIAN_POINT('',(29.05,-1.5,-7.75));
#2180=DIRECTION('',(0.,1.,0.));
#2181=DIRECTION('',(0.,0.,1.));
#2182=AXIS2_PLACEMENT_3D('',#2179,#2180,#2181);
#2183=CYLINDRICAL_SURFACE('',#2182,0.499999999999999);
#2184=CARTESIAN_POINT('',(29.05,-1.3,-7.75));
#2185=DIRECTION('',(0.,-1.,0.));
#2186=DIRECTION('',(0.,0.,-1.));
#2187=AXIS2_PLACEMENT_3D('',#2184,#2185,#2186);
#2188=CIRCLE('',#2187,0.499999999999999);
#2189=CARTESIAN_POINT('',(29.05,-1.3,-8.25));
#2190=VERTEX_POINT('',#2189);
#2191=EDGE_CURVE('E1382',#2190,#2190,#2188,.F.);
#2192=ORIENTED_EDGE('',*,*,#2191,.T.);
#2193=EDGE_LOOP('',(#2192));
#2194=FACE_BOUND('',#2193,.T.);
#2195=ORIENTED_EDGE('',*,*,#995,.T.);
#2196=EDGE_LOOP('',(#2195));
#2197=FACE_BOUND('',#2196,.T.);
#2198=ADVANCED_FACE('F1464',(#2194,#2197),#2183,.T.);
#2199=CARTESIAN_POINT('',(0.,-1.5,0.));
#2200=DIRECTION('',(0.,-1.,0.));
#2201=DIRECTION('',(0.,0.,-1.));
#2202=AXIS2_PLACEMENT_3D('',#2199,#2200,#2201);
#2203=PLANE('',#2202);
#2204=CARTESIAN_POINT('',(29.05,-1.5,-7.75));
#2205=DIRECTION('',(0.,-1.,0.));
#2206=DIRECTION('',(0.,0.,-1.));
#2207=AXIS2_PLACEMENT_3D('',#2204,#2205,#2206);
#2208=CIRCLE('',#2207,0.299999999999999);
#2209=CARTESIAN_POINT('',(29.05,-1.5,-8.05));
#2210=VERTEX_POINT('',#2209);
#2211=EDGE_CURVE('E1378',#2210,#2210,#2208,.T.);
#2212=ORIENTED_EDGE('',*,*,#2211,.T.);
#2213=EDGE_LOOP('',(#2212));
#2214=FACE_BOUND('',#2213,.T.);
#2215=ADVANCED_FACE('F1456',(#2214),#2203,.T.);
#2216=CARTESIAN_POINT('',(-4.67289265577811,-1.5,6.37417107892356));
#2217=DIRECTION('',(0.,1.,0.));
#2218=DIRECTION('',(0.,0.,1.));
#2219=AXIS2_PLACEMENT_3D('',#2216,#2217,#2218);
#2220=CYLINDRICAL_SURFACE('',#2219,0.500000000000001);
#2221=CARTESIAN_POINT('',(-4.67289265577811,-1.3,6.37417107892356));
#2222=DIRECTION('',(0.,-1.,0.));
#2223=DIRECTION('',(0.,0.,-1.));
#2224=AXIS2_PLACEMENT_3D('',#2221,#2222,#2223);
#2225=CIRCLE('',#2224,0.500000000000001);
#2226=CARTESIAN_POINT('',(-4.67289265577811,-1.3,5.87417107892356));
#2227=VERTEX_POINT('',#2226);
#2228=EDGE_CURVE('E1366',#2227,#2227,#2225,.F.);
#2229=ORIENTED_EDGE('',*,*,#2228,.T.);
#2230=EDGE_LOOP('',(#2229));
#2231=FACE_BOUND('',#2230,.T.);
#2232=ORIENTED_EDGE('',*,*,#984,.T.);
#2233=EDGE_LOOP('',(#2232));
#2234=FACE_BOUND('',#2233,.T.);
#2235=ADVANCED_FACE('F1448',(#2231,#2234),#2220,.T.);
#2236=CARTESIAN_POINT('',(-4.67289265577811,-1.5,6.37417107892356));
#2237=DIRECTION('',(0.,-1.,0.));
#2238=DIRECTION('',(0.,0.,-1.));
#2239=AXIS2_PLACEMENT_3D('',#2236,#2237,#2238);
#2240=PLANE('',#2239);
#2241=CARTESIAN_POINT('',(-4.67289265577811,-1.5,6.37417107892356));
#2242=DIRECTION('',(0.,-1.,0.));
#2243=DIRECTION('',(0.,0.,-1.));
#2244=AXIS2_PLACEMENT_3D('',#2241,#2242,#2243);
#2245=CIRCLE('',#2244,0.300000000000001);
#2246=CARTESIAN_POINT('',(-4.67289265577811,-1.5,6.07417107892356));
#2247=VERTEX_POINT('',#2246);
#2248=EDGE_CURVE('E1362',#2247,#2247,#2245,.T.);
#2249=ORIENTED_EDGE('',*,*,#2248,.T.);
#2250=EDGE_LOOP('',(#2249));
#2251=FACE_BOUND('',#2250,.T.);
#2252=ADVANCED_FACE('F736',(#2251),#2240,.T.);
#2253=CARTESIAN_POINT('',(-4.67289265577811,-1.3,6.37417107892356));
#2254=DIRECTION('',(0.,-1.,0.));
#2255=DIRECTION('',(0.,0.,-1.));
#2256=AXIS2_PLACEMENT_3D('',#2253,#2254,#2255);
#2257=TOROIDAL_SURFACE('',#2256,0.300000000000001,0.2);
#2258=ORIENTED_EDGE('',*,*,#2228,.F.);
#2259=EDGE_LOOP('',(#2258));
#2260=FACE_BOUND('',#2259,.T.);
#2261=ORIENTED_EDGE('',*,*,#2248,.F.);
#2262=EDGE_LOOP('',(#2261));
#2263=FACE_BOUND('',#2262,.T.);
#2264=ADVANCED_FACE('F733',(#2260,#2263),#2257,.T.);
#2265=CARTESIAN_POINT('',(-7.90275733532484,-1.3,0.111396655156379));
#2266=DIRECTION('',(0.,-1.,0.));
#2267=DIRECTION('',(0.,0.,-1.));
#2268=AXIS2_PLACEMENT_3D('',#2265,#2266,#2267);
#2269=TOROIDAL_SURFACE('',#2268,0.300000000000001,0.2);
#2270=ORIENTED_EDGE('',*,*,#2117,.F.);
#2271=EDGE_LOOP('',(#2270));
#2272=FACE_BOUND('',#2271,.T.);
#2273=ORIENTED_EDGE('',*,*,#2137,.F.);
#2274=EDGE_LOOP('',(#2273));
#2275=FACE_BOUND('',#2274,.T.);
#2276=ADVANCED_FACE('F729',(#2272,#2275),#2269,.T.);
#2277=CARTESIAN_POINT('',(29.05,-1.3,-7.75));
#2278=DIRECTION('',(0.,-1.,0.));
#2279=DIRECTION('',(0.,0.,-1.));
#2280=AXIS2_PLACEMENT_3D('',#2277,#2278,#2279);
#2281=TOROIDAL_SURFACE('',#2280,0.299999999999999,0.2);
#2282=ORIENTED_EDGE('',*,*,#2191,.F.);
#2283=EDGE_LOOP('',(#2282));
#2284=FACE_BOUND('',#2283,.T.);
#2285=ORIENTED_EDGE('',*,*,#2211,.F.);
#2286=EDGE_LOOP('',(#2285));
#2287=FACE_BOUND('',#2286,.T.);
#2288=ADVANCED_FACE('F725',(#2284,#2287),#2281,.T.);
#2289=CARTESIAN_POINT('',(29.05,-1.3,7.75));
#2290=DIRECTION('',(0.,-1.,0.));
#2291=DIRECTION('',(0.,0.,-1.));
#2292=AXIS2_PLACEMENT_3D('',#2289,#2290,#2291);
#2293=TOROIDAL_SURFACE('',#2292,0.299999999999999,0.2);
#2294=ORIENTED_EDGE('',*,*,#2154,.F.);
#2295=EDGE_LOOP('',(#2294));
#2296=FACE_BOUND('',#2295,.T.);
#2297=ORIENTED_EDGE('',*,*,#2174,.F.);
#2298=EDGE_LOOP('',(#2297));
#2299=FACE_BOUND('',#2298,.T.);
#2300=ADVANCED_FACE('F650',(#2296,#2299),#2293,.T.);
#2301=CARTESIAN_POINT('',(-7.18777652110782,1.1,1.82003658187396));
#2302=DIRECTION('',(-0.9965201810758,0.,0.0833518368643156));
#2303=DIRECTION('',(0.0833518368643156,0.,0.9965201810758));
#2304=AXIS2_PLACEMENT_3D('',#2301,#2302,#2303);
#2305=CYLINDRICAL_SURFACE('',#2304,0.2);
#2306=CARTESIAN_POINT('',(-5.28413388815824,1.1,1.66081039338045));
#2307=DIRECTION('',(0.9965201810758,0.,-0.0833518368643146));
#2308=DIRECTION('',(-0.0833518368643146,0.,-0.9965201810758));
#2309=AXIS2_PLACEMENT_3D('',#2306,#2307,#2308);
#2310=CIRCLE('',#2309,0.2);
#2311=EDGE_CURVE('E641',#1538,#1757,#2310,.T.);
#2312=ORIENTED_EDGE('',*,*,#2311,.F.);
#2313=ORIENTED_EDGE('',*,*,#1564,.F.);
#2314=CARTESIAN_POINT('',(-7.17110615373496,1.1,2.01934061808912));
#2315=CARTESIAN_POINT('',(-7.17108577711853,1.10849589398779,2.01935453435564));
#2316=CARTESIAN_POINT('',(-7.17180368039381,1.11696197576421,2.0188568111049));
#2317=CARTESIAN_POINT('',(-7.17453197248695,1.13348774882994,2.01696399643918));
#2318=CARTESIAN_POINT('',(-7.17652808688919,1.14155088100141,2.01557881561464));
#2319=CARTESIAN_POINT('',(-7.18162571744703,1.157090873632,2.01203916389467));
#2320=CARTESIAN_POINT('',(-7.18472283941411,1.16456992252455,2.00988775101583));
#2321=CARTESIAN_POINT('',(-7.19180957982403,1.17888778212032,2.00496092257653));
#2322=CARTESIAN_POINT('',(-7.1958017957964,1.1857246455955,2.00218369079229));
#2323=CARTESIAN_POINT('',(-7.2066757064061,1.20199204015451,1.99461184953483));
#2324=CARTESIAN_POINT('',(-7.21399706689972,1.21098350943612,1.98950769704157));
#2325=CARTESIAN_POINT('',(-7.22968992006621,1.22745826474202,1.97854864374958));
#2326=CARTESIAN_POINT('',(-7.23806367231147,1.23493821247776,1.9726921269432));
#2327=CARTESIAN_POINT('',(-7.26002471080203,1.25202987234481,1.95730448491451));
#2328=CARTESIAN_POINT('',(-7.27407076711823,1.26074697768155,1.94743787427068));
#2329=CARTESIAN_POINT('',(-7.30305515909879,1.27542742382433,1.9270166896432));
#2330=CARTESIAN_POINT('',(-7.3179948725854,1.2813863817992,1.91646105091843));
#2331=CARTESIAN_POINT('',(-7.34789957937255,1.29067957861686,1.89526726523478));
#2332=CARTESIAN_POINT('',(-7.36285081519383,1.29408608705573,1.88464074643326));
#2333=CARTESIAN_POINT('',(-7.39291956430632,1.29868423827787,1.86320575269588));
#2334=CARTESIAN_POINT('',(-7.40803666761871,1.29988046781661,1.85239770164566));
#2335=CARTESIAN_POINT('',(-7.42390138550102,1.29999715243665,1.84102172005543));
#2336=CARTESIAN_POINT('',(-7.42467244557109,1.29999999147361,1.84046873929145));
#2337=CARTESIAN_POINT('',(-7.42544342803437,1.3,1.83991573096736));
#2338=B_SPLINE_CURVE_WITH_KNOTS('',3,(#2314,#2315,#2316,#2317,#2318,#2319,#2320,#2321,#2322,
#2323,#2324,#2325,#2326,#2327,#2328,#2329,#2330,#2331,#2332,#2333,#2334,#2335,#2336,#2337),
.UNSPECIFIED.,.F.,.F.,(4,2,2,2,2,2,2,2,2,2,2,4),(0.,0.0253956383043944,0.0505125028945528,
0.0755302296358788,0.100621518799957,0.138414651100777,0.176290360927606,0.233730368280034,
0.291261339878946,0.347094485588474,0.402811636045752,0.405658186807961),.UNSPECIFIED.);
#2339=EDGE_CURVE('E631',#1725,#1557,#2338,.T.);
#2340=ORIENTED_EDGE('',*,*,#2339,.F.);
#2341=ORIENTED_EDGE('',*,*,#1764,.F.);
#2342=EDGE_LOOP('',(#2312,#2313,#2340,#2341));
#2343=FACE_BOUND('',#2342,.T.);
#2344=ADVANCED_FACE('F619',(#2343),#2305,.T.);
#2345=CARTESIAN_POINT('',(0.,1.1,0.));
#2346=DIRECTION('',(0.,-1.,0.));
#2347=DIRECTION('',(0.,0.,-1.));
#2348=AXIS2_PLACEMENT_3D('',#2345,#2346,#2347);
#2349=TOROIDAL_SURFACE('',#2348,7.65,0.2);
#2350=ORIENTED_EDGE('',*,*,#2339,.T.);
#2351=ORIENTED_EDGE('',*,*,#1558,.F.);
#2352=CARTESIAN_POINT('',(-5.80316544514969,1.1,4.67180594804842));
#2353=CARTESIAN_POINT('',(-5.803164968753,1.10849589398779,4.67178127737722));
#2354=CARTESIAN_POINT('',(-5.80317570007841,1.11696197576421,4.67265477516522));
#2355=CARTESIAN_POINT('',(-5.80321543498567,1.13348774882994,4.67597512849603));
#2356=CARTESIAN_POINT('',(-5.80324423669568,1.14155088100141,4.67840460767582));
#2357=CARTESIAN_POINT('',(-5.80331598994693,1.157090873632,4.68461023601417));
#2358=CARTESIAN_POINT('',(-5.80335888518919,1.16456992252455,4.6883810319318));
#2359=CARTESIAN_POINT('',(-5.80345375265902,1.17888778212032,4.69701158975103));
#2360=CARTESIAN_POINT('',(-5.80350575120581,1.1857246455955,4.70187452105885));
#2361=CARTESIAN_POINT('',(-5.80364145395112,1.20199204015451,4.71512428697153));
#2362=CARTESIAN_POINT('',(-5.80372788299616,1.21098350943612,4.72404881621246));
#2363=CARTESIAN_POINT('',(-5.80389795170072,1.22745826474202,4.74318876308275));
#2364=CARTESIAN_POINT('',(-5.80398158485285,1.23493821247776,4.75340695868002));
#2365=CARTESIAN_POINT('',(-5.80417785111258,1.25202987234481,4.78022166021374));
#2366=CARTESIAN_POINT('',(-5.80428314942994,1.26074697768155,4.79738646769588));
#2367=CARTESIAN_POINT('',(-5.80445058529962,1.27542742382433,4.83284195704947));
#2368=CARTESIAN_POINT('',(-5.80451265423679,1.2813863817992,4.85113437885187));
#2369=CARTESIAN_POINT('',(-5.80458422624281,1.29067957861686,4.88778765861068));
#2370=CARTESIAN_POINT('',(-5.8045952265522,1.29408608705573,4.90613056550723));
#2371=CARTESIAN_POINT('',(-5.80456538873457,1.29868423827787,4.94305735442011));
#2372=CARTESIAN_POINT('',(-5.80452465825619,1.29988046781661,4.96164065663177));
#2373=CARTESIAN_POINT('',(-5.80445468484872,1.29999715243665,4.98116237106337));
#2374=CARTESIAN_POINT('',(-5.80445121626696,1.29999999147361,4.98211121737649));
#2375=CARTESIAN_POINT('',(-5.80444768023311,1.3,4.98306001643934));
#2376=B_SPLINE_CURVE_WITH_KNOTS('',3,(#2352,#2353,#2354,#2355,#2356,#2357,#2358,#2359,#2360,
#2361,#2362,#2363,#2364,#2365,#2366,#2367,#2368,#2369,#2370,#2371,#2372,#2373,#2374,#2375),
.UNSPECIFIED.,.F.,.F.,(4,2,2,2,2,2,2,2,2,2,2,4),(0.,0.0253956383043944,0.0505125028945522,
0.0755302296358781,0.100621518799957,0.138414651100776,0.176290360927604,0.233730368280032,
0.291261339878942,0.347094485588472,0.402811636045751,0.405658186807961),.UNSPECIFIED.);
#2377=EDGE_CURVE('E624',#1734,#1548,#2376,.T.);
#2378=ORIENTED_EDGE('',*,*,#2377,.F.);
#2379=ORIENTED_EDGE('',*,*,#1735,.F.);
#2380=EDGE_LOOP('',(#2350,#2351,#2378,#2379));
#2381=FACE_BOUND('',#2380,.T.);
#2382=ADVANCED_FACE('F614',(#2381),#2349,.T.);
#2383=CARTESIAN_POINT('',(-5.19879036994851,1.1,2.68114229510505));
#2384=DIRECTION('',(0.,-1.,0.));
#2385=DIRECTION('',(0.,0.,-1.));
#2386=AXIS2_PLACEMENT_3D('',#2383,#2384,#2385);
#2387=TOROIDAL_SURFACE('',#2386,1.02389487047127,0.2);
#2388=ORIENTED_EDGE('',*,*,#2311,.T.);
#2389=ORIENTED_EDGE('',*,*,#1789,.F.);
#2390=CARTESIAN_POINT('',(-4.41695978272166,1.1,3.34227892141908));
#2391=DIRECTION('',(-0.645707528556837,0.,0.763584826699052));
#2392=DIRECTION('',(0.763584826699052,0.,0.645707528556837));
#2393=AXIS2_PLACEMENT_3D('',#2390,#2391,#2392);
#2394=CIRCLE('',#2393,0.2);
#2395=EDGE_CURVE('E491',#1540,#1781,#2394,.T.);
#2396=ORIENTED_EDGE('',*,*,#2395,.F.);
#2397=ORIENTED_EDGE('',*,*,#1541,.F.);
#2398=EDGE_LOOP('',(#2388,#2389,#2396,#2397));
#2399=FACE_BOUND('',#2398,.T.);
#2400=ADVANCED_FACE('F618',(#2399),#2387,.T.);
#2401=CARTESIAN_POINT('',(-4.41695978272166,1.1,3.34227892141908));
#2402=DIRECTION('',(0.645707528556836,0.,-0.763584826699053));
#2403=DIRECTION('',(-0.763584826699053,0.,-0.645707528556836));
#2404=AXIS2_PLACEMENT_3D('',#2401,#2402,#2403);
#2405=CYLINDRICAL_SURFACE('',#2404,0.2);
#2406=ORIENTED_EDGE('',*,*,#2377,.T.);
#2407=ORIENTED_EDGE('',*,*,#1549,.F.);
#2408=ORIENTED_EDGE('',*,*,#2395,.T.);
#2409=ORIENTED_EDGE('',*,*,#1806,.F.);
#2410=EDGE_LOOP('',(#2406,#2407,#2408,#2409));
#2411=FACE_BOUND('',#2410,.T.);
#2412=ADVANCED_FACE('F558',(#2411),#2405,.T.);
#2413=CARTESIAN_POINT('',(-5.79116165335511,3.74653191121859,0.699727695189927));
#2414=DIRECTION('',(-0.957356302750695,-0.277590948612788,0.0800760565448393));
#2415=DIRECTION('',(0.278485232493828,-0.960440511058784,0.));
#2416=AXIS2_PLACEMENT_3D('',#2413,#2414,#2415);
#2417=CIRCLE('',#2416,0.2);
#2418=EDGE_CURVE('E549',#1408,#734,#2417,.T.);
#2419=ORIENTED_EDGE('',*,*,#2418,.F.);
#2420=ORIENTED_EDGE('',*,*,#1514,.F.);
#2421=CARTESIAN_POINT('',(-4.66293082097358,3.9,0.905304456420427));
#2422=DIRECTION('',(0.903076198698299,0.,0.429480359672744));
#2423=DIRECTION('',(0.429480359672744,0.,-0.903076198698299));
#2424=AXIS2_PLACEMENT_3D('',#2421,#2422,#2423);
#2425=CIRCLE('',#2424,0.2);
#2426=EDGE_CURVE('E1272',#828,#1488,#2425,.T.);
#2427=ORIENTED_EDGE('',*,*,#2426,.F.);
#2428=ORIENTED_EDGE('',*,*,#829,.F.);
#2429=EDGE_LOOP('',(#2419,#2420,#2427,#2428));
#2430=FACE_BOUND('',#2429,.T.);
#2431=ADVANCED_FACE('F554',(#2430),#803,.T.);
#2432=CARTESIAN_POINT('',(-5.60778761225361,3.9,2.89207209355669));
#2433=DIRECTION('',(0.,1.,0.));
#2434=DIRECTION('',(0.,0.,1.));
#2435=AXIS2_PLACEMENT_3D('',#2432,#2433,#2434);
#2436=TOROIDAL_SURFACE('',#2435,2.2,0.2);
#2437=ORIENTED_EDGE('',*,*,#2426,.T.);
#2438=ORIENTED_EDGE('',*,*,#1489,.F.);
#2439=CARTESIAN_POINT('',(-3.44122990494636,3.9,3.27420780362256));
#2440=DIRECTION('',(-0.173698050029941,0.,0.984798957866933));
#2441=DIRECTION('',(0.984798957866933,0.,0.173698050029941));
#2442=AXIS2_PLACEMENT_3D('',#2439,#2440,#2441);
#2443=CIRCLE('',#2442,0.2);
#2444=EDGE_CURVE('E530',#425,#1479,#2443,.T.);
#2445=ORIENTED_EDGE('',*,*,#2444,.F.);
#2446=ORIENTED_EDGE('',*,*,#944,.F.);
#2447=EDGE_LOOP('',(#2437,#2438,#2445,#2446));
#2448=FACE_BOUND('',#2447,.T.);
#2449=ADVANCED_FACE('F501',(#2448),#2436,.T.);
#2450=ORIENTED_EDGE('',*,*,#2418,.T.);
#2451=ORIENTED_EDGE('',*,*,#735,.F.);
#2452=CARTESIAN_POINT('',(-8.41845288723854,1.3,1.11260781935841));
#2453=CARTESIAN_POINT('',(-8.42982145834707,1.29999983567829,1.11056530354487));
#2454=CARTESIAN_POINT('',(-8.44097481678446,1.29909412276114,1.10773152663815));
#2455=CARTESIAN_POINT('',(-8.46252765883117,1.29577576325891,1.10081763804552));
#2456=CARTESIAN_POINT('',(-8.47293400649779,1.29337956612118,1.09675137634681));
#2457=CARTESIAN_POINT('',(-8.49541159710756,1.28662455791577,1.08651937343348));
#2458=CARTESIAN_POINT('',(-8.50725289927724,1.281925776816,1.08008298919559));
#2459=CARTESIAN_POINT('',(-8.52958741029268,1.27104791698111,1.0661020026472));
#2460=CARTESIAN_POINT('',(-8.54007294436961,1.26486093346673,1.05855156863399));
#2461=CARTESIAN_POINT('',(-8.56284653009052,1.24910199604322,1.04001249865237));
#2462=CARTESIAN_POINT('',(-8.57457655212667,1.23908828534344,1.02871483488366));
#2463=CARTESIAN_POINT('',(-8.59545505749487,1.21760894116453,1.0052401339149));
#2464=CARTESIAN_POINT('',(-8.60460682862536,1.20614518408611,0.993064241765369));
#2465=CARTESIAN_POINT('',(-8.61998842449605,1.18266518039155,0.968683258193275));
#2466=CARTESIAN_POINT('',(-8.62633027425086,1.17069631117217,0.956503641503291));
#2467=CARTESIAN_POINT('',(-8.63173024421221,1.15772527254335,0.943543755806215));
#2468=CARTESIAN_POINT('',(-8.63199991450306,1.15706824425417,0.942887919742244));
#2469=CARTESIAN_POINT('',(-8.632266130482,1.15641025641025,0.942231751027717));
#2470=B_SPLINE_CURVE_WITH_KNOTS('',3,(#2452,#2453,#2454,#2455,#2456,#2457,#2458,#2459,#2460,
#2461,#2462,#2463,#2464,#2465,#2466,#2467,#2468,#2469),.UNSPECIFIED.,.F.,.F.,(4,2,2,2,2,2,2,2,
4),(0.,0.0344830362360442,0.0685920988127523,0.111187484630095,0.154014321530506,
0.211065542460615,0.268043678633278,0.322483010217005,0.325383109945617),.UNSPECIFIED.);
#2471=EDGE_CURVE('E523',#1577,#632,#2470,.T.);
#2472=ORIENTED_EDGE('',*,*,#2471,.F.);
#2473=ORIENTED_EDGE('',*,*,#1578,.F.);
#2474=ORIENTED_EDGE('',*,*,#1438,.F.);
#2475=EDGE_LOOP('',(#2450,#2451,#2472,#2473,#2474));
#2476=FACE_BOUND('',#2475,.T.);
#2477=ADVANCED_FACE('F493',(#2476),#707,.T.);
#2478=ORIENTED_EDGE('',*,*,#2444,.T.);
#2479=ORIENTED_EDGE('',*,*,#1480,.F.);
#2480=CARTESIAN_POINT('',(-3.9279009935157,3.74653191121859,4.31262865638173));
#2481=DIRECTION('',(-0.620330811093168,-0.277590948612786,0.733575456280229));
#2482=DIRECTION('',(0.763584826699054,0.,0.645707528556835));
#2483=AXIS2_PLACEMENT_3D('',#2480,#2481,#2482);
#2484=CIRCLE('',#2483,0.2);
#2485=EDGE_CURVE('E670',#521,#1384,#2484,.T.);
#2486=ORIENTED_EDGE('',*,*,#2485,.F.);
#2487=ORIENTED_EDGE('',*,*,#522,.F.);
#2488=EDGE_LOOP('',(#2478,#2479,#2486,#2487));
#2489=FACE_BOUND('',#2488,.T.);
#2490=ADVANCED_FACE('F500',(#2489),#496,.T.);
#2491=CARTESIAN_POINT('',(0.,1.1,0.));
#2492=DIRECTION('',(0.,-1.,0.));
#2493=DIRECTION('',(0.,0.,-1.));
#2494=AXIS2_PLACEMENT_3D('',#2491,#2492,#2493);
#2495=TOROIDAL_SURFACE('',#2494,8.49165738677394,0.2);
#2496=ORIENTED_EDGE('',*,*,#2471,.T.);
#2497=ORIENTED_EDGE('',*,*,#633,.F.);
#2498=CARTESIAN_POINT('',(-5.78763574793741,1.3,6.21381667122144));
#2499=CARTESIAN_POINT('',(-5.79256327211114,1.29999983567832,6.22426347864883));
#2500=CARTESIAN_POINT('',(-5.79672133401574,1.29909412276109,6.23499372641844));
#2501=CARTESIAN_POINT('',(-5.80358490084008,1.29577576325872,6.25656264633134));
#2502=CARTESIAN_POINT('',(-5.80630566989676,1.29337956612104,6.26739888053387));
#2503=CARTESIAN_POINT('',(-5.81100199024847,1.28662455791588,6.29164512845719));
#2504=CARTESIAN_POINT('',(-5.81262371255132,1.28192577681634,6.30502472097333));
#2505=CARTESIAN_POINT('',(-5.81418259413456,1.27104791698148,6.33132810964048));
#2506=CARTESIAN_POINT('',(-5.8141105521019,1.26486093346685,6.34424903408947));
#2507=CARTESIAN_POINT('',(-5.81221032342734,1.24910199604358,6.37355300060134));
#2508=CARTESIAN_POINT('',(-5.80980680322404,1.23908828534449,6.38966056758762));
#2509=CARTESIAN_POINT('',(-5.80278648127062,1.21760894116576,6.42028226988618));
#2510=CARTESIAN_POINT('',(-5.79817251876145,1.20614518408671,6.43479842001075));
#2511=CARTESIAN_POINT('',(-5.78722661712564,1.18266518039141,6.46146699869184));
#2512=CARTESIAN_POINT('',(-5.78098038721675,1.17069631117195,6.47369592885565));
#2513=CARTESIAN_POINT('',(-5.77355231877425,1.15772527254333,6.48560987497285));
#2514=CARTESIAN_POINT('',(-5.77317433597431,1.15706824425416,6.48620985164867));
#2515=CARTESIAN_POINT('',(-5.77279407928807,1.15641025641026,6.4868072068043));
#2516=B_SPLINE_CURVE_WITH_KNOTS('',3,(#2498,#2499,#2500,#2501,#2502,#2503,#2504,#2505,#2506,
#2507,#2508,#2509,#2510,#2511,#2512,#2513,#2514,#2515),.UNSPECIFIED.,.F.,.F.,(4,2,2,2,2,2,2,2,
4),(0.,0.0344830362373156,0.0685920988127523,0.111187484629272,0.154014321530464,
0.211065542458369,0.268043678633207,0.322483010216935,0.325383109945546),.UNSPECIFIED.);
#2517=EDGE_CURVE('E642',#1586,#623,#2516,.T.);
#2518=ORIENTED_EDGE('',*,*,#2517,.F.);
#2519=ORIENTED_EDGE('',*,*,#1587,.F.);
#2520=EDGE_LOOP('',(#2496,#2497,#2518,#2519));
#2521=FACE_BOUND('',#2520,.T.);
#2522=ADVANCED_FACE('F537',(#2521),#2495,.T.);
#2523=ORIENTED_EDGE('',*,*,#2485,.T.);
#2524=ORIENTED_EDGE('',*,*,#1385,.F.);
#2525=ORIENTED_EDGE('',*,*,#1596,.F.);
#2526=ORIENTED_EDGE('',*,*,#2517,.T.);
#2527=ORIENTED_EDGE('',*,*,#624,.F.);
#2528=EDGE_LOOP('',(#2523,#2524,#2525,#2526,#2527));
#2529=FACE_BOUND('',#2528,.T.);
#2530=ADVANCED_FACE('F654',(#2529),#596,.T.);
#2531=CLOSED_SHELL('',(#107,#185,#264,#341,#364,#387,#413,#862,#932,#971,#1223,#1241,#1259,
#1296,#1313,#1330,#1342,#1395,#1448,#1526,#1602,#1654,#1668,#1685,#1702,#1714,#1746,#1770,#1795,
#1812,#1920,#1942,#1959,#1981,#1998,#2015,#2037,#2054,#2067,#2080,#2092,#2104,#2124,#2141,#2161,
#2178,#2198,#2215,#2235,#2252,#2264,#2276,#2288,#2300,#2344,#2382,#2400,#2412,#2431,#2449,#2477,
#2490,#2522,#2530));
#2532=MANIFOLD_SOLID_BREP('B2',#2531);
#2533=ADVANCED_BREP_SHAPE_REPRESENTATION('',(#18,#2532),#14);
#2534=SHAPE_DEFINITION_REPRESENTATION(#9,#2533);
ENDSEC;
END-ISO-10303-21;
